# Copyright (c) 1993 - 2025 ARM Limited. All Rights Reserved.
# Use of this Software is subject to the terms and conditions of the
# applicable license agreement with ARM Limited.

# PhyVGen V 11.0.0-beta2
# ARM Version r6p0
# Creation Date: Fri Jan 31 07:39:13 2025


# Memory Configuration:
# ~~~~~~~~~~~~~~~~~~~~~
#  -EOL_guardband 0 -PG_PINS_domain VDDPE -activity_factor 50 -atf off
# -back_biasing off -bit_blast off -bits 64 -bmux off -check_instname on
# -compiler_type sp -diodes on -drive 6 -ema on -flexible_banking 4 -frequency
# 500 -instname sram1024x64 -left_bus_delim "[" -lren_bankmask off -mux 4 -mvt
# BASE -name_case upper -pipeline off -power_gating off -power_type otc -prefix
# "" -pwr_gnd_rename vddpe:VDDPE,vddce:VDDCE,vsse:VSSE -rcols 2 -redundancy off
# -retention on -right_bus_delim "]" -rows_p_bl 256 -rrows 0 -scan off -ser
# none -single_domain_only on -site_def off -vmin_assist on -words 1024
# -write_mask on -write_thru off -corners
# ffg_cbestt_0p88v_0p88v_0c,ffg_cbestt_0p88v_0p88v_125c,ffg_cbestt_0p88v_0p88v_m40c,ssg_cworstt_0p72v_0p72v_0c,ssg_cworstt_0p72v_0p72v_125c,ssg_cworstt_0p72v_0p72v_m40c,tt_typical_0p80v_0p80v_25c,tt_typical_0p80v_0p80v_85c
# 

VERSION 5.8 ;
BUSBITCHARS "[]" ;
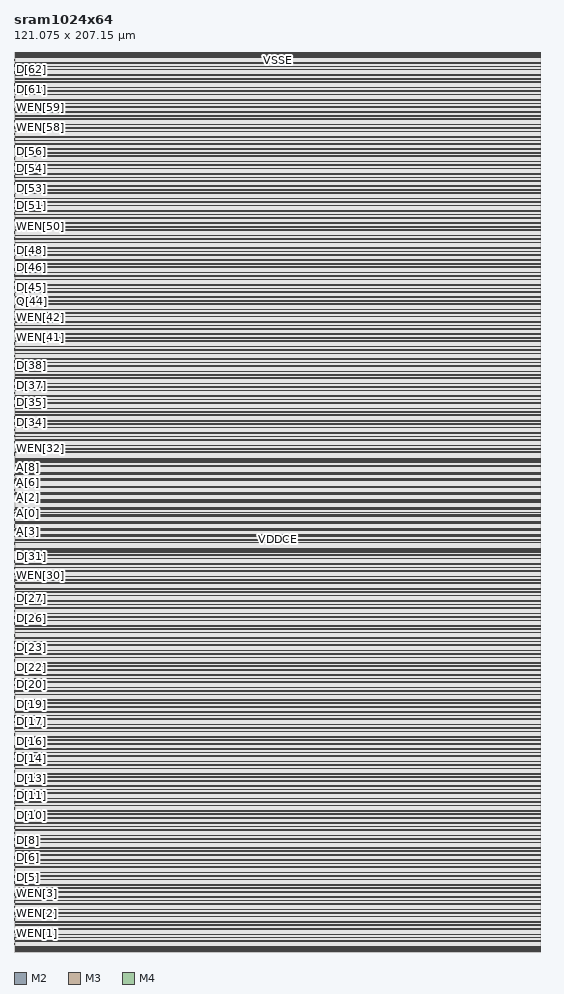
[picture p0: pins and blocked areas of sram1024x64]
MACRO sram1024x64
	FOREIGN sram1024x64 0 0 ;
	SYMMETRY X Y ;
	SIZE 121.075 BY 207.15 ;
	CLASS BLOCK ;
	PIN A[0]
		USE SIGNAL ;
		DIRECTION INPUT ;
		SHAPE ABUTMENT ;
		PORT
			LAYER	M2 ;
			RECT	0.03 100.915 0.15 101.065 ;
			LAYER	M3 ;
			RECT	0.03 100.915 0.15 101.065 ;
		END

		ANTENNAGATEAREA 0.014 ;
		ANTENNADIFFAREA 0.018 ;
		ANTENNAPARTIALMETALAREA 0.025 ;
	END A[0]

	PIN A[1]
		USE SIGNAL ;
		DIRECTION INPUT ;
		SHAPE ABUTMENT ;
		PORT
			LAYER	M2 ;
			RECT	0.03 101.715 0.15 101.865 ;
			LAYER	M3 ;
			RECT	0.03 101.715 0.15 101.865 ;
		END

		ANTENNAGATEAREA 0.014 ;
		ANTENNADIFFAREA 0.018 ;
		ANTENNAPARTIALMETALAREA 0.025 ;
	END A[1]

	PIN A[2]
		USE SIGNAL ;
		DIRECTION INPUT ;
		SHAPE ABUTMENT ;
		PORT
			LAYER	M2 ;
			RECT	0.03 106.315 0.15 106.465 ;
			LAYER	M3 ;
			RECT	0.03 106.315 0.15 106.465 ;
		END

		ANTENNAGATEAREA 0.014 ;
		ANTENNADIFFAREA 0.018 ;
		ANTENNAPARTIALMETALAREA 0.025 ;
	END A[2]

	PIN A[3]
		USE SIGNAL ;
		DIRECTION INPUT ;
		SHAPE ABUTMENT ;
		PORT
			LAYER	M2 ;
			RECT	0.03 96.715 0.15 96.865 ;
			LAYER	M3 ;
			RECT	0.03 96.715 0.15 96.865 ;
		END

		ANTENNAGATEAREA 0.014 ;
		ANTENNADIFFAREA 0.018 ;
		ANTENNAPARTIALMETALAREA 0.025 ;
	END A[3]

	PIN A[4]
		USE SIGNAL ;
		DIRECTION INPUT ;
		SHAPE ABUTMENT ;
		PORT
			LAYER	M2 ;
			RECT	0.03 103.115 0.15 103.265 ;
			LAYER	M3 ;
			RECT	0.03 103.115 0.15 103.265 ;
		END

		ANTENNAGATEAREA 0.014 ;
		ANTENNADIFFAREA 0.018 ;
		ANTENNAPARTIALMETALAREA 0.025 ;
	END A[4]

	PIN A[5]
		USE SIGNAL ;
		DIRECTION INPUT ;
		SHAPE ABUTMENT ;
		PORT
			LAYER	M2 ;
			RECT	0.03 107.115 0.15 107.265 ;
			LAYER	M3 ;
			RECT	0.03 107.115 0.15 107.265 ;
		END

		ANTENNAGATEAREA 0.014 ;
		ANTENNADIFFAREA 0.018 ;
		ANTENNAPARTIALMETALAREA 0.025 ;
	END A[5]

	PIN A[6]
		USE SIGNAL ;
		DIRECTION INPUT ;
		SHAPE ABUTMENT ;
		PORT
			LAYER	M2 ;
			RECT	0.03 107.915 0.15 108.065 ;
			LAYER	M3 ;
			RECT	0.03 107.915 0.15 108.065 ;
		END

		ANTENNAGATEAREA 0.014 ;
		ANTENNADIFFAREA 0.018 ;
		ANTENNAPARTIALMETALAREA 0.025 ;
	END A[6]

	PIN A[7]
		USE SIGNAL ;
		DIRECTION INPUT ;
		SHAPE ABUTMENT ;
		PORT
			LAYER	M2 ;
			RECT	0.03 108.315 0.14 108.665 ;
			LAYER	M3 ;
			RECT	0.03 108.315 0.14 108.665 ;
		END

		ANTENNAGATEAREA 0.014 ;
		ANTENNADIFFAREA 0.018 ;
		ANTENNAPARTIALMETALAREA 0.025 ;
	END A[7]

	PIN A[8]
		USE SIGNAL ;
		DIRECTION INPUT ;
		SHAPE ABUTMENT ;
		PORT
			LAYER	M2 ;
			RECT	0.03 109.715 0.15 109.865 ;
			LAYER	M3 ;
			RECT	0.03 109.715 0.15 109.865 ;
		END

		ANTENNAGATEAREA 0.014 ;
		ANTENNADIFFAREA 0.018 ;
		ANTENNAPARTIALMETALAREA 0.025 ;
	END A[8]

	PIN A[9]
		USE SIGNAL ;
		DIRECTION INPUT ;
		SHAPE ABUTMENT ;
		PORT
			LAYER	M2 ;
			RECT	0.03 110.315 0.15 110.465 ;
			LAYER	M3 ;
			RECT	0.03 110.315 0.15 110.465 ;
		END

		ANTENNAGATEAREA 0.014 ;
		ANTENNADIFFAREA 0.018 ;
		ANTENNAPARTIALMETALAREA 0.025 ;
	END A[9]

	PIN CEN
		USE SIGNAL ;
		DIRECTION INPUT ;
		SHAPE ABUTMENT ;
		PORT
			LAYER	M2 ;
			RECT	0.03 101.315 0.15 101.465 ;
			LAYER	M3 ;
			RECT	0.03 101.315 0.15 101.465 ;
		END

		ANTENNAGATEAREA 0.014 ;
		ANTENNADIFFAREA 0.018 ;
		ANTENNAPARTIALMETALAREA 0.025 ;
	END CEN

	PIN CLK
		USE SIGNAL ;
		DIRECTION INPUT ;
		SHAPE ABUTMENT ;
		PORT
			LAYER	M2 ;
			RECT	0.03 100.315 0.15 100.465 ;
			LAYER	M3 ;
			RECT	0.03 100.315 0.15 100.465 ;
		END

		ANTENNAGATEAREA 0.014 ;
		ANTENNADIFFAREA 0.018 ;
		ANTENNAPARTIALMETALAREA 0.025 ;
	END CLK

	PIN D[0]
		USE SIGNAL ;
		DIRECTION INPUT ;
		SHAPE ABUTMENT ;
		PORT
			LAYER	M2 ;
			RECT	0.03 2.955 0.15 3.105 ;
			LAYER	M3 ;
			RECT	0.03 2.955 0.15 3.105 ;
		END

		ANTENNAGATEAREA 0.014 ;
		ANTENNADIFFAREA 0.018 ;
		ANTENNAPARTIALMETALAREA 0.025 ;
	END D[0]

	PIN D[10]
		USE SIGNAL ;
		DIRECTION INPUT ;
		SHAPE ABUTMENT ;
		PORT
			LAYER	M2 ;
			RECT	0.03 31.355 0.15 31.505 ;
			LAYER	M3 ;
			RECT	0.03 31.355 0.15 31.505 ;
		END

		ANTENNAGATEAREA 0.014 ;
		ANTENNADIFFAREA 0.018 ;
		ANTENNAPARTIALMETALAREA 0.025 ;
	END D[10]

	PIN D[11]
		USE SIGNAL ;
		DIRECTION INPUT ;
		SHAPE ABUTMENT ;
		PORT
			LAYER	M2 ;
			RECT	0.03 34.195 0.15 34.345 ;
			LAYER	M3 ;
			RECT	0.03 34.195 0.15 34.345 ;
		END

		ANTENNAGATEAREA 0.014 ;
		ANTENNADIFFAREA 0.018 ;
		ANTENNAPARTIALMETALAREA 0.025 ;
	END D[11]

	PIN D[12]
		USE SIGNAL ;
		DIRECTION INPUT ;
		SHAPE ABUTMENT ;
		PORT
			LAYER	M2 ;
			RECT	0.03 37.035 0.15 37.185 ;
			LAYER	M3 ;
			RECT	0.03 37.035 0.15 37.185 ;
		END

		ANTENNAGATEAREA 0.014 ;
		ANTENNADIFFAREA 0.018 ;
		ANTENNAPARTIALMETALAREA 0.025 ;
	END D[12]

	PIN D[13]
		USE SIGNAL ;
		DIRECTION INPUT ;
		SHAPE ABUTMENT ;
		PORT
			LAYER	M2 ;
			RECT	0.03 39.875 0.15 40.025 ;
			LAYER	M3 ;
			RECT	0.03 39.875 0.15 40.025 ;
		END

		ANTENNAGATEAREA 0.014 ;
		ANTENNADIFFAREA 0.018 ;
		ANTENNAPARTIALMETALAREA 0.025 ;
	END D[13]

	PIN D[14]
		USE SIGNAL ;
		DIRECTION INPUT ;
		SHAPE ABUTMENT ;
		PORT
			LAYER	M2 ;
			RECT	0.03 42.715 0.15 42.865 ;
			LAYER	M3 ;
			RECT	0.03 42.715 0.15 42.865 ;
		END

		ANTENNAGATEAREA 0.014 ;
		ANTENNADIFFAREA 0.018 ;
		ANTENNAPARTIALMETALAREA 0.025 ;
	END D[14]

	PIN D[15]
		USE SIGNAL ;
		DIRECTION INPUT ;
		SHAPE ABUTMENT ;
		PORT
			LAYER	M2 ;
			RECT	0.03 45.555 0.15 45.705 ;
			LAYER	M3 ;
			RECT	0.03 45.555 0.15 45.705 ;
		END

		ANTENNAGATEAREA 0.014 ;
		ANTENNADIFFAREA 0.018 ;
		ANTENNAPARTIALMETALAREA 0.025 ;
	END D[15]

	PIN D[16]
		USE SIGNAL ;
		DIRECTION INPUT ;
		SHAPE ABUTMENT ;
		PORT
			LAYER	M2 ;
			RECT	0.03 48.395 0.15 48.545 ;
			LAYER	M3 ;
			RECT	0.03 48.395 0.15 48.545 ;
		END

		ANTENNAGATEAREA 0.014 ;
		ANTENNADIFFAREA 0.018 ;
		ANTENNAPARTIALMETALAREA 0.025 ;
	END D[16]

	PIN D[17]
		USE SIGNAL ;
		DIRECTION INPUT ;
		SHAPE ABUTMENT ;
		PORT
			LAYER	M2 ;
			RECT	0.03 51.235 0.15 51.385 ;
			LAYER	M3 ;
			RECT	0.03 51.235 0.15 51.385 ;
		END

		ANTENNAGATEAREA 0.014 ;
		ANTENNADIFFAREA 0.018 ;
		ANTENNAPARTIALMETALAREA 0.025 ;
	END D[17]

	PIN D[18]
		USE SIGNAL ;
		DIRECTION INPUT ;
		SHAPE ABUTMENT ;
		PORT
			LAYER	M2 ;
			RECT	0.03 54.075 0.15 54.225 ;
			LAYER	M3 ;
			RECT	0.03 54.075 0.15 54.225 ;
		END

		ANTENNAGATEAREA 0.014 ;
		ANTENNADIFFAREA 0.018 ;
		ANTENNAPARTIALMETALAREA 0.025 ;
	END D[18]

	PIN D[19]
		USE SIGNAL ;
		DIRECTION INPUT ;
		SHAPE ABUTMENT ;
		PORT
			LAYER	M2 ;
			RECT	0.03 56.915 0.15 57.065 ;
			LAYER	M3 ;
			RECT	0.03 56.915 0.15 57.065 ;
		END

		ANTENNAGATEAREA 0.014 ;
		ANTENNADIFFAREA 0.018 ;
		ANTENNAPARTIALMETALAREA 0.025 ;
	END D[19]

	PIN D[1]
		USE SIGNAL ;
		DIRECTION INPUT ;
		SHAPE ABUTMENT ;
		PORT
			LAYER	M2 ;
			RECT	0.03 5.795 0.15 5.945 ;
			LAYER	M3 ;
			RECT	0.03 5.795 0.15 5.945 ;
		END

		ANTENNAGATEAREA 0.014 ;
		ANTENNADIFFAREA 0.018 ;
		ANTENNAPARTIALMETALAREA 0.025 ;
	END D[1]

	PIN D[20]
		USE SIGNAL ;
		DIRECTION INPUT ;
		SHAPE ABUTMENT ;
		PORT
			LAYER	M2 ;
			RECT	0.03 59.755 0.15 59.905 ;
			LAYER	M3 ;
			RECT	0.03 59.755 0.15 59.905 ;
		END

		ANTENNAGATEAREA 0.014 ;
		ANTENNADIFFAREA 0.018 ;
		ANTENNAPARTIALMETALAREA 0.025 ;
	END D[20]

	PIN D[21]
		USE SIGNAL ;
		DIRECTION INPUT ;
		SHAPE ABUTMENT ;
		PORT
			LAYER	M2 ;
			RECT	0.03 62.595 0.15 62.745 ;
			LAYER	M3 ;
			RECT	0.03 62.595 0.15 62.745 ;
		END

		ANTENNAGATEAREA 0.014 ;
		ANTENNADIFFAREA 0.018 ;
		ANTENNAPARTIALMETALAREA 0.025 ;
	END D[21]

	PIN D[22]
		USE SIGNAL ;
		DIRECTION INPUT ;
		SHAPE ABUTMENT ;
		PORT
			LAYER	M2 ;
			RECT	0.03 65.435 0.15 65.585 ;
			LAYER	M3 ;
			RECT	0.03 65.435 0.15 65.585 ;
		END

		ANTENNAGATEAREA 0.014 ;
		ANTENNADIFFAREA 0.018 ;
		ANTENNAPARTIALMETALAREA 0.025 ;
	END D[22]

	PIN D[23]
		USE SIGNAL ;
		DIRECTION INPUT ;
		SHAPE ABUTMENT ;
		PORT
			LAYER	M2 ;
			RECT	0.03 68.275 0.15 68.425 ;
			LAYER	M3 ;
			RECT	0.03 68.275 0.15 68.425 ;
		END

		ANTENNAGATEAREA 0.014 ;
		ANTENNADIFFAREA 0.018 ;
		ANTENNAPARTIALMETALAREA 0.025 ;
	END D[23]

	PIN D[24]
		USE SIGNAL ;
		DIRECTION INPUT ;
		SHAPE ABUTMENT ;
		PORT
			LAYER	M2 ;
			RECT	0.03 71.115 0.15 71.265 ;
			LAYER	M3 ;
			RECT	0.03 71.115 0.15 71.265 ;
		END

		ANTENNAGATEAREA 0.014 ;
		ANTENNADIFFAREA 0.018 ;
		ANTENNAPARTIALMETALAREA 0.025 ;
	END D[24]

	PIN D[25]
		USE SIGNAL ;
		DIRECTION INPUT ;
		SHAPE ABUTMENT ;
		PORT
			LAYER	M2 ;
			RECT	0.03 73.955 0.15 74.105 ;
			LAYER	M3 ;
			RECT	0.03 73.955 0.15 74.105 ;
		END

		ANTENNAGATEAREA 0.014 ;
		ANTENNADIFFAREA 0.018 ;
		ANTENNAPARTIALMETALAREA 0.025 ;
	END D[25]

	PIN D[26]
		USE SIGNAL ;
		DIRECTION INPUT ;
		SHAPE ABUTMENT ;
		PORT
			LAYER	M2 ;
			RECT	0.03 76.795 0.15 76.945 ;
			LAYER	M3 ;
			RECT	0.03 76.795 0.15 76.945 ;
		END

		ANTENNAGATEAREA 0.014 ;
		ANTENNADIFFAREA 0.018 ;
		ANTENNAPARTIALMETALAREA 0.025 ;
	END D[26]

	PIN D[27]
		USE SIGNAL ;
		DIRECTION INPUT ;
		SHAPE ABUTMENT ;
		PORT
			LAYER	M2 ;
			RECT	0.03 79.635 0.15 79.785 ;
			LAYER	M3 ;
			RECT	0.03 79.635 0.15 79.785 ;
		END

		ANTENNAGATEAREA 0.014 ;
		ANTENNADIFFAREA 0.018 ;
		ANTENNAPARTIALMETALAREA 0.025 ;
	END D[27]

	PIN D[28]
		USE SIGNAL ;
		DIRECTION INPUT ;
		SHAPE ABUTMENT ;
		PORT
			LAYER	M2 ;
			RECT	0.03 82.475 0.15 82.625 ;
			LAYER	M3 ;
			RECT	0.03 82.475 0.15 82.625 ;
		END

		ANTENNAGATEAREA 0.014 ;
		ANTENNADIFFAREA 0.018 ;
		ANTENNAPARTIALMETALAREA 0.025 ;
	END D[28]

	PIN D[29]
		USE SIGNAL ;
		DIRECTION INPUT ;
		SHAPE ABUTMENT ;
		PORT
			LAYER	M2 ;
			RECT	0.03 85.315 0.15 85.465 ;
			LAYER	M3 ;
			RECT	0.03 85.315 0.15 85.465 ;
		END

		ANTENNAGATEAREA 0.014 ;
		ANTENNADIFFAREA 0.018 ;
		ANTENNAPARTIALMETALAREA 0.025 ;
	END D[29]

	PIN D[2]
		USE SIGNAL ;
		DIRECTION INPUT ;
		SHAPE ABUTMENT ;
		PORT
			LAYER	M2 ;
			RECT	0.03 8.635 0.15 8.785 ;
			LAYER	M3 ;
			RECT	0.03 8.635 0.15 8.785 ;
		END

		ANTENNAGATEAREA 0.014 ;
		ANTENNADIFFAREA 0.018 ;
		ANTENNAPARTIALMETALAREA 0.025 ;
	END D[2]

	PIN D[30]
		USE SIGNAL ;
		DIRECTION INPUT ;
		SHAPE ABUTMENT ;
		PORT
			LAYER	M2 ;
			RECT	0.03 88.155 0.15 88.305 ;
			LAYER	M3 ;
			RECT	0.03 88.155 0.15 88.305 ;
		END

		ANTENNAGATEAREA 0.014 ;
		ANTENNADIFFAREA 0.018 ;
		ANTENNAPARTIALMETALAREA 0.025 ;
	END D[30]

	PIN D[31]
		USE SIGNAL ;
		DIRECTION INPUT ;
		SHAPE ABUTMENT ;
		PORT
			LAYER	M2 ;
			RECT	0.03 90.995 0.15 91.145 ;
			LAYER	M3 ;
			RECT	0.03 90.995 0.15 91.145 ;
		END

		ANTENNAGATEAREA 0.014 ;
		ANTENNADIFFAREA 0.018 ;
		ANTENNAPARTIALMETALAREA 0.025 ;
	END D[31]

	PIN D[32]
		USE SIGNAL ;
		DIRECTION INPUT ;
		SHAPE ABUTMENT ;
		PORT
			LAYER	M2 ;
			RECT	0.03 116.005 0.15 116.155 ;
			LAYER	M3 ;
			RECT	0.03 116.005 0.15 116.155 ;
		END

		ANTENNAGATEAREA 0.014 ;
		ANTENNADIFFAREA 0.018 ;
		ANTENNAPARTIALMETALAREA 0.025 ;
	END D[32]

	PIN D[33]
		USE SIGNAL ;
		DIRECTION INPUT ;
		SHAPE ABUTMENT ;
		PORT
			LAYER	M2 ;
			RECT	0.03 118.845 0.15 118.995 ;
			LAYER	M3 ;
			RECT	0.03 118.845 0.15 118.995 ;
		END

		ANTENNAGATEAREA 0.014 ;
		ANTENNADIFFAREA 0.018 ;
		ANTENNAPARTIALMETALAREA 0.025 ;
	END D[33]

	PIN D[34]
		USE SIGNAL ;
		DIRECTION INPUT ;
		SHAPE ABUTMENT ;
		PORT
			LAYER	M2 ;
			RECT	0.03 121.685 0.15 121.835 ;
			LAYER	M3 ;
			RECT	0.03 121.685 0.15 121.835 ;
		END

		ANTENNAGATEAREA 0.014 ;
		ANTENNADIFFAREA 0.018 ;
		ANTENNAPARTIALMETALAREA 0.025 ;
	END D[34]

	PIN D[35]
		USE SIGNAL ;
		DIRECTION INPUT ;
		SHAPE ABUTMENT ;
		PORT
			LAYER	M2 ;
			RECT	0.03 124.525 0.15 124.675 ;
			LAYER	M3 ;
			RECT	0.03 124.525 0.15 124.675 ;
		END

		ANTENNAGATEAREA 0.014 ;
		ANTENNADIFFAREA 0.018 ;
		ANTENNAPARTIALMETALAREA 0.025 ;
	END D[35]

	PIN D[36]
		USE SIGNAL ;
		DIRECTION INPUT ;
		SHAPE ABUTMENT ;
		PORT
			LAYER	M2 ;
			RECT	0.03 127.365 0.15 127.515 ;
			LAYER	M3 ;
			RECT	0.03 127.365 0.15 127.515 ;
		END

		ANTENNAGATEAREA 0.014 ;
		ANTENNADIFFAREA 0.018 ;
		ANTENNAPARTIALMETALAREA 0.025 ;
	END D[36]

	PIN D[37]
		USE SIGNAL ;
		DIRECTION INPUT ;
		SHAPE ABUTMENT ;
		PORT
			LAYER	M2 ;
			RECT	0.03 130.205 0.15 130.355 ;
			LAYER	M3 ;
			RECT	0.03 130.205 0.15 130.355 ;
		END

		ANTENNAGATEAREA 0.014 ;
		ANTENNADIFFAREA 0.018 ;
		ANTENNAPARTIALMETALAREA 0.025 ;
	END D[37]

	PIN D[38]
		USE SIGNAL ;
		DIRECTION INPUT ;
		SHAPE ABUTMENT ;
		PORT
			LAYER	M2 ;
			RECT	0.03 133.045 0.15 133.195 ;
			LAYER	M3 ;
			RECT	0.03 133.045 0.15 133.195 ;
		END

		ANTENNAGATEAREA 0.014 ;
		ANTENNADIFFAREA 0.018 ;
		ANTENNAPARTIALMETALAREA 0.025 ;
	END D[38]

	PIN D[39]
		USE SIGNAL ;
		DIRECTION INPUT ;
		SHAPE ABUTMENT ;
		PORT
			LAYER	M2 ;
			RECT	0.03 135.885 0.15 136.035 ;
			LAYER	M3 ;
			RECT	0.03 135.885 0.15 136.035 ;
		END

		ANTENNAGATEAREA 0.014 ;
		ANTENNADIFFAREA 0.018 ;
		ANTENNAPARTIALMETALAREA 0.025 ;
	END D[39]

	PIN D[3]
		USE SIGNAL ;
		DIRECTION INPUT ;
		SHAPE ABUTMENT ;
		PORT
			LAYER	M2 ;
			RECT	0.03 11.475 0.15 11.625 ;
			LAYER	M3 ;
			RECT	0.03 11.475 0.15 11.625 ;
		END

		ANTENNAGATEAREA 0.014 ;
		ANTENNADIFFAREA 0.018 ;
		ANTENNAPARTIALMETALAREA 0.025 ;
	END D[3]

	PIN D[40]
		USE SIGNAL ;
		DIRECTION INPUT ;
		SHAPE ABUTMENT ;
		PORT
			LAYER	M2 ;
			RECT	0.03 138.725 0.15 138.875 ;
			LAYER	M3 ;
			RECT	0.03 138.725 0.15 138.875 ;
		END

		ANTENNAGATEAREA 0.014 ;
		ANTENNADIFFAREA 0.018 ;
		ANTENNAPARTIALMETALAREA 0.025 ;
	END D[40]

	PIN D[41]
		USE SIGNAL ;
		DIRECTION INPUT ;
		SHAPE ABUTMENT ;
		PORT
			LAYER	M2 ;
			RECT	0.03 141.565 0.15 141.715 ;
			LAYER	M3 ;
			RECT	0.03 141.565 0.15 141.715 ;
		END

		ANTENNAGATEAREA 0.014 ;
		ANTENNADIFFAREA 0.018 ;
		ANTENNAPARTIALMETALAREA 0.025 ;
	END D[41]

	PIN D[42]
		USE SIGNAL ;
		DIRECTION INPUT ;
		SHAPE ABUTMENT ;
		PORT
			LAYER	M2 ;
			RECT	0.03 144.405 0.15 144.555 ;
			LAYER	M3 ;
			RECT	0.03 144.405 0.15 144.555 ;
		END

		ANTENNAGATEAREA 0.014 ;
		ANTENNADIFFAREA 0.018 ;
		ANTENNAPARTIALMETALAREA 0.025 ;
	END D[42]

	PIN D[43]
		USE SIGNAL ;
		DIRECTION INPUT ;
		SHAPE ABUTMENT ;
		PORT
			LAYER	M2 ;
			RECT	0.03 147.245 0.15 147.395 ;
			LAYER	M3 ;
			RECT	0.03 147.245 0.15 147.395 ;
		END

		ANTENNAGATEAREA 0.014 ;
		ANTENNADIFFAREA 0.018 ;
		ANTENNAPARTIALMETALAREA 0.025 ;
	END D[43]

	PIN D[44]
		USE SIGNAL ;
		DIRECTION INPUT ;
		SHAPE ABUTMENT ;
		PORT
			LAYER	M2 ;
			RECT	0.03 150.085 0.15 150.235 ;
			LAYER	M3 ;
			RECT	0.03 150.085 0.15 150.235 ;
		END

		ANTENNAGATEAREA 0.014 ;
		ANTENNADIFFAREA 0.018 ;
		ANTENNAPARTIALMETALAREA 0.025 ;
	END D[44]

	PIN D[45]
		USE SIGNAL ;
		DIRECTION INPUT ;
		SHAPE ABUTMENT ;
		PORT
			LAYER	M2 ;
			RECT	0.03 152.925 0.15 153.075 ;
			LAYER	M3 ;
			RECT	0.03 152.925 0.15 153.075 ;
		END

		ANTENNAGATEAREA 0.014 ;
		ANTENNADIFFAREA 0.018 ;
		ANTENNAPARTIALMETALAREA 0.025 ;
	END D[45]

	PIN D[46]
		USE SIGNAL ;
		DIRECTION INPUT ;
		SHAPE ABUTMENT ;
		PORT
			LAYER	M2 ;
			RECT	0.03 155.765 0.15 155.915 ;
			LAYER	M3 ;
			RECT	0.03 155.765 0.15 155.915 ;
		END

		ANTENNAGATEAREA 0.014 ;
		ANTENNADIFFAREA 0.018 ;
		ANTENNAPARTIALMETALAREA 0.025 ;
	END D[46]

	PIN D[47]
		USE SIGNAL ;
		DIRECTION INPUT ;
		SHAPE ABUTMENT ;
		PORT
			LAYER	M2 ;
			RECT	0.03 158.605 0.15 158.755 ;
			LAYER	M3 ;
			RECT	0.03 158.605 0.15 158.755 ;
		END

		ANTENNAGATEAREA 0.014 ;
		ANTENNADIFFAREA 0.018 ;
		ANTENNAPARTIALMETALAREA 0.025 ;
	END D[47]

	PIN D[48]
		USE SIGNAL ;
		DIRECTION INPUT ;
		SHAPE ABUTMENT ;
		PORT
			LAYER	M2 ;
			RECT	0.03 161.445 0.15 161.595 ;
			LAYER	M3 ;
			RECT	0.03 161.445 0.15 161.595 ;
		END

		ANTENNAGATEAREA 0.014 ;
		ANTENNADIFFAREA 0.018 ;
		ANTENNAPARTIALMETALAREA 0.025 ;
	END D[48]

	PIN D[49]
		USE SIGNAL ;
		DIRECTION INPUT ;
		SHAPE ABUTMENT ;
		PORT
			LAYER	M2 ;
			RECT	0.03 164.285 0.15 164.435 ;
			LAYER	M3 ;
			RECT	0.03 164.285 0.15 164.435 ;
		END

		ANTENNAGATEAREA 0.014 ;
		ANTENNADIFFAREA 0.018 ;
		ANTENNAPARTIALMETALAREA 0.025 ;
	END D[49]

	PIN D[4]
		USE SIGNAL ;
		DIRECTION INPUT ;
		SHAPE ABUTMENT ;
		PORT
			LAYER	M2 ;
			RECT	0.03 14.315 0.15 14.465 ;
			LAYER	M3 ;
			RECT	0.03 14.315 0.15 14.465 ;
		END

		ANTENNAGATEAREA 0.014 ;
		ANTENNADIFFAREA 0.018 ;
		ANTENNAPARTIALMETALAREA 0.025 ;
	END D[4]

	PIN D[50]
		USE SIGNAL ;
		DIRECTION INPUT ;
		SHAPE ABUTMENT ;
		PORT
			LAYER	M2 ;
			RECT	0.03 167.125 0.15 167.275 ;
			LAYER	M3 ;
			RECT	0.03 167.125 0.15 167.275 ;
		END

		ANTENNAGATEAREA 0.014 ;
		ANTENNADIFFAREA 0.018 ;
		ANTENNAPARTIALMETALAREA 0.025 ;
	END D[50]

	PIN D[51]
		USE SIGNAL ;
		DIRECTION INPUT ;
		SHAPE ABUTMENT ;
		PORT
			LAYER	M2 ;
			RECT	0.03 169.965 0.15 170.115 ;
			LAYER	M3 ;
			RECT	0.03 169.965 0.15 170.115 ;
		END

		ANTENNAGATEAREA 0.014 ;
		ANTENNADIFFAREA 0.018 ;
		ANTENNAPARTIALMETALAREA 0.025 ;
	END D[51]

	PIN D[52]
		USE SIGNAL ;
		DIRECTION INPUT ;
		SHAPE ABUTMENT ;
		PORT
			LAYER	M2 ;
			RECT	0.03 172.805 0.15 172.955 ;
			LAYER	M3 ;
			RECT	0.03 172.805 0.15 172.955 ;
		END

		ANTENNAGATEAREA 0.014 ;
		ANTENNADIFFAREA 0.018 ;
		ANTENNAPARTIALMETALAREA 0.025 ;
	END D[52]

	PIN D[53]
		USE SIGNAL ;
		DIRECTION INPUT ;
		SHAPE ABUTMENT ;
		PORT
			LAYER	M2 ;
			RECT	0.03 175.645 0.15 175.795 ;
			LAYER	M3 ;
			RECT	0.03 175.645 0.15 175.795 ;
		END

		ANTENNAGATEAREA 0.014 ;
		ANTENNADIFFAREA 0.018 ;
		ANTENNAPARTIALMETALAREA 0.025 ;
	END D[53]

	PIN D[54]
		USE SIGNAL ;
		DIRECTION INPUT ;
		SHAPE ABUTMENT ;
		PORT
			LAYER	M2 ;
			RECT	0.03 178.485 0.15 178.635 ;
			LAYER	M3 ;
			RECT	0.03 178.485 0.15 178.635 ;
		END

		ANTENNAGATEAREA 0.014 ;
		ANTENNADIFFAREA 0.018 ;
		ANTENNAPARTIALMETALAREA 0.025 ;
	END D[54]

	PIN D[55]
		USE SIGNAL ;
		DIRECTION INPUT ;
		SHAPE ABUTMENT ;
		PORT
			LAYER	M2 ;
			RECT	0.03 181.325 0.15 181.475 ;
			LAYER	M3 ;
			RECT	0.03 181.325 0.15 181.475 ;
		END

		ANTENNAGATEAREA 0.014 ;
		ANTENNADIFFAREA 0.018 ;
		ANTENNAPARTIALMETALAREA 0.025 ;
	END D[55]

	PIN D[56]
		USE SIGNAL ;
		DIRECTION INPUT ;
		SHAPE ABUTMENT ;
		PORT
			LAYER	M2 ;
			RECT	0.03 184.165 0.15 184.315 ;
			LAYER	M3 ;
			RECT	0.03 184.165 0.15 184.315 ;
		END

		ANTENNAGATEAREA 0.014 ;
		ANTENNADIFFAREA 0.018 ;
		ANTENNAPARTIALMETALAREA 0.025 ;
	END D[56]

	PIN D[57]
		USE SIGNAL ;
		DIRECTION INPUT ;
		SHAPE ABUTMENT ;
		PORT
			LAYER	M2 ;
			RECT	0.03 187.005 0.15 187.155 ;
			LAYER	M3 ;
			RECT	0.03 187.005 0.15 187.155 ;
		END

		ANTENNAGATEAREA 0.014 ;
		ANTENNADIFFAREA 0.018 ;
		ANTENNAPARTIALMETALAREA 0.025 ;
	END D[57]

	PIN D[58]
		USE SIGNAL ;
		DIRECTION INPUT ;
		SHAPE ABUTMENT ;
		PORT
			LAYER	M2 ;
			RECT	0.03 189.845 0.15 189.995 ;
			LAYER	M3 ;
			RECT	0.03 189.845 0.15 189.995 ;
		END

		ANTENNAGATEAREA 0.014 ;
		ANTENNADIFFAREA 0.018 ;
		ANTENNAPARTIALMETALAREA 0.025 ;
	END D[58]

	PIN D[59]
		USE SIGNAL ;
		DIRECTION INPUT ;
		SHAPE ABUTMENT ;
		PORT
			LAYER	M2 ;
			RECT	0.03 192.685 0.15 192.835 ;
			LAYER	M3 ;
			RECT	0.03 192.685 0.15 192.835 ;
		END

		ANTENNAGATEAREA 0.014 ;
		ANTENNADIFFAREA 0.018 ;
		ANTENNAPARTIALMETALAREA 0.025 ;
	END D[59]

	PIN D[5]
		USE SIGNAL ;
		DIRECTION INPUT ;
		SHAPE ABUTMENT ;
		PORT
			LAYER	M2 ;
			RECT	0.03 17.155 0.15 17.305 ;
			LAYER	M3 ;
			RECT	0.03 17.155 0.15 17.305 ;
		END

		ANTENNAGATEAREA 0.014 ;
		ANTENNADIFFAREA 0.018 ;
		ANTENNAPARTIALMETALAREA 0.025 ;
	END D[5]

	PIN D[60]
		USE SIGNAL ;
		DIRECTION INPUT ;
		SHAPE ABUTMENT ;
		PORT
			LAYER	M2 ;
			RECT	0.03 195.525 0.15 195.675 ;
			LAYER	M3 ;
			RECT	0.03 195.525 0.15 195.675 ;
		END

		ANTENNAGATEAREA 0.014 ;
		ANTENNADIFFAREA 0.018 ;
		ANTENNAPARTIALMETALAREA 0.025 ;
	END D[60]

	PIN D[61]
		USE SIGNAL ;
		DIRECTION INPUT ;
		SHAPE ABUTMENT ;
		PORT
			LAYER	M2 ;
			RECT	0.03 198.365 0.15 198.515 ;
			LAYER	M3 ;
			RECT	0.03 198.365 0.15 198.515 ;
		END

		ANTENNAGATEAREA 0.014 ;
		ANTENNADIFFAREA 0.018 ;
		ANTENNAPARTIALMETALAREA 0.025 ;
	END D[61]

	PIN D[62]
		USE SIGNAL ;
		DIRECTION INPUT ;
		SHAPE ABUTMENT ;
		PORT
			LAYER	M2 ;
			RECT	0.03 201.205 0.15 201.355 ;
			LAYER	M3 ;
			RECT	0.03 201.205 0.15 201.355 ;
		END

		ANTENNAGATEAREA 0.014 ;
		ANTENNADIFFAREA 0.018 ;
		ANTENNAPARTIALMETALAREA 0.025 ;
	END D[62]

	PIN D[63]
		USE SIGNAL ;
		DIRECTION INPUT ;
		SHAPE ABUTMENT ;
		PORT
			LAYER	M2 ;
			RECT	0.03 204.045 0.15 204.195 ;
			LAYER	M3 ;
			RECT	0.03 204.045 0.15 204.195 ;
		END

		ANTENNAGATEAREA 0.014 ;
		ANTENNADIFFAREA 0.018 ;
		ANTENNAPARTIALMETALAREA 0.025 ;
	END D[63]

	PIN D[6]
		USE SIGNAL ;
		DIRECTION INPUT ;
		SHAPE ABUTMENT ;
		PORT
			LAYER	M2 ;
			RECT	0.03 19.995 0.15 20.145 ;
			LAYER	M3 ;
			RECT	0.03 19.995 0.15 20.145 ;
		END

		ANTENNAGATEAREA 0.014 ;
		ANTENNADIFFAREA 0.018 ;
		ANTENNAPARTIALMETALAREA 0.025 ;
	END D[6]

	PIN D[7]
		USE SIGNAL ;
		DIRECTION INPUT ;
		SHAPE ABUTMENT ;
		PORT
			LAYER	M2 ;
			RECT	0.03 22.835 0.15 22.985 ;
			LAYER	M3 ;
			RECT	0.03 22.835 0.15 22.985 ;
		END

		ANTENNAGATEAREA 0.014 ;
		ANTENNADIFFAREA 0.018 ;
		ANTENNAPARTIALMETALAREA 0.025 ;
	END D[7]

	PIN D[8]
		USE SIGNAL ;
		DIRECTION INPUT ;
		SHAPE ABUTMENT ;
		PORT
			LAYER	M2 ;
			RECT	0.03 25.675 0.15 25.825 ;
			LAYER	M3 ;
			RECT	0.03 25.675 0.15 25.825 ;
		END

		ANTENNAGATEAREA 0.014 ;
		ANTENNADIFFAREA 0.018 ;
		ANTENNAPARTIALMETALAREA 0.025 ;
	END D[8]

	PIN D[9]
		USE SIGNAL ;
		DIRECTION INPUT ;
		SHAPE ABUTMENT ;
		PORT
			LAYER	M2 ;
			RECT	0.03 28.515 0.15 28.665 ;
			LAYER	M3 ;
			RECT	0.03 28.515 0.15 28.665 ;
		END

		ANTENNAGATEAREA 0.014 ;
		ANTENNADIFFAREA 0.018 ;
		ANTENNAPARTIALMETALAREA 0.025 ;
	END D[9]

	PIN EMAS
		USE SIGNAL ;
		DIRECTION INPUT ;
		SHAPE ABUTMENT ;
		PORT
			LAYER	M2 ;
			RECT	0.03 99.515 0.15 99.665 ;
			LAYER	M3 ;
			RECT	0.03 99.515 0.15 99.665 ;
		END

		ANTENNAGATEAREA 0.014 ;
		ANTENNADIFFAREA 0.018 ;
		ANTENNAPARTIALMETALAREA 0.025 ;
	END EMAS

	PIN EMAW[0]
		USE SIGNAL ;
		DIRECTION INPUT ;
		SHAPE ABUTMENT ;
		PORT
			LAYER	M2 ;
			RECT	0.03 99.915 0.15 100.065 ;
			LAYER	M3 ;
			RECT	0.03 99.915 0.15 100.065 ;
		END

		ANTENNAGATEAREA 0.014 ;
		ANTENNADIFFAREA 0.018 ;
		ANTENNAPARTIALMETALAREA 0.025 ;
	END EMAW[0]

	PIN EMAW[1]
		USE SIGNAL ;
		DIRECTION INPUT ;
		SHAPE ABUTMENT ;
		PORT
			LAYER	M2 ;
			RECT	0.03 99.315 0.15 99.465 ;
			LAYER	M3 ;
			RECT	0.03 99.315 0.15 99.465 ;
		END

		ANTENNAGATEAREA 0.014 ;
		ANTENNADIFFAREA 0.018 ;
		ANTENNAPARTIALMETALAREA 0.025 ;
	END EMAW[1]

	PIN EMA[0]
		USE SIGNAL ;
		DIRECTION INPUT ;
		SHAPE ABUTMENT ;
		PORT
			LAYER	M2 ;
			RECT	0.03 97.815 0.14 98.165 ;
			LAYER	M3 ;
			RECT	0.03 97.815 0.14 98.165 ;
		END

		ANTENNAGATEAREA 0.014 ;
		ANTENNADIFFAREA 0.018 ;
		ANTENNAPARTIALMETALAREA 0.025 ;
	END EMA[0]

	PIN EMA[1]
		USE SIGNAL ;
		DIRECTION INPUT ;
		SHAPE ABUTMENT ;
		PORT
			LAYER	M2 ;
			RECT	0.03 97.615 0.15 97.765 ;
			LAYER	M3 ;
			RECT	0.03 97.615 0.15 97.765 ;
		END

		ANTENNAGATEAREA 0.014 ;
		ANTENNADIFFAREA 0.018 ;
		ANTENNAPARTIALMETALAREA 0.025 ;
	END EMA[1]

	PIN EMA[2]
		USE SIGNAL ;
		DIRECTION INPUT ;
		SHAPE ABUTMENT ;
		PORT
			LAYER	M2 ;
			RECT	0.03 97.115 0.15 97.265 ;
			LAYER	M3 ;
			RECT	0.03 97.115 0.15 97.265 ;
		END

		ANTENNAGATEAREA 0.014 ;
		ANTENNADIFFAREA 0.018 ;
		ANTENNAPARTIALMETALAREA 0.025 ;
	END EMA[2]

	PIN GWEN
		USE SIGNAL ;
		DIRECTION INPUT ;
		SHAPE ABUTMENT ;
		PORT
			LAYER	M2 ;
			RECT	0.03 95.815 0.15 95.965 ;
			LAYER	M3 ;
			RECT	0.03 95.815 0.15 95.965 ;
		END

		ANTENNAGATEAREA 0.014 ;
		ANTENNADIFFAREA 0.018 ;
		ANTENNAPARTIALMETALAREA 0.025 ;
	END GWEN

	PIN Q[0]
		USE SIGNAL ;
		DIRECTION OUTPUT ;
		SHAPE ABUTMENT ;
		PORT
			LAYER	M2 ;
			RECT	0.03 1.645 0.14 1.995 ;
			LAYER	M3 ;
			RECT	0.03 1.645 0.14 1.995 ;
		END

		ANTENNADIFFAREA 0.018 ;
		ANTENNAPARTIALMETALAREA 0.025 ;
	END Q[0]

	PIN Q[10]
		USE SIGNAL ;
		DIRECTION OUTPUT ;
		SHAPE ABUTMENT ;
		PORT
			LAYER	M2 ;
			RECT	0.03 30.045 0.14 30.395 ;
			LAYER	M3 ;
			RECT	0.03 30.045 0.14 30.395 ;
		END

		ANTENNADIFFAREA 0.018 ;
		ANTENNAPARTIALMETALAREA 0.025 ;
	END Q[10]

	PIN Q[11]
		USE SIGNAL ;
		DIRECTION OUTPUT ;
		SHAPE ABUTMENT ;
		PORT
			LAYER	M2 ;
			RECT	0.03 32.885 0.14 33.235 ;
			LAYER	M3 ;
			RECT	0.03 32.885 0.14 33.235 ;
		END

		ANTENNADIFFAREA 0.018 ;
		ANTENNAPARTIALMETALAREA 0.025 ;
	END Q[11]

	PIN Q[12]
		USE SIGNAL ;
		DIRECTION OUTPUT ;
		SHAPE ABUTMENT ;
		PORT
			LAYER	M2 ;
			RECT	0.03 35.725 0.14 36.075 ;
			LAYER	M3 ;
			RECT	0.03 35.725 0.14 36.075 ;
		END

		ANTENNADIFFAREA 0.018 ;
		ANTENNAPARTIALMETALAREA 0.025 ;
	END Q[12]

	PIN Q[13]
		USE SIGNAL ;
		DIRECTION OUTPUT ;
		SHAPE ABUTMENT ;
		PORT
			LAYER	M2 ;
			RECT	0.03 38.565 0.14 38.915 ;
			LAYER	M3 ;
			RECT	0.03 38.565 0.14 38.915 ;
		END

		ANTENNADIFFAREA 0.018 ;
		ANTENNAPARTIALMETALAREA 0.025 ;
	END Q[13]

	PIN Q[14]
		USE SIGNAL ;
		DIRECTION OUTPUT ;
		SHAPE ABUTMENT ;
		PORT
			LAYER	M2 ;
			RECT	0.03 41.405 0.14 41.755 ;
			LAYER	M3 ;
			RECT	0.03 41.405 0.14 41.755 ;
		END

		ANTENNADIFFAREA 0.018 ;
		ANTENNAPARTIALMETALAREA 0.025 ;
	END Q[14]

	PIN Q[15]
		USE SIGNAL ;
		DIRECTION OUTPUT ;
		SHAPE ABUTMENT ;
		PORT
			LAYER	M2 ;
			RECT	0.03 44.245 0.14 44.595 ;
			LAYER	M3 ;
			RECT	0.03 44.245 0.14 44.595 ;
		END

		ANTENNADIFFAREA 0.018 ;
		ANTENNAPARTIALMETALAREA 0.025 ;
	END Q[15]

	PIN Q[16]
		USE SIGNAL ;
		DIRECTION OUTPUT ;
		SHAPE ABUTMENT ;
		PORT
			LAYER	M2 ;
			RECT	0.03 47.085 0.14 47.435 ;
			LAYER	M3 ;
			RECT	0.03 47.085 0.14 47.435 ;
		END

		ANTENNADIFFAREA 0.018 ;
		ANTENNAPARTIALMETALAREA 0.025 ;
	END Q[16]

	PIN Q[17]
		USE SIGNAL ;
		DIRECTION OUTPUT ;
		SHAPE ABUTMENT ;
		PORT
			LAYER	M2 ;
			RECT	0.03 49.925 0.14 50.275 ;
			LAYER	M3 ;
			RECT	0.03 49.925 0.14 50.275 ;
		END

		ANTENNADIFFAREA 0.018 ;
		ANTENNAPARTIALMETALAREA 0.025 ;
	END Q[17]

	PIN Q[18]
		USE SIGNAL ;
		DIRECTION OUTPUT ;
		SHAPE ABUTMENT ;
		PORT
			LAYER	M2 ;
			RECT	0.03 52.765 0.14 53.115 ;
			LAYER	M3 ;
			RECT	0.03 52.765 0.14 53.115 ;
		END

		ANTENNADIFFAREA 0.018 ;
		ANTENNAPARTIALMETALAREA 0.025 ;
	END Q[18]

	PIN Q[19]
		USE SIGNAL ;
		DIRECTION OUTPUT ;
		SHAPE ABUTMENT ;
		PORT
			LAYER	M2 ;
			RECT	0.03 55.605 0.14 55.955 ;
			LAYER	M3 ;
			RECT	0.03 55.605 0.14 55.955 ;
		END

		ANTENNADIFFAREA 0.018 ;
		ANTENNAPARTIALMETALAREA 0.025 ;
	END Q[19]

	PIN Q[1]
		USE SIGNAL ;
		DIRECTION OUTPUT ;
		SHAPE ABUTMENT ;
		PORT
			LAYER	M2 ;
			RECT	0.03 4.485 0.14 4.835 ;
			LAYER	M3 ;
			RECT	0.03 4.485 0.14 4.835 ;
		END

		ANTENNADIFFAREA 0.018 ;
		ANTENNAPARTIALMETALAREA 0.025 ;
	END Q[1]

	PIN Q[20]
		USE SIGNAL ;
		DIRECTION OUTPUT ;
		SHAPE ABUTMENT ;
		PORT
			LAYER	M2 ;
			RECT	0.03 58.445 0.14 58.795 ;
			LAYER	M3 ;
			RECT	0.03 58.445 0.14 58.795 ;
		END

		ANTENNADIFFAREA 0.018 ;
		ANTENNAPARTIALMETALAREA 0.025 ;
	END Q[20]

	PIN Q[21]
		USE SIGNAL ;
		DIRECTION OUTPUT ;
		SHAPE ABUTMENT ;
		PORT
			LAYER	M2 ;
			RECT	0.03 61.285 0.14 61.635 ;
			LAYER	M3 ;
			RECT	0.03 61.285 0.14 61.635 ;
		END

		ANTENNADIFFAREA 0.018 ;
		ANTENNAPARTIALMETALAREA 0.025 ;
	END Q[21]

	PIN Q[22]
		USE SIGNAL ;
		DIRECTION OUTPUT ;
		SHAPE ABUTMENT ;
		PORT
			LAYER	M2 ;
			RECT	0.03 64.125 0.14 64.475 ;
			LAYER	M3 ;
			RECT	0.03 64.125 0.14 64.475 ;
		END

		ANTENNADIFFAREA 0.018 ;
		ANTENNAPARTIALMETALAREA 0.025 ;
	END Q[22]

	PIN Q[23]
		USE SIGNAL ;
		DIRECTION OUTPUT ;
		SHAPE ABUTMENT ;
		PORT
			LAYER	M2 ;
			RECT	0.03 66.965 0.14 67.315 ;
			LAYER	M3 ;
			RECT	0.03 66.965 0.14 67.315 ;
		END

		ANTENNADIFFAREA 0.018 ;
		ANTENNAPARTIALMETALAREA 0.025 ;
	END Q[23]

	PIN Q[24]
		USE SIGNAL ;
		DIRECTION OUTPUT ;
		SHAPE ABUTMENT ;
		PORT
			LAYER	M2 ;
			RECT	0.03 69.805 0.14 70.155 ;
			LAYER	M3 ;
			RECT	0.03 69.805 0.14 70.155 ;
		END

		ANTENNADIFFAREA 0.018 ;
		ANTENNAPARTIALMETALAREA 0.025 ;
	END Q[24]

	PIN Q[25]
		USE SIGNAL ;
		DIRECTION OUTPUT ;
		SHAPE ABUTMENT ;
		PORT
			LAYER	M2 ;
			RECT	0.03 72.645 0.14 72.995 ;
			LAYER	M3 ;
			RECT	0.03 72.645 0.14 72.995 ;
		END

		ANTENNADIFFAREA 0.018 ;
		ANTENNAPARTIALMETALAREA 0.025 ;
	END Q[25]

	PIN Q[26]
		USE SIGNAL ;
		DIRECTION OUTPUT ;
		SHAPE ABUTMENT ;
		PORT
			LAYER	M2 ;
			RECT	0.03 75.485 0.14 75.835 ;
			LAYER	M3 ;
			RECT	0.03 75.485 0.14 75.835 ;
		END

		ANTENNADIFFAREA 0.018 ;
		ANTENNAPARTIALMETALAREA 0.025 ;
	END Q[26]

	PIN Q[27]
		USE SIGNAL ;
		DIRECTION OUTPUT ;
		SHAPE ABUTMENT ;
		PORT
			LAYER	M2 ;
			RECT	0.03 78.325 0.14 78.675 ;
			LAYER	M3 ;
			RECT	0.03 78.325 0.14 78.675 ;
		END

		ANTENNADIFFAREA 0.018 ;
		ANTENNAPARTIALMETALAREA 0.025 ;
	END Q[27]

	PIN Q[28]
		USE SIGNAL ;
		DIRECTION OUTPUT ;
		SHAPE ABUTMENT ;
		PORT
			LAYER	M2 ;
			RECT	0.03 81.165 0.14 81.515 ;
			LAYER	M3 ;
			RECT	0.03 81.165 0.14 81.515 ;
		END

		ANTENNADIFFAREA 0.018 ;
		ANTENNAPARTIALMETALAREA 0.025 ;
	END Q[28]

	PIN Q[29]
		USE SIGNAL ;
		DIRECTION OUTPUT ;
		SHAPE ABUTMENT ;
		PORT
			LAYER	M2 ;
			RECT	0.03 84.005 0.14 84.355 ;
			LAYER	M3 ;
			RECT	0.03 84.005 0.14 84.355 ;
		END

		ANTENNADIFFAREA 0.018 ;
		ANTENNAPARTIALMETALAREA 0.025 ;
	END Q[29]

	PIN Q[2]
		USE SIGNAL ;
		DIRECTION OUTPUT ;
		SHAPE ABUTMENT ;
		PORT
			LAYER	M2 ;
			RECT	0.03 7.325 0.14 7.675 ;
			LAYER	M3 ;
			RECT	0.03 7.325 0.14 7.675 ;
		END

		ANTENNADIFFAREA 0.018 ;
		ANTENNAPARTIALMETALAREA 0.025 ;
	END Q[2]

	PIN Q[30]
		USE SIGNAL ;
		DIRECTION OUTPUT ;
		SHAPE ABUTMENT ;
		PORT
			LAYER	M2 ;
			RECT	0.03 86.845 0.14 87.195 ;
			LAYER	M3 ;
			RECT	0.03 86.845 0.14 87.195 ;
		END

		ANTENNADIFFAREA 0.018 ;
		ANTENNAPARTIALMETALAREA 0.025 ;
	END Q[30]

	PIN Q[31]
		USE SIGNAL ;
		DIRECTION OUTPUT ;
		SHAPE ABUTMENT ;
		PORT
			LAYER	M2 ;
			RECT	0.03 89.685 0.14 90.035 ;
			LAYER	M3 ;
			RECT	0.03 89.685 0.14 90.035 ;
		END

		ANTENNADIFFAREA 0.018 ;
		ANTENNAPARTIALMETALAREA 0.025 ;
	END Q[31]

	PIN Q[32]
		USE SIGNAL ;
		DIRECTION OUTPUT ;
		SHAPE ABUTMENT ;
		PORT
			LAYER	M2 ;
			RECT	0.03 117.115 0.14 117.465 ;
			LAYER	M3 ;
			RECT	0.03 117.115 0.14 117.465 ;
		END

		ANTENNADIFFAREA 0.018 ;
		ANTENNAPARTIALMETALAREA 0.025 ;
	END Q[32]

	PIN Q[33]
		USE SIGNAL ;
		DIRECTION OUTPUT ;
		SHAPE ABUTMENT ;
		PORT
			LAYER	M2 ;
			RECT	0.03 119.955 0.14 120.305 ;
			LAYER	M3 ;
			RECT	0.03 119.955 0.14 120.305 ;
		END

		ANTENNADIFFAREA 0.018 ;
		ANTENNAPARTIALMETALAREA 0.025 ;
	END Q[33]

	PIN Q[34]
		USE SIGNAL ;
		DIRECTION OUTPUT ;
		SHAPE ABUTMENT ;
		PORT
			LAYER	M2 ;
			RECT	0.03 122.795 0.14 123.145 ;
			LAYER	M3 ;
			RECT	0.03 122.795 0.14 123.145 ;
		END

		ANTENNADIFFAREA 0.018 ;
		ANTENNAPARTIALMETALAREA 0.025 ;
	END Q[34]

	PIN Q[35]
		USE SIGNAL ;
		DIRECTION OUTPUT ;
		SHAPE ABUTMENT ;
		PORT
			LAYER	M2 ;
			RECT	0.03 125.635 0.14 125.985 ;
			LAYER	M3 ;
			RECT	0.03 125.635 0.14 125.985 ;
		END

		ANTENNADIFFAREA 0.018 ;
		ANTENNAPARTIALMETALAREA 0.025 ;
	END Q[35]

	PIN Q[36]
		USE SIGNAL ;
		DIRECTION OUTPUT ;
		SHAPE ABUTMENT ;
		PORT
			LAYER	M2 ;
			RECT	0.03 128.475 0.14 128.825 ;
			LAYER	M3 ;
			RECT	0.03 128.475 0.14 128.825 ;
		END

		ANTENNADIFFAREA 0.018 ;
		ANTENNAPARTIALMETALAREA 0.025 ;
	END Q[36]

	PIN Q[37]
		USE SIGNAL ;
		DIRECTION OUTPUT ;
		SHAPE ABUTMENT ;
		PORT
			LAYER	M2 ;
			RECT	0.03 131.315 0.14 131.665 ;
			LAYER	M3 ;
			RECT	0.03 131.315 0.14 131.665 ;
		END

		ANTENNADIFFAREA 0.018 ;
		ANTENNAPARTIALMETALAREA 0.025 ;
	END Q[37]

	PIN Q[38]
		USE SIGNAL ;
		DIRECTION OUTPUT ;
		SHAPE ABUTMENT ;
		PORT
			LAYER	M2 ;
			RECT	0.03 134.155 0.14 134.505 ;
			LAYER	M3 ;
			RECT	0.03 134.155 0.14 134.505 ;
		END

		ANTENNADIFFAREA 0.018 ;
		ANTENNAPARTIALMETALAREA 0.025 ;
	END Q[38]

	PIN Q[39]
		USE SIGNAL ;
		DIRECTION OUTPUT ;
		SHAPE ABUTMENT ;
		PORT
			LAYER	M2 ;
			RECT	0.03 136.995 0.14 137.345 ;
			LAYER	M3 ;
			RECT	0.03 136.995 0.14 137.345 ;
		END

		ANTENNADIFFAREA 0.018 ;
		ANTENNAPARTIALMETALAREA 0.025 ;
	END Q[39]

	PIN Q[3]
		USE SIGNAL ;
		DIRECTION OUTPUT ;
		SHAPE ABUTMENT ;
		PORT
			LAYER	M2 ;
			RECT	0.03 10.165 0.14 10.515 ;
			LAYER	M3 ;
			RECT	0.03 10.165 0.14 10.515 ;
		END

		ANTENNADIFFAREA 0.018 ;
		ANTENNAPARTIALMETALAREA 0.025 ;
	END Q[3]

	PIN Q[40]
		USE SIGNAL ;
		DIRECTION OUTPUT ;
		SHAPE ABUTMENT ;
		PORT
			LAYER	M2 ;
			RECT	0.03 139.835 0.14 140.185 ;
			LAYER	M3 ;
			RECT	0.03 139.835 0.14 140.185 ;
		END

		ANTENNADIFFAREA 0.018 ;
		ANTENNAPARTIALMETALAREA 0.025 ;
	END Q[40]

	PIN Q[41]
		USE SIGNAL ;
		DIRECTION OUTPUT ;
		SHAPE ABUTMENT ;
		PORT
			LAYER	M2 ;
			RECT	0.03 142.675 0.14 143.025 ;
			LAYER	M3 ;
			RECT	0.03 142.675 0.14 143.025 ;
		END

		ANTENNADIFFAREA 0.018 ;
		ANTENNAPARTIALMETALAREA 0.025 ;
	END Q[41]

	PIN Q[42]
		USE SIGNAL ;
		DIRECTION OUTPUT ;
		SHAPE ABUTMENT ;
		PORT
			LAYER	M2 ;
			RECT	0.03 145.515 0.14 145.865 ;
			LAYER	M3 ;
			RECT	0.03 145.515 0.14 145.865 ;
		END

		ANTENNADIFFAREA 0.018 ;
		ANTENNAPARTIALMETALAREA 0.025 ;
	END Q[42]

	PIN Q[43]
		USE SIGNAL ;
		DIRECTION OUTPUT ;
		SHAPE ABUTMENT ;
		PORT
			LAYER	M2 ;
			RECT	0.03 148.355 0.14 148.705 ;
			LAYER	M3 ;
			RECT	0.03 148.355 0.14 148.705 ;
		END

		ANTENNADIFFAREA 0.018 ;
		ANTENNAPARTIALMETALAREA 0.025 ;
	END Q[43]

	PIN Q[44]
		USE SIGNAL ;
		DIRECTION OUTPUT ;
		SHAPE ABUTMENT ;
		PORT
			LAYER	M2 ;
			RECT	0.03 151.195 0.14 151.545 ;
			LAYER	M3 ;
			RECT	0.03 151.195 0.14 151.545 ;
		END

		ANTENNADIFFAREA 0.018 ;
		ANTENNAPARTIALMETALAREA 0.025 ;
	END Q[44]

	PIN Q[45]
		USE SIGNAL ;
		DIRECTION OUTPUT ;
		SHAPE ABUTMENT ;
		PORT
			LAYER	M2 ;
			RECT	0.03 154.035 0.14 154.385 ;
			LAYER	M3 ;
			RECT	0.03 154.035 0.14 154.385 ;
		END

		ANTENNADIFFAREA 0.018 ;
		ANTENNAPARTIALMETALAREA 0.025 ;
	END Q[45]

	PIN Q[46]
		USE SIGNAL ;
		DIRECTION OUTPUT ;
		SHAPE ABUTMENT ;
		PORT
			LAYER	M2 ;
			RECT	0.03 156.875 0.14 157.225 ;
			LAYER	M3 ;
			RECT	0.03 156.875 0.14 157.225 ;
		END

		ANTENNADIFFAREA 0.018 ;
		ANTENNAPARTIALMETALAREA 0.025 ;
	END Q[46]

	PIN Q[47]
		USE SIGNAL ;
		DIRECTION OUTPUT ;
		SHAPE ABUTMENT ;
		PORT
			LAYER	M2 ;
			RECT	0.03 159.715 0.14 160.065 ;
			LAYER	M3 ;
			RECT	0.03 159.715 0.14 160.065 ;
		END

		ANTENNADIFFAREA 0.018 ;
		ANTENNAPARTIALMETALAREA 0.025 ;
	END Q[47]

	PIN Q[48]
		USE SIGNAL ;
		DIRECTION OUTPUT ;
		SHAPE ABUTMENT ;
		PORT
			LAYER	M2 ;
			RECT	0.03 162.555 0.14 162.905 ;
			LAYER	M3 ;
			RECT	0.03 162.555 0.14 162.905 ;
		END

		ANTENNADIFFAREA 0.018 ;
		ANTENNAPARTIALMETALAREA 0.025 ;
	END Q[48]

	PIN Q[49]
		USE SIGNAL ;
		DIRECTION OUTPUT ;
		SHAPE ABUTMENT ;
		PORT
			LAYER	M2 ;
			RECT	0.03 165.395 0.14 165.745 ;
			LAYER	M3 ;
			RECT	0.03 165.395 0.14 165.745 ;
		END

		ANTENNADIFFAREA 0.018 ;
		ANTENNAPARTIALMETALAREA 0.025 ;
	END Q[49]

	PIN Q[4]
		USE SIGNAL ;
		DIRECTION OUTPUT ;
		SHAPE ABUTMENT ;
		PORT
			LAYER	M2 ;
			RECT	0.03 13.005 0.14 13.355 ;
			LAYER	M3 ;
			RECT	0.03 13.005 0.14 13.355 ;
		END

		ANTENNADIFFAREA 0.018 ;
		ANTENNAPARTIALMETALAREA 0.025 ;
	END Q[4]

	PIN Q[50]
		USE SIGNAL ;
		DIRECTION OUTPUT ;
		SHAPE ABUTMENT ;
		PORT
			LAYER	M2 ;
			RECT	0.03 168.235 0.14 168.585 ;
			LAYER	M3 ;
			RECT	0.03 168.235 0.14 168.585 ;
		END

		ANTENNADIFFAREA 0.018 ;
		ANTENNAPARTIALMETALAREA 0.025 ;
	END Q[50]

	PIN Q[51]
		USE SIGNAL ;
		DIRECTION OUTPUT ;
		SHAPE ABUTMENT ;
		PORT
			LAYER	M2 ;
			RECT	0.03 171.075 0.14 171.425 ;
			LAYER	M3 ;
			RECT	0.03 171.075 0.14 171.425 ;
		END

		ANTENNADIFFAREA 0.018 ;
		ANTENNAPARTIALMETALAREA 0.025 ;
	END Q[51]

	PIN Q[52]
		USE SIGNAL ;
		DIRECTION OUTPUT ;
		SHAPE ABUTMENT ;
		PORT
			LAYER	M2 ;
			RECT	0.03 173.915 0.14 174.265 ;
			LAYER	M3 ;
			RECT	0.03 173.915 0.14 174.265 ;
		END

		ANTENNADIFFAREA 0.018 ;
		ANTENNAPARTIALMETALAREA 0.025 ;
	END Q[52]

	PIN Q[53]
		USE SIGNAL ;
		DIRECTION OUTPUT ;
		SHAPE ABUTMENT ;
		PORT
			LAYER	M2 ;
			RECT	0.03 176.755 0.14 177.105 ;
			LAYER	M3 ;
			RECT	0.03 176.755 0.14 177.105 ;
		END

		ANTENNADIFFAREA 0.018 ;
		ANTENNAPARTIALMETALAREA 0.025 ;
	END Q[53]

	PIN Q[54]
		USE SIGNAL ;
		DIRECTION OUTPUT ;
		SHAPE ABUTMENT ;
		PORT
			LAYER	M2 ;
			RECT	0.03 179.595 0.14 179.945 ;
			LAYER	M3 ;
			RECT	0.03 179.595 0.14 179.945 ;
		END

		ANTENNADIFFAREA 0.018 ;
		ANTENNAPARTIALMETALAREA 0.025 ;
	END Q[54]

	PIN Q[55]
		USE SIGNAL ;
		DIRECTION OUTPUT ;
		SHAPE ABUTMENT ;
		PORT
			LAYER	M2 ;
			RECT	0.03 182.435 0.14 182.785 ;
			LAYER	M3 ;
			RECT	0.03 182.435 0.14 182.785 ;
		END

		ANTENNADIFFAREA 0.018 ;
		ANTENNAPARTIALMETALAREA 0.025 ;
	END Q[55]

	PIN Q[56]
		USE SIGNAL ;
		DIRECTION OUTPUT ;
		SHAPE ABUTMENT ;
		PORT
			LAYER	M2 ;
			RECT	0.03 185.275 0.14 185.625 ;
			LAYER	M3 ;
			RECT	0.03 185.275 0.14 185.625 ;
		END

		ANTENNADIFFAREA 0.018 ;
		ANTENNAPARTIALMETALAREA 0.025 ;
	END Q[56]

	PIN Q[57]
		USE SIGNAL ;
		DIRECTION OUTPUT ;
		SHAPE ABUTMENT ;
		PORT
			LAYER	M2 ;
			RECT	0.03 188.115 0.14 188.465 ;
			LAYER	M3 ;
			RECT	0.03 188.115 0.14 188.465 ;
		END

		ANTENNADIFFAREA 0.018 ;
		ANTENNAPARTIALMETALAREA 0.025 ;
	END Q[57]

	PIN Q[58]
		USE SIGNAL ;
		DIRECTION OUTPUT ;
		SHAPE ABUTMENT ;
		PORT
			LAYER	M2 ;
			RECT	0.03 190.955 0.14 191.305 ;
			LAYER	M3 ;
			RECT	0.03 190.955 0.14 191.305 ;
		END

		ANTENNADIFFAREA 0.018 ;
		ANTENNAPARTIALMETALAREA 0.025 ;
	END Q[58]

	PIN Q[59]
		USE SIGNAL ;
		DIRECTION OUTPUT ;
		SHAPE ABUTMENT ;
		PORT
			LAYER	M2 ;
			RECT	0.03 193.795 0.14 194.145 ;
			LAYER	M3 ;
			RECT	0.03 193.795 0.14 194.145 ;
		END

		ANTENNADIFFAREA 0.018 ;
		ANTENNAPARTIALMETALAREA 0.025 ;
	END Q[59]

	PIN Q[5]
		USE SIGNAL ;
		DIRECTION OUTPUT ;
		SHAPE ABUTMENT ;
		PORT
			LAYER	M2 ;
			RECT	0.03 15.845 0.14 16.195 ;
			LAYER	M3 ;
			RECT	0.03 15.845 0.14 16.195 ;
		END

		ANTENNADIFFAREA 0.018 ;
		ANTENNAPARTIALMETALAREA 0.025 ;
	END Q[5]

	PIN Q[60]
		USE SIGNAL ;
		DIRECTION OUTPUT ;
		SHAPE ABUTMENT ;
		PORT
			LAYER	M2 ;
			RECT	0.03 196.635 0.14 196.985 ;
			LAYER	M3 ;
			RECT	0.03 196.635 0.14 196.985 ;
		END

		ANTENNADIFFAREA 0.018 ;
		ANTENNAPARTIALMETALAREA 0.025 ;
	END Q[60]

	PIN Q[61]
		USE SIGNAL ;
		DIRECTION OUTPUT ;
		SHAPE ABUTMENT ;
		PORT
			LAYER	M2 ;
			RECT	0.03 199.475 0.14 199.825 ;
			LAYER	M3 ;
			RECT	0.03 199.475 0.14 199.825 ;
		END

		ANTENNADIFFAREA 0.018 ;
		ANTENNAPARTIALMETALAREA 0.025 ;
	END Q[61]

	PIN Q[62]
		USE SIGNAL ;
		DIRECTION OUTPUT ;
		SHAPE ABUTMENT ;
		PORT
			LAYER	M2 ;
			RECT	0.03 202.315 0.14 202.665 ;
			LAYER	M3 ;
			RECT	0.03 202.315 0.14 202.665 ;
		END

		ANTENNADIFFAREA 0.018 ;
		ANTENNAPARTIALMETALAREA 0.025 ;
	END Q[62]

	PIN Q[63]
		USE SIGNAL ;
		DIRECTION OUTPUT ;
		SHAPE ABUTMENT ;
		PORT
			LAYER	M2 ;
			RECT	0.03 205.155 0.14 205.505 ;
			LAYER	M3 ;
			RECT	0.03 205.155 0.14 205.505 ;
		END

		ANTENNADIFFAREA 0.018 ;
		ANTENNAPARTIALMETALAREA 0.025 ;
	END Q[63]

	PIN Q[6]
		USE SIGNAL ;
		DIRECTION OUTPUT ;
		SHAPE ABUTMENT ;
		PORT
			LAYER	M2 ;
			RECT	0.03 18.685 0.14 19.035 ;
			LAYER	M3 ;
			RECT	0.03 18.685 0.14 19.035 ;
		END

		ANTENNADIFFAREA 0.018 ;
		ANTENNAPARTIALMETALAREA 0.025 ;
	END Q[6]

	PIN Q[7]
		USE SIGNAL ;
		DIRECTION OUTPUT ;
		SHAPE ABUTMENT ;
		PORT
			LAYER	M2 ;
			RECT	0.03 21.525 0.14 21.875 ;
			LAYER	M3 ;
			RECT	0.03 21.525 0.14 21.875 ;
		END

		ANTENNADIFFAREA 0.018 ;
		ANTENNAPARTIALMETALAREA 0.025 ;
	END Q[7]

	PIN Q[8]
		USE SIGNAL ;
		DIRECTION OUTPUT ;
		SHAPE ABUTMENT ;
		PORT
			LAYER	M2 ;
			RECT	0.03 24.365 0.14 24.715 ;
			LAYER	M3 ;
			RECT	0.03 24.365 0.14 24.715 ;
		END

		ANTENNADIFFAREA 0.018 ;
		ANTENNAPARTIALMETALAREA 0.025 ;
	END Q[8]

	PIN Q[9]
		USE SIGNAL ;
		DIRECTION OUTPUT ;
		SHAPE ABUTMENT ;
		PORT
			LAYER	M2 ;
			RECT	0.03 27.205 0.14 27.555 ;
			LAYER	M3 ;
			RECT	0.03 27.205 0.14 27.555 ;
		END

		ANTENNADIFFAREA 0.018 ;
		ANTENNAPARTIALMETALAREA 0.025 ;
	END Q[9]

	PIN RAWL
		USE SIGNAL ;
		DIRECTION INPUT ;
		SHAPE ABUTMENT ;
		PORT
			LAYER	M2 ;
			RECT	0.03 114.315 0.14 114.665 ;
			LAYER	M3 ;
			RECT	0.03 114.315 0.14 114.665 ;
		END

		ANTENNAGATEAREA 0.014 ;
		ANTENNADIFFAREA 0.018 ;
		ANTENNAPARTIALMETALAREA 0.025 ;
	END RAWL

	PIN RAWLM[0]
		USE SIGNAL ;
		DIRECTION INPUT ;
		SHAPE ABUTMENT ;
		PORT
			LAYER	M2 ;
			RECT	0.03 92.41 0.14 92.76 ;
			LAYER	M3 ;
			RECT	0.03 92.41 0.14 92.76 ;
		END

		ANTENNAGATEAREA 0.014 ;
		ANTENNADIFFAREA 0.018 ;
		ANTENNAPARTIALMETALAREA 0.025 ;
	END RAWLM[0]

	PIN RAWLM[1]
		USE SIGNAL ;
		DIRECTION INPUT ;
		SHAPE ABUTMENT ;
		PORT
			LAYER	M2 ;
			RECT	0.03 114.715 0.14 115.065 ;
			LAYER	M3 ;
			RECT	0.03 114.715 0.14 115.065 ;
		END

		ANTENNAGATEAREA 0.014 ;
		ANTENNADIFFAREA 0.018 ;
		ANTENNAPARTIALMETALAREA 0.025 ;
	END RAWLM[1]

	PIN RET1N
		USE SIGNAL ;
		DIRECTION INPUT ;
		SHAPE ABUTMENT ;
		PORT
			LAYER	M2 ;
			RECT	0.03 94.215 0.15 94.365 ;
			LAYER	M3 ;
			RECT	0.03 94.215 0.15 94.365 ;
		END

		ANTENNAGATEAREA 0.014 ;
		ANTENNADIFFAREA 0.018 ;
		ANTENNAPARTIALMETALAREA 0.025 ;
	END RET1N

	PIN STOV
		USE SIGNAL ;
		DIRECTION INPUT ;
		SHAPE ABUTMENT ;
		PORT
			LAYER	M2 ;
			RECT	0.03 105.315 0.15 105.465 ;
			LAYER	M3 ;
			RECT	0.03 105.315 0.15 105.465 ;
		END

		ANTENNAGATEAREA 0.014 ;
		ANTENNADIFFAREA 0.018 ;
		ANTENNAPARTIALMETALAREA 0.025 ;
	END STOV

	PIN VDDCE
		USE POWER ;
		DIRECTION INOUT ;
		PORT
			LAYER	M4 ;
			RECT	0.39 94.83 121.075 94.98 ;
		END

		PORT
			LAYER	M4 ;
			RECT	0.39 95.66 121.075 95.81 ;
		END

		PORT
			LAYER	M4 ;
			RECT	0.39 103.46 121.075 103.61 ;
		END

		PORT
			LAYER	M4 ;
			RECT	0.39 111.92 121.075 112.07 ;
		END

		PORT
			LAYER	M4 ;
			RECT	0.39 112.75 121.075 112.9 ;
		END

		PORT
			LAYER	M4 ;
			RECT	0.39 203.76 121.075 203.91 ;
		END

		PORT
			LAYER	M4 ;
			RECT	0.39 198.08 121.075 198.23 ;
		END

		PORT
			LAYER	M4 ;
			RECT	0.39 91.28 121.075 91.43 ;
		END

		PORT
			LAYER	M4 ;
			RECT	0.39 88.44 121.075 88.59 ;
		END

		PORT
			LAYER	M4 ;
			RECT	0.39 195.24 121.075 195.39 ;
		END

		PORT
			LAYER	M4 ;
			RECT	0.39 85.6 121.075 85.75 ;
		END

		PORT
			LAYER	M4 ;
			RECT	0.39 82.76 121.075 82.91 ;
		END

		PORT
			LAYER	M4 ;
			RECT	0.39 79.92 121.075 80.07 ;
		END

		PORT
			LAYER	M4 ;
			RECT	0.39 77.08 121.075 77.23 ;
		END

		PORT
			LAYER	M4 ;
			RECT	0.39 74.24 121.075 74.39 ;
		END

		PORT
			LAYER	M4 ;
			RECT	0.39 71.4 121.075 71.55 ;
		END

		PORT
			LAYER	M4 ;
			RECT	0.39 68.56 121.075 68.71 ;
		END

		PORT
			LAYER	M4 ;
			RECT	0.39 65.72 121.075 65.87 ;
		END

		PORT
			LAYER	M4 ;
			RECT	0.39 62.88 121.075 63.03 ;
		END

		PORT
			LAYER	M4 ;
			RECT	0.39 60.04 121.075 60.19 ;
		END

		PORT
			LAYER	M4 ;
			RECT	0.39 192.4 121.075 192.55 ;
		END

		PORT
			LAYER	M4 ;
			RECT	0.39 57.2 121.075 57.35 ;
		END

		PORT
			LAYER	M4 ;
			RECT	0.39 54.36 121.075 54.51 ;
		END

		PORT
			LAYER	M4 ;
			RECT	0.39 51.52 121.075 51.67 ;
		END

		PORT
			LAYER	M4 ;
			RECT	0.39 48.68 121.075 48.83 ;
		END

		PORT
			LAYER	M4 ;
			RECT	0.39 45.84 121.075 45.99 ;
		END

		PORT
			LAYER	M4 ;
			RECT	0.39 43 121.075 43.15 ;
		END

		PORT
			LAYER	M4 ;
			RECT	0.39 40.16 121.075 40.31 ;
		END

		PORT
			LAYER	M4 ;
			RECT	0.39 37.32 121.075 37.47 ;
		END

		PORT
			LAYER	M4 ;
			RECT	0.39 34.48 121.075 34.63 ;
		END

		PORT
			LAYER	M4 ;
			RECT	0.39 31.64 121.075 31.79 ;
		END

		PORT
			LAYER	M4 ;
			RECT	0.39 189.56 121.075 189.71 ;
		END

		PORT
			LAYER	M4 ;
			RECT	0.39 28.8 121.075 28.95 ;
		END

		PORT
			LAYER	M4 ;
			RECT	0.39 25.96 121.075 26.11 ;
		END

		PORT
			LAYER	M4 ;
			RECT	0.39 23.12 121.075 23.27 ;
		END

		PORT
			LAYER	M4 ;
			RECT	0.39 20.28 121.075 20.43 ;
		END

		PORT
			LAYER	M4 ;
			RECT	0.39 17.44 121.075 17.59 ;
		END

		PORT
			LAYER	M4 ;
			RECT	0.39 14.6 121.075 14.75 ;
		END

		PORT
			LAYER	M4 ;
			RECT	0.39 11.76 121.075 11.91 ;
		END

		PORT
			LAYER	M4 ;
			RECT	0.39 8.92 121.075 9.07 ;
		END

		PORT
			LAYER	M4 ;
			RECT	0.39 6.08 121.075 6.23 ;
		END

		PORT
			LAYER	M4 ;
			RECT	0.39 3.24 121.075 3.39 ;
		END

		PORT
			LAYER	M4 ;
			RECT	0.39 186.72 121.075 186.87 ;
		END

		PORT
			LAYER	M4 ;
			RECT	0.39 183.88 121.075 184.03 ;
		END

		PORT
			LAYER	M4 ;
			RECT	0.39 181.04 121.075 181.19 ;
		END

		PORT
			LAYER	M4 ;
			RECT	0.39 178.2 121.075 178.35 ;
		END

		PORT
			LAYER	M4 ;
			RECT	0.39 175.36 121.075 175.51 ;
		END

		PORT
			LAYER	M4 ;
			RECT	0.39 172.52 121.075 172.67 ;
		END

		PORT
			LAYER	M4 ;
			RECT	0.39 169.68 121.075 169.83 ;
		END

		PORT
			LAYER	M4 ;
			RECT	0.39 166.84 121.075 166.99 ;
		END

		PORT
			LAYER	M4 ;
			RECT	0.39 164 121.075 164.15 ;
		END

		PORT
			LAYER	M4 ;
			RECT	0.39 161.16 121.075 161.31 ;
		END

		PORT
			LAYER	M4 ;
			RECT	0.39 158.32 121.075 158.47 ;
		END

		PORT
			LAYER	M4 ;
			RECT	0.39 155.48 121.075 155.63 ;
		END

		PORT
			LAYER	M4 ;
			RECT	0.39 152.64 121.075 152.79 ;
		END

		PORT
			LAYER	M4 ;
			RECT	0.39 149.8 121.075 149.95 ;
		END

		PORT
			LAYER	M4 ;
			RECT	0.39 146.96 121.075 147.11 ;
		END

		PORT
			LAYER	M4 ;
			RECT	0.39 144.12 121.075 144.27 ;
		END

		PORT
			LAYER	M4 ;
			RECT	0.39 141.28 121.075 141.43 ;
		END

		PORT
			LAYER	M4 ;
			RECT	0.39 138.44 121.075 138.59 ;
		END

		PORT
			LAYER	M4 ;
			RECT	0.39 135.6 121.075 135.75 ;
		END

		PORT
			LAYER	M4 ;
			RECT	0.39 200.92 121.075 201.07 ;
		END

		PORT
			LAYER	M4 ;
			RECT	0.39 132.76 121.075 132.91 ;
		END

		PORT
			LAYER	M4 ;
			RECT	0.39 129.92 121.075 130.07 ;
		END

		PORT
			LAYER	M4 ;
			RECT	0.39 127.08 121.075 127.23 ;
		END

		PORT
			LAYER	M4 ;
			RECT	0.39 124.24 121.075 124.39 ;
		END

		PORT
			LAYER	M4 ;
			RECT	0.39 121.4 121.075 121.55 ;
		END

		PORT
			LAYER	M4 ;
			RECT	0.39 118.56 121.075 118.71 ;
		END

		PORT
			LAYER	M4 ;
			RECT	0.39 115.72 121.075 115.87 ;
		END

		PORT
			LAYER	M4 ;
			RECT	0.39 206.91 121.075 207.06 ;
		END

		PORT
			LAYER	M4 ;
			RECT	0.39 0.09 121.075 0.24 ;
		END

		PORT
			LAYER	M4 ;
			RECT	0.39 92.37 121.075 92.52 ;
		END

		PORT
			LAYER	M4 ;
			RECT	0.39 114.9 121.075 115.05 ;
		END

	END VDDCE

	PIN VDDPE
		USE POWER ;
		DIRECTION INOUT ;
		PORT
			LAYER	M4 ;
			RECT	0.39 94.6 121.075 94.75 ;
		END

		PORT
			LAYER	M4 ;
			RECT	0.39 95.89 121.075 96.04 ;
		END

		PORT
			LAYER	M4 ;
			RECT	0.39 97.25 121.075 97.4 ;
		END

		PORT
			LAYER	M4 ;
			RECT	0.39 98.84 121.075 98.99 ;
		END

		PORT
			LAYER	M4 ;
			RECT	0.39 100.51 121.075 100.66 ;
		END

		PORT
			LAYER	M4 ;
			RECT	0.39 102.1 121.075 102.25 ;
		END

		PORT
			LAYER	M4 ;
			RECT	0.39 103.92 121.075 104.07 ;
		END

		PORT
			LAYER	M4 ;
			RECT	0.39 105.51 121.075 105.66 ;
		END

		PORT
			LAYER	M4 ;
			RECT	0.39 107.1 121.075 107.25 ;
		END

		PORT
			LAYER	M4 ;
			RECT	0.39 108.74 121.075 108.89 ;
		END

		PORT
			LAYER	M4 ;
			RECT	0.39 110.33 121.075 110.48 ;
		END

		PORT
			LAYER	M4 ;
			RECT	0.39 111.69 121.075 111.84 ;
		END

		PORT
			LAYER	M4 ;
			RECT	0.39 112.98 121.075 113.13 ;
		END

		PORT
			LAYER	M4 ;
			RECT	0.39 204.575 121.075 204.725 ;
		END

		PORT
			LAYER	M4 ;
			RECT	0.39 198.895 121.075 199.045 ;
		END

		PORT
			LAYER	M4 ;
			RECT	0.39 196.055 121.075 196.205 ;
		END

		PORT
			LAYER	M4 ;
			RECT	0.39 90.465 121.075 90.615 ;
		END

		PORT
			LAYER	M4 ;
			RECT	0.39 87.625 121.075 87.775 ;
		END

		PORT
			LAYER	M4 ;
			RECT	0.39 84.785 121.075 84.935 ;
		END

		PORT
			LAYER	M4 ;
			RECT	0.39 81.945 121.075 82.095 ;
		END

		PORT
			LAYER	M4 ;
			RECT	0.39 79.105 121.075 79.255 ;
		END

		PORT
			LAYER	M4 ;
			RECT	0.39 76.265 121.075 76.415 ;
		END

		PORT
			LAYER	M4 ;
			RECT	0.39 73.425 121.075 73.575 ;
		END

		PORT
			LAYER	M4 ;
			RECT	0.39 70.585 121.075 70.735 ;
		END

		PORT
			LAYER	M4 ;
			RECT	0.39 193.215 121.075 193.365 ;
		END

		PORT
			LAYER	M4 ;
			RECT	0.39 67.745 121.075 67.895 ;
		END

		PORT
			LAYER	M4 ;
			RECT	0.39 64.905 121.075 65.055 ;
		END

		PORT
			LAYER	M4 ;
			RECT	0.39 62.065 121.075 62.215 ;
		END

		PORT
			LAYER	M4 ;
			RECT	0.39 59.225 121.075 59.375 ;
		END

		PORT
			LAYER	M4 ;
			RECT	0.39 56.385 121.075 56.535 ;
		END

		PORT
			LAYER	M4 ;
			RECT	0.39 53.545 121.075 53.695 ;
		END

		PORT
			LAYER	M4 ;
			RECT	0.39 50.705 121.075 50.855 ;
		END

		PORT
			LAYER	M4 ;
			RECT	0.39 47.865 121.075 48.015 ;
		END

		PORT
			LAYER	M4 ;
			RECT	0.39 45.025 121.075 45.175 ;
		END

		PORT
			LAYER	M4 ;
			RECT	0.39 42.185 121.075 42.335 ;
		END

		PORT
			LAYER	M4 ;
			RECT	0.39 190.375 121.075 190.525 ;
		END

		PORT
			LAYER	M4 ;
			RECT	0.39 39.345 121.075 39.495 ;
		END

		PORT
			LAYER	M4 ;
			RECT	0.39 36.505 121.075 36.655 ;
		END

		PORT
			LAYER	M4 ;
			RECT	0.39 33.665 121.075 33.815 ;
		END

		PORT
			LAYER	M4 ;
			RECT	0.39 30.825 121.075 30.975 ;
		END

		PORT
			LAYER	M4 ;
			RECT	0.39 27.985 121.075 28.135 ;
		END

		PORT
			LAYER	M4 ;
			RECT	0.39 25.145 121.075 25.295 ;
		END

		PORT
			LAYER	M4 ;
			RECT	0.39 22.305 121.075 22.455 ;
		END

		PORT
			LAYER	M4 ;
			RECT	0.39 19.465 121.075 19.615 ;
		END

		PORT
			LAYER	M4 ;
			RECT	0.39 16.625 121.075 16.775 ;
		END

		PORT
			LAYER	M4 ;
			RECT	0.39 13.785 121.075 13.935 ;
		END

		PORT
			LAYER	M4 ;
			RECT	0.39 187.535 121.075 187.685 ;
		END

		PORT
			LAYER	M4 ;
			RECT	0.39 10.945 121.075 11.095 ;
		END

		PORT
			LAYER	M4 ;
			RECT	0.39 8.105 121.075 8.255 ;
		END

		PORT
			LAYER	M4 ;
			RECT	0.39 5.265 121.075 5.415 ;
		END

		PORT
			LAYER	M4 ;
			RECT	0.39 2.425 121.075 2.575 ;
		END

		PORT
			LAYER	M4 ;
			RECT	0.39 184.695 121.075 184.845 ;
		END

		PORT
			LAYER	M4 ;
			RECT	0.39 181.855 121.075 182.005 ;
		END

		PORT
			LAYER	M4 ;
			RECT	0.39 179.015 121.075 179.165 ;
		END

		PORT
			LAYER	M4 ;
			RECT	0.39 176.175 121.075 176.325 ;
		END

		PORT
			LAYER	M4 ;
			RECT	0.39 173.335 121.075 173.485 ;
		END

		PORT
			LAYER	M4 ;
			RECT	0.39 170.495 121.075 170.645 ;
		END

		PORT
			LAYER	M4 ;
			RECT	0.39 167.655 121.075 167.805 ;
		END

		PORT
			LAYER	M4 ;
			RECT	0.39 164.815 121.075 164.965 ;
		END

		PORT
			LAYER	M4 ;
			RECT	0.39 161.975 121.075 162.125 ;
		END

		PORT
			LAYER	M4 ;
			RECT	0.39 159.135 121.075 159.285 ;
		END

		PORT
			LAYER	M4 ;
			RECT	0.39 156.295 121.075 156.445 ;
		END

		PORT
			LAYER	M4 ;
			RECT	0.39 153.455 121.075 153.605 ;
		END

		PORT
			LAYER	M4 ;
			RECT	0.39 150.615 121.075 150.765 ;
		END

		PORT
			LAYER	M4 ;
			RECT	0.39 147.775 121.075 147.925 ;
		END

		PORT
			LAYER	M4 ;
			RECT	0.39 144.935 121.075 145.085 ;
		END

		PORT
			LAYER	M4 ;
			RECT	0.39 201.735 121.075 201.885 ;
		END

		PORT
			LAYER	M4 ;
			RECT	0.39 142.095 121.075 142.245 ;
		END

		PORT
			LAYER	M4 ;
			RECT	0.39 139.255 121.075 139.405 ;
		END

		PORT
			LAYER	M4 ;
			RECT	0.39 136.415 121.075 136.565 ;
		END

		PORT
			LAYER	M4 ;
			RECT	0.39 133.575 121.075 133.725 ;
		END

		PORT
			LAYER	M4 ;
			RECT	0.39 130.735 121.075 130.885 ;
		END

		PORT
			LAYER	M4 ;
			RECT	0.39 127.895 121.075 128.045 ;
		END

		PORT
			LAYER	M4 ;
			RECT	0.39 125.055 121.075 125.205 ;
		END

		PORT
			LAYER	M4 ;
			RECT	0.39 122.215 121.075 122.365 ;
		END

		PORT
			LAYER	M4 ;
			RECT	0.39 119.375 121.075 119.525 ;
		END

		PORT
			LAYER	M4 ;
			RECT	0.39 116.535 121.075 116.685 ;
		END

		PORT
			LAYER	M4 ;
			RECT	0.39 91.91 121.075 92.06 ;
		END

		PORT
			LAYER	M4 ;
			RECT	0.39 206.35 121.075 206.5 ;
		END

		PORT
			LAYER	M4 ;
			RECT	0.39 0.65 121.075 0.8 ;
		END

		PORT
			LAYER	M4 ;
			RECT	0.39 101.12 121.075 101.19 ;
		END

		PORT
			LAYER	M4 ;
			RECT	0.39 109.95 121.075 110.02 ;
		END

	END VDDPE

	PIN VSSE
		USE GROUND ;
		DIRECTION INOUT ;
		PORT
			LAYER	M4 ;
			RECT	0.39 206.6 121.075 206.81 ;
		END

		PORT
			LAYER	M4 ;
			RECT	0.39 0.34 121.075 0.55 ;
		END

		PORT
			LAYER	M4 ;
			RECT	0.39 92.14 121.075 92.29 ;
		END

		PORT
			LAYER	M4 ;
			RECT	0.39 115.15 121.075 115.3 ;
		END

		PORT
			LAYER	M4 ;
			RECT	0.39 92.645 121.075 92.805 ;
		END

		PORT
			LAYER	M4 ;
			RECT	0.39 94.14 121.075 94.29 ;
		END

		PORT
			LAYER	M4 ;
			RECT	0.39 97.02 121.075 97.17 ;
		END

		PORT
			LAYER	M4 ;
			RECT	0.39 98.61 121.075 98.76 ;
		END

		PORT
			LAYER	M4 ;
			RECT	0.39 100.28 121.075 100.43 ;
		END

		PORT
			LAYER	M4 ;
			RECT	0.39 101.87 121.075 102.02 ;
		END

		PORT
			LAYER	M4 ;
			RECT	0.39 103.69 121.075 103.84 ;
		END

		PORT
			LAYER	M4 ;
			RECT	0.39 105.28 121.075 105.43 ;
		END

		PORT
			LAYER	M4 ;
			RECT	0.39 106.87 121.075 107.02 ;
		END

		PORT
			LAYER	M4 ;
			RECT	0.39 108.51 121.075 108.66 ;
		END

		PORT
			LAYER	M4 ;
			RECT	0.39 110.1 121.075 110.25 ;
		END

		PORT
			LAYER	M4 ;
			RECT	0.39 205.85 121.075 206 ;
		END

		PORT
			LAYER	M4 ;
			RECT	0.39 113.44 121.075 113.59 ;
		END

		PORT
			LAYER	M4 ;
			RECT	0.39 197.33 121.075 197.48 ;
		END

		PORT
			LAYER	M4 ;
			RECT	0.39 89.19 121.075 89.34 ;
		END

		PORT
			LAYER	M4 ;
			RECT	0.39 86.35 121.075 86.5 ;
		END

		PORT
			LAYER	M4 ;
			RECT	0.39 83.51 121.075 83.66 ;
		END

		PORT
			LAYER	M4 ;
			RECT	0.39 80.67 121.075 80.82 ;
		END

		PORT
			LAYER	M4 ;
			RECT	0.39 194.49 121.075 194.64 ;
		END

		PORT
			LAYER	M4 ;
			RECT	0.39 77.83 121.075 77.98 ;
		END

		PORT
			LAYER	M4 ;
			RECT	0.39 74.99 121.075 75.14 ;
		END

		PORT
			LAYER	M4 ;
			RECT	0.39 72.15 121.075 72.3 ;
		END

		PORT
			LAYER	M4 ;
			RECT	0.39 69.31 121.075 69.46 ;
		END

		PORT
			LAYER	M4 ;
			RECT	0.39 66.47 121.075 66.62 ;
		END

		PORT
			LAYER	M4 ;
			RECT	0.39 63.63 121.075 63.78 ;
		END

		PORT
			LAYER	M4 ;
			RECT	0.39 60.79 121.075 60.94 ;
		END

		PORT
			LAYER	M4 ;
			RECT	0.39 57.95 121.075 58.1 ;
		END

		PORT
			LAYER	M4 ;
			RECT	0.39 55.11 121.075 55.26 ;
		END

		PORT
			LAYER	M4 ;
			RECT	0.39 52.27 121.075 52.42 ;
		END

		PORT
			LAYER	M4 ;
			RECT	0.39 191.65 121.075 191.8 ;
		END

		PORT
			LAYER	M4 ;
			RECT	0.39 49.43 121.075 49.58 ;
		END

		PORT
			LAYER	M4 ;
			RECT	0.39 46.59 121.075 46.74 ;
		END

		PORT
			LAYER	M4 ;
			RECT	0.39 43.75 121.075 43.9 ;
		END

		PORT
			LAYER	M4 ;
			RECT	0.39 40.91 121.075 41.06 ;
		END

		PORT
			LAYER	M4 ;
			RECT	0.39 38.07 121.075 38.22 ;
		END

		PORT
			LAYER	M4 ;
			RECT	0.39 35.23 121.075 35.38 ;
		END

		PORT
			LAYER	M4 ;
			RECT	0.39 32.39 121.075 32.54 ;
		END

		PORT
			LAYER	M4 ;
			RECT	0.39 29.55 121.075 29.7 ;
		END

		PORT
			LAYER	M4 ;
			RECT	0.39 26.71 121.075 26.86 ;
		END

		PORT
			LAYER	M4 ;
			RECT	0.39 23.87 121.075 24.02 ;
		END

		PORT
			LAYER	M4 ;
			RECT	0.39 188.81 121.075 188.96 ;
		END

		PORT
			LAYER	M4 ;
			RECT	0.39 21.03 121.075 21.18 ;
		END

		PORT
			LAYER	M4 ;
			RECT	0.39 18.19 121.075 18.34 ;
		END

		PORT
			LAYER	M4 ;
			RECT	0.39 15.35 121.075 15.5 ;
		END

		PORT
			LAYER	M4 ;
			RECT	0.39 12.51 121.075 12.66 ;
		END

		PORT
			LAYER	M4 ;
			RECT	0.39 9.67 121.075 9.82 ;
		END

		PORT
			LAYER	M4 ;
			RECT	0.39 6.83 121.075 6.98 ;
		END

		PORT
			LAYER	M4 ;
			RECT	0.39 3.99 121.075 4.14 ;
		END

		PORT
			LAYER	M4 ;
			RECT	0.39 1.15 121.075 1.3 ;
		END

		PORT
			LAYER	M4 ;
			RECT	0.39 185.97 121.075 186.12 ;
		END

		PORT
			LAYER	M4 ;
			RECT	0.39 183.13 121.075 183.28 ;
		END

		PORT
			LAYER	M4 ;
			RECT	0.39 180.29 121.075 180.44 ;
		END

		PORT
			LAYER	M4 ;
			RECT	0.39 177.45 121.075 177.6 ;
		END

		PORT
			LAYER	M4 ;
			RECT	0.39 174.61 121.075 174.76 ;
		END

		PORT
			LAYER	M4 ;
			RECT	0.39 171.77 121.075 171.92 ;
		END

		PORT
			LAYER	M4 ;
			RECT	0.39 168.93 121.075 169.08 ;
		END

		PORT
			LAYER	M4 ;
			RECT	0.39 166.09 121.075 166.24 ;
		END

		PORT
			LAYER	M4 ;
			RECT	0.39 163.25 121.075 163.4 ;
		END

		PORT
			LAYER	M4 ;
			RECT	0.39 160.41 121.075 160.56 ;
		END

		PORT
			LAYER	M4 ;
			RECT	0.39 157.57 121.075 157.72 ;
		END

		PORT
			LAYER	M4 ;
			RECT	0.39 154.73 121.075 154.88 ;
		END

		PORT
			LAYER	M4 ;
			RECT	0.39 203.01 121.075 203.16 ;
		END

		PORT
			LAYER	M4 ;
			RECT	0.39 151.89 121.075 152.04 ;
		END

		PORT
			LAYER	M4 ;
			RECT	0.39 149.05 121.075 149.2 ;
		END

		PORT
			LAYER	M4 ;
			RECT	0.39 146.21 121.075 146.36 ;
		END

		PORT
			LAYER	M4 ;
			RECT	0.39 143.37 121.075 143.52 ;
		END

		PORT
			LAYER	M4 ;
			RECT	0.39 140.53 121.075 140.68 ;
		END

		PORT
			LAYER	M4 ;
			RECT	0.39 137.69 121.075 137.84 ;
		END

		PORT
			LAYER	M4 ;
			RECT	0.39 134.85 121.075 135 ;
		END

		PORT
			LAYER	M4 ;
			RECT	0.39 132.01 121.075 132.16 ;
		END

		PORT
			LAYER	M4 ;
			RECT	0.39 129.17 121.075 129.32 ;
		END

		PORT
			LAYER	M4 ;
			RECT	0.39 126.33 121.075 126.48 ;
		END

		PORT
			LAYER	M4 ;
			RECT	0.39 200.17 121.075 200.32 ;
		END

		PORT
			LAYER	M4 ;
			RECT	0.39 123.49 121.075 123.64 ;
		END

		PORT
			LAYER	M4 ;
			RECT	0.39 120.65 121.075 120.8 ;
		END

		PORT
			LAYER	M4 ;
			RECT	0.39 117.81 121.075 117.96 ;
		END

	END VSSE

	PIN WABL
		USE SIGNAL ;
		DIRECTION INPUT ;
		SHAPE ABUTMENT ;
		PORT
			LAYER	M2 ;
			RECT	0.03 94.015 0.15 94.165 ;
			LAYER	M3 ;
			RECT	0.03 94.015 0.15 94.165 ;
		END

		ANTENNAGATEAREA 0.014 ;
		ANTENNADIFFAREA 0.018 ;
		ANTENNAPARTIALMETALAREA 0.025 ;
	END WABL

	PIN WABLM[0]
		USE SIGNAL ;
		DIRECTION INPUT ;
		SHAPE ABUTMENT ;
		PORT
			LAYER	M2 ;
			RECT	0.03 95.615 0.15 95.765 ;
			LAYER	M3 ;
			RECT	0.03 95.615 0.15 95.765 ;
		END

		ANTENNAGATEAREA 0.014 ;
		ANTENNADIFFAREA 0.018 ;
		ANTENNAPARTIALMETALAREA 0.025 ;
	END WABLM[0]

	PIN WABLM[1]
		USE SIGNAL ;
		DIRECTION INPUT ;
		SHAPE ABUTMENT ;
		PORT
			LAYER	M2 ;
			RECT	0.03 93.815 0.15 93.965 ;
			LAYER	M3 ;
			RECT	0.03 93.815 0.15 93.965 ;
		END

		ANTENNAGATEAREA 0.014 ;
		ANTENNADIFFAREA 0.018 ;
		ANTENNAPARTIALMETALAREA 0.025 ;
	END WABLM[1]

	PIN WABLM[2]
		USE SIGNAL ;
		DIRECTION INPUT ;
		SHAPE ABUTMENT ;
		PORT
			LAYER	M2 ;
			RECT	0.03 98.265 0.15 98.415 ;
			LAYER	M3 ;
			RECT	0.03 98.265 0.15 98.415 ;
		END

		ANTENNAGATEAREA 0.014 ;
		ANTENNADIFFAREA 0.018 ;
		ANTENNAPARTIALMETALAREA 0.025 ;
	END WABLM[2]

	PIN WEN[0]
		USE SIGNAL ;
		DIRECTION INPUT ;
		SHAPE ABUTMENT ;
		PORT
			LAYER	M2 ;
			RECT	0.03 3.155 0.15 3.305 ;
			LAYER	M3 ;
			RECT	0.03 3.155 0.15 3.305 ;
		END

		ANTENNAGATEAREA 0.014 ;
		ANTENNADIFFAREA 0.018 ;
		ANTENNAPARTIALMETALAREA 0.025 ;
	END WEN[0]

	PIN WEN[10]
		USE SIGNAL ;
		DIRECTION INPUT ;
		SHAPE ABUTMENT ;
		PORT
			LAYER	M2 ;
			RECT	0.03 31.555 0.15 31.705 ;
			LAYER	M3 ;
			RECT	0.03 31.555 0.15 31.705 ;
		END

		ANTENNAGATEAREA 0.014 ;
		ANTENNADIFFAREA 0.018 ;
		ANTENNAPARTIALMETALAREA 0.025 ;
	END WEN[10]

	PIN WEN[11]
		USE SIGNAL ;
		DIRECTION INPUT ;
		SHAPE ABUTMENT ;
		PORT
			LAYER	M2 ;
			RECT	0.03 34.395 0.15 34.545 ;
			LAYER	M3 ;
			RECT	0.03 34.395 0.15 34.545 ;
		END

		ANTENNAGATEAREA 0.014 ;
		ANTENNADIFFAREA 0.018 ;
		ANTENNAPARTIALMETALAREA 0.025 ;
	END WEN[11]

	PIN WEN[12]
		USE SIGNAL ;
		DIRECTION INPUT ;
		SHAPE ABUTMENT ;
		PORT
			LAYER	M2 ;
			RECT	0.03 37.235 0.15 37.385 ;
			LAYER	M3 ;
			RECT	0.03 37.235 0.15 37.385 ;
		END

		ANTENNAGATEAREA 0.014 ;
		ANTENNADIFFAREA 0.018 ;
		ANTENNAPARTIALMETALAREA 0.025 ;
	END WEN[12]

	PIN WEN[13]
		USE SIGNAL ;
		DIRECTION INPUT ;
		SHAPE ABUTMENT ;
		PORT
			LAYER	M2 ;
			RECT	0.03 40.075 0.15 40.225 ;
			LAYER	M3 ;
			RECT	0.03 40.075 0.15 40.225 ;
		END

		ANTENNAGATEAREA 0.014 ;
		ANTENNADIFFAREA 0.018 ;
		ANTENNAPARTIALMETALAREA 0.025 ;
	END WEN[13]

	PIN WEN[14]
		USE SIGNAL ;
		DIRECTION INPUT ;
		SHAPE ABUTMENT ;
		PORT
			LAYER	M2 ;
			RECT	0.03 42.915 0.15 43.065 ;
			LAYER	M3 ;
			RECT	0.03 42.915 0.15 43.065 ;
		END

		ANTENNAGATEAREA 0.014 ;
		ANTENNADIFFAREA 0.018 ;
		ANTENNAPARTIALMETALAREA 0.025 ;
	END WEN[14]

	PIN WEN[15]
		USE SIGNAL ;
		DIRECTION INPUT ;
		SHAPE ABUTMENT ;
		PORT
			LAYER	M2 ;
			RECT	0.03 45.755 0.15 45.905 ;
			LAYER	M3 ;
			RECT	0.03 45.755 0.15 45.905 ;
		END

		ANTENNAGATEAREA 0.014 ;
		ANTENNADIFFAREA 0.018 ;
		ANTENNAPARTIALMETALAREA 0.025 ;
	END WEN[15]

	PIN WEN[16]
		USE SIGNAL ;
		DIRECTION INPUT ;
		SHAPE ABUTMENT ;
		PORT
			LAYER	M2 ;
			RECT	0.03 48.595 0.15 48.745 ;
			LAYER	M3 ;
			RECT	0.03 48.595 0.15 48.745 ;
		END

		ANTENNAGATEAREA 0.014 ;
		ANTENNADIFFAREA 0.018 ;
		ANTENNAPARTIALMETALAREA 0.025 ;
	END WEN[16]

	PIN WEN[17]
		USE SIGNAL ;
		DIRECTION INPUT ;
		SHAPE ABUTMENT ;
		PORT
			LAYER	M2 ;
			RECT	0.03 51.435 0.15 51.585 ;
			LAYER	M3 ;
			RECT	0.03 51.435 0.15 51.585 ;
		END

		ANTENNAGATEAREA 0.014 ;
		ANTENNADIFFAREA 0.018 ;
		ANTENNAPARTIALMETALAREA 0.025 ;
	END WEN[17]

	PIN WEN[18]
		USE SIGNAL ;
		DIRECTION INPUT ;
		SHAPE ABUTMENT ;
		PORT
			LAYER	M2 ;
			RECT	0.03 54.275 0.15 54.425 ;
			LAYER	M3 ;
			RECT	0.03 54.275 0.15 54.425 ;
		END

		ANTENNAGATEAREA 0.014 ;
		ANTENNADIFFAREA 0.018 ;
		ANTENNAPARTIALMETALAREA 0.025 ;
	END WEN[18]

	PIN WEN[19]
		USE SIGNAL ;
		DIRECTION INPUT ;
		SHAPE ABUTMENT ;
		PORT
			LAYER	M2 ;
			RECT	0.03 57.115 0.15 57.265 ;
			LAYER	M3 ;
			RECT	0.03 57.115 0.15 57.265 ;
		END

		ANTENNAGATEAREA 0.014 ;
		ANTENNADIFFAREA 0.018 ;
		ANTENNAPARTIALMETALAREA 0.025 ;
	END WEN[19]

	PIN WEN[1]
		USE SIGNAL ;
		DIRECTION INPUT ;
		SHAPE ABUTMENT ;
		PORT
			LAYER	M2 ;
			RECT	0.03 5.995 0.15 6.145 ;
			LAYER	M3 ;
			RECT	0.03 5.995 0.15 6.145 ;
		END

		ANTENNAGATEAREA 0.014 ;
		ANTENNADIFFAREA 0.018 ;
		ANTENNAPARTIALMETALAREA 0.025 ;
	END WEN[1]

	PIN WEN[20]
		USE SIGNAL ;
		DIRECTION INPUT ;
		SHAPE ABUTMENT ;
		PORT
			LAYER	M2 ;
			RECT	0.03 59.955 0.15 60.105 ;
			LAYER	M3 ;
			RECT	0.03 59.955 0.15 60.105 ;
		END

		ANTENNAGATEAREA 0.014 ;
		ANTENNADIFFAREA 0.018 ;
		ANTENNAPARTIALMETALAREA 0.025 ;
	END WEN[20]

	PIN WEN[21]
		USE SIGNAL ;
		DIRECTION INPUT ;
		SHAPE ABUTMENT ;
		PORT
			LAYER	M2 ;
			RECT	0.03 62.795 0.15 62.945 ;
			LAYER	M3 ;
			RECT	0.03 62.795 0.15 62.945 ;
		END

		ANTENNAGATEAREA 0.014 ;
		ANTENNADIFFAREA 0.018 ;
		ANTENNAPARTIALMETALAREA 0.025 ;
	END WEN[21]

	PIN WEN[22]
		USE SIGNAL ;
		DIRECTION INPUT ;
		SHAPE ABUTMENT ;
		PORT
			LAYER	M2 ;
			RECT	0.03 65.635 0.15 65.785 ;
			LAYER	M3 ;
			RECT	0.03 65.635 0.15 65.785 ;
		END

		ANTENNAGATEAREA 0.014 ;
		ANTENNADIFFAREA 0.018 ;
		ANTENNAPARTIALMETALAREA 0.025 ;
	END WEN[22]

	PIN WEN[23]
		USE SIGNAL ;
		DIRECTION INPUT ;
		SHAPE ABUTMENT ;
		PORT
			LAYER	M2 ;
			RECT	0.03 68.475 0.15 68.625 ;
			LAYER	M3 ;
			RECT	0.03 68.475 0.15 68.625 ;
		END

		ANTENNAGATEAREA 0.014 ;
		ANTENNADIFFAREA 0.018 ;
		ANTENNAPARTIALMETALAREA 0.025 ;
	END WEN[23]

	PIN WEN[24]
		USE SIGNAL ;
		DIRECTION INPUT ;
		SHAPE ABUTMENT ;
		PORT
			LAYER	M2 ;
			RECT	0.03 71.315 0.15 71.465 ;
			LAYER	M3 ;
			RECT	0.03 71.315 0.15 71.465 ;
		END

		ANTENNAGATEAREA 0.014 ;
		ANTENNADIFFAREA 0.018 ;
		ANTENNAPARTIALMETALAREA 0.025 ;
	END WEN[24]

	PIN WEN[25]
		USE SIGNAL ;
		DIRECTION INPUT ;
		SHAPE ABUTMENT ;
		PORT
			LAYER	M2 ;
			RECT	0.03 74.155 0.15 74.305 ;
			LAYER	M3 ;
			RECT	0.03 74.155 0.15 74.305 ;
		END

		ANTENNAGATEAREA 0.014 ;
		ANTENNADIFFAREA 0.018 ;
		ANTENNAPARTIALMETALAREA 0.025 ;
	END WEN[25]

	PIN WEN[26]
		USE SIGNAL ;
		DIRECTION INPUT ;
		SHAPE ABUTMENT ;
		PORT
			LAYER	M2 ;
			RECT	0.03 76.995 0.15 77.145 ;
			LAYER	M3 ;
			RECT	0.03 76.995 0.15 77.145 ;
		END

		ANTENNAGATEAREA 0.014 ;
		ANTENNADIFFAREA 0.018 ;
		ANTENNAPARTIALMETALAREA 0.025 ;
	END WEN[26]

	PIN WEN[27]
		USE SIGNAL ;
		DIRECTION INPUT ;
		SHAPE ABUTMENT ;
		PORT
			LAYER	M2 ;
			RECT	0.03 79.835 0.15 79.985 ;
			LAYER	M3 ;
			RECT	0.03 79.835 0.15 79.985 ;
		END

		ANTENNAGATEAREA 0.014 ;
		ANTENNADIFFAREA 0.018 ;
		ANTENNAPARTIALMETALAREA 0.025 ;
	END WEN[27]

	PIN WEN[28]
		USE SIGNAL ;
		DIRECTION INPUT ;
		SHAPE ABUTMENT ;
		PORT
			LAYER	M2 ;
			RECT	0.03 82.675 0.15 82.825 ;
			LAYER	M3 ;
			RECT	0.03 82.675 0.15 82.825 ;
		END

		ANTENNAGATEAREA 0.014 ;
		ANTENNADIFFAREA 0.018 ;
		ANTENNAPARTIALMETALAREA 0.025 ;
	END WEN[28]

	PIN WEN[29]
		USE SIGNAL ;
		DIRECTION INPUT ;
		SHAPE ABUTMENT ;
		PORT
			LAYER	M2 ;
			RECT	0.03 85.515 0.15 85.665 ;
			LAYER	M3 ;
			RECT	0.03 85.515 0.15 85.665 ;
		END

		ANTENNAGATEAREA 0.014 ;
		ANTENNADIFFAREA 0.018 ;
		ANTENNAPARTIALMETALAREA 0.025 ;
	END WEN[29]

	PIN WEN[2]
		USE SIGNAL ;
		DIRECTION INPUT ;
		SHAPE ABUTMENT ;
		PORT
			LAYER	M2 ;
			RECT	0.03 8.835 0.15 8.985 ;
			LAYER	M3 ;
			RECT	0.03 8.835 0.15 8.985 ;
		END

		ANTENNAGATEAREA 0.014 ;
		ANTENNADIFFAREA 0.018 ;
		ANTENNAPARTIALMETALAREA 0.025 ;
	END WEN[2]

	PIN WEN[30]
		USE SIGNAL ;
		DIRECTION INPUT ;
		SHAPE ABUTMENT ;
		PORT
			LAYER	M2 ;
			RECT	0.03 88.355 0.15 88.505 ;
			LAYER	M3 ;
			RECT	0.03 88.355 0.15 88.505 ;
		END

		ANTENNAGATEAREA 0.014 ;
		ANTENNADIFFAREA 0.018 ;
		ANTENNAPARTIALMETALAREA 0.025 ;
	END WEN[30]

	PIN WEN[31]
		USE SIGNAL ;
		DIRECTION INPUT ;
		SHAPE ABUTMENT ;
		PORT
			LAYER	M2 ;
			RECT	0.03 91.195 0.15 91.345 ;
			LAYER	M3 ;
			RECT	0.03 91.195 0.15 91.345 ;
		END

		ANTENNAGATEAREA 0.014 ;
		ANTENNADIFFAREA 0.018 ;
		ANTENNAPARTIALMETALAREA 0.025 ;
	END WEN[31]

	PIN WEN[32]
		USE SIGNAL ;
		DIRECTION INPUT ;
		SHAPE ABUTMENT ;
		PORT
			LAYER	M2 ;
			RECT	0.03 115.805 0.15 115.955 ;
			LAYER	M3 ;
			RECT	0.03 115.805 0.15 115.955 ;
		END

		ANTENNAGATEAREA 0.014 ;
		ANTENNADIFFAREA 0.018 ;
		ANTENNAPARTIALMETALAREA 0.025 ;
	END WEN[32]

	PIN WEN[33]
		USE SIGNAL ;
		DIRECTION INPUT ;
		SHAPE ABUTMENT ;
		PORT
			LAYER	M2 ;
			RECT	0.03 118.645 0.15 118.795 ;
			LAYER	M3 ;
			RECT	0.03 118.645 0.15 118.795 ;
		END

		ANTENNAGATEAREA 0.014 ;
		ANTENNADIFFAREA 0.018 ;
		ANTENNAPARTIALMETALAREA 0.025 ;
	END WEN[33]

	PIN WEN[34]
		USE SIGNAL ;
		DIRECTION INPUT ;
		SHAPE ABUTMENT ;
		PORT
			LAYER	M2 ;
			RECT	0.03 121.485 0.15 121.635 ;
			LAYER	M3 ;
			RECT	0.03 121.485 0.15 121.635 ;
		END

		ANTENNAGATEAREA 0.014 ;
		ANTENNADIFFAREA 0.018 ;
		ANTENNAPARTIALMETALAREA 0.025 ;
	END WEN[34]

	PIN WEN[35]
		USE SIGNAL ;
		DIRECTION INPUT ;
		SHAPE ABUTMENT ;
		PORT
			LAYER	M2 ;
			RECT	0.03 124.325 0.15 124.475 ;
			LAYER	M3 ;
			RECT	0.03 124.325 0.15 124.475 ;
		END

		ANTENNAGATEAREA 0.014 ;
		ANTENNADIFFAREA 0.018 ;
		ANTENNAPARTIALMETALAREA 0.025 ;
	END WEN[35]

	PIN WEN[36]
		USE SIGNAL ;
		DIRECTION INPUT ;
		SHAPE ABUTMENT ;
		PORT
			LAYER	M2 ;
			RECT	0.03 127.165 0.15 127.315 ;
			LAYER	M3 ;
			RECT	0.03 127.165 0.15 127.315 ;
		END

		ANTENNAGATEAREA 0.014 ;
		ANTENNADIFFAREA 0.018 ;
		ANTENNAPARTIALMETALAREA 0.025 ;
	END WEN[36]

	PIN WEN[37]
		USE SIGNAL ;
		DIRECTION INPUT ;
		SHAPE ABUTMENT ;
		PORT
			LAYER	M2 ;
			RECT	0.03 130.005 0.15 130.155 ;
			LAYER	M3 ;
			RECT	0.03 130.005 0.15 130.155 ;
		END

		ANTENNAGATEAREA 0.014 ;
		ANTENNADIFFAREA 0.018 ;
		ANTENNAPARTIALMETALAREA 0.025 ;
	END WEN[37]

	PIN WEN[38]
		USE SIGNAL ;
		DIRECTION INPUT ;
		SHAPE ABUTMENT ;
		PORT
			LAYER	M2 ;
			RECT	0.03 132.845 0.15 132.995 ;
			LAYER	M3 ;
			RECT	0.03 132.845 0.15 132.995 ;
		END

		ANTENNAGATEAREA 0.014 ;
		ANTENNADIFFAREA 0.018 ;
		ANTENNAPARTIALMETALAREA 0.025 ;
	END WEN[38]

	PIN WEN[39]
		USE SIGNAL ;
		DIRECTION INPUT ;
		SHAPE ABUTMENT ;
		PORT
			LAYER	M2 ;
			RECT	0.03 135.685 0.15 135.835 ;
			LAYER	M3 ;
			RECT	0.03 135.685 0.15 135.835 ;
		END

		ANTENNAGATEAREA 0.014 ;
		ANTENNADIFFAREA 0.018 ;
		ANTENNAPARTIALMETALAREA 0.025 ;
	END WEN[39]

	PIN WEN[3]
		USE SIGNAL ;
		DIRECTION INPUT ;
		SHAPE ABUTMENT ;
		PORT
			LAYER	M2 ;
			RECT	0.03 11.675 0.15 11.825 ;
			LAYER	M3 ;
			RECT	0.03 11.675 0.15 11.825 ;
		END

		ANTENNAGATEAREA 0.014 ;
		ANTENNADIFFAREA 0.018 ;
		ANTENNAPARTIALMETALAREA 0.025 ;
	END WEN[3]

	PIN WEN[40]
		USE SIGNAL ;
		DIRECTION INPUT ;
		SHAPE ABUTMENT ;
		PORT
			LAYER	M2 ;
			RECT	0.03 138.525 0.15 138.675 ;
			LAYER	M3 ;
			RECT	0.03 138.525 0.15 138.675 ;
		END

		ANTENNAGATEAREA 0.014 ;
		ANTENNADIFFAREA 0.018 ;
		ANTENNAPARTIALMETALAREA 0.025 ;
	END WEN[40]

	PIN WEN[41]
		USE SIGNAL ;
		DIRECTION INPUT ;
		SHAPE ABUTMENT ;
		PORT
			LAYER	M2 ;
			RECT	0.03 141.365 0.15 141.515 ;
			LAYER	M3 ;
			RECT	0.03 141.365 0.15 141.515 ;
		END

		ANTENNAGATEAREA 0.014 ;
		ANTENNADIFFAREA 0.018 ;
		ANTENNAPARTIALMETALAREA 0.025 ;
	END WEN[41]

	PIN WEN[42]
		USE SIGNAL ;
		DIRECTION INPUT ;
		SHAPE ABUTMENT ;
		PORT
			LAYER	M2 ;
			RECT	0.03 144.205 0.15 144.355 ;
			LAYER	M3 ;
			RECT	0.03 144.205 0.15 144.355 ;
		END

		ANTENNAGATEAREA 0.014 ;
		ANTENNADIFFAREA 0.018 ;
		ANTENNAPARTIALMETALAREA 0.025 ;
	END WEN[42]

	PIN WEN[43]
		USE SIGNAL ;
		DIRECTION INPUT ;
		SHAPE ABUTMENT ;
		PORT
			LAYER	M2 ;
			RECT	0.03 147.045 0.15 147.195 ;
			LAYER	M3 ;
			RECT	0.03 147.045 0.15 147.195 ;
		END

		ANTENNAGATEAREA 0.014 ;
		ANTENNADIFFAREA 0.018 ;
		ANTENNAPARTIALMETALAREA 0.025 ;
	END WEN[43]

	PIN WEN[44]
		USE SIGNAL ;
		DIRECTION INPUT ;
		SHAPE ABUTMENT ;
		PORT
			LAYER	M2 ;
			RECT	0.03 149.885 0.15 150.035 ;
			LAYER	M3 ;
			RECT	0.03 149.885 0.15 150.035 ;
		END

		ANTENNAGATEAREA 0.014 ;
		ANTENNADIFFAREA 0.018 ;
		ANTENNAPARTIALMETALAREA 0.025 ;
	END WEN[44]

	PIN WEN[45]
		USE SIGNAL ;
		DIRECTION INPUT ;
		SHAPE ABUTMENT ;
		PORT
			LAYER	M2 ;
			RECT	0.03 152.725 0.15 152.875 ;
			LAYER	M3 ;
			RECT	0.03 152.725 0.15 152.875 ;
		END

		ANTENNAGATEAREA 0.014 ;
		ANTENNADIFFAREA 0.018 ;
		ANTENNAPARTIALMETALAREA 0.025 ;
	END WEN[45]

	PIN WEN[46]
		USE SIGNAL ;
		DIRECTION INPUT ;
		SHAPE ABUTMENT ;
		PORT
			LAYER	M2 ;
			RECT	0.03 155.565 0.15 155.715 ;
			LAYER	M3 ;
			RECT	0.03 155.565 0.15 155.715 ;
		END

		ANTENNAGATEAREA 0.014 ;
		ANTENNADIFFAREA 0.018 ;
		ANTENNAPARTIALMETALAREA 0.025 ;
	END WEN[46]

	PIN WEN[47]
		USE SIGNAL ;
		DIRECTION INPUT ;
		SHAPE ABUTMENT ;
		PORT
			LAYER	M2 ;
			RECT	0.03 158.405 0.15 158.555 ;
			LAYER	M3 ;
			RECT	0.03 158.405 0.15 158.555 ;
		END

		ANTENNAGATEAREA 0.014 ;
		ANTENNADIFFAREA 0.018 ;
		ANTENNAPARTIALMETALAREA 0.025 ;
	END WEN[47]

	PIN WEN[48]
		USE SIGNAL ;
		DIRECTION INPUT ;
		SHAPE ABUTMENT ;
		PORT
			LAYER	M2 ;
			RECT	0.03 161.245 0.15 161.395 ;
			LAYER	M3 ;
			RECT	0.03 161.245 0.15 161.395 ;
		END

		ANTENNAGATEAREA 0.014 ;
		ANTENNADIFFAREA 0.018 ;
		ANTENNAPARTIALMETALAREA 0.025 ;
	END WEN[48]

	PIN WEN[49]
		USE SIGNAL ;
		DIRECTION INPUT ;
		SHAPE ABUTMENT ;
		PORT
			LAYER	M2 ;
			RECT	0.03 164.085 0.15 164.235 ;
			LAYER	M3 ;
			RECT	0.03 164.085 0.15 164.235 ;
		END

		ANTENNAGATEAREA 0.014 ;
		ANTENNADIFFAREA 0.018 ;
		ANTENNAPARTIALMETALAREA 0.025 ;
	END WEN[49]

	PIN WEN[4]
		USE SIGNAL ;
		DIRECTION INPUT ;
		SHAPE ABUTMENT ;
		PORT
			LAYER	M2 ;
			RECT	0.03 14.515 0.15 14.665 ;
			LAYER	M3 ;
			RECT	0.03 14.515 0.15 14.665 ;
		END

		ANTENNAGATEAREA 0.014 ;
		ANTENNADIFFAREA 0.018 ;
		ANTENNAPARTIALMETALAREA 0.025 ;
	END WEN[4]

	PIN WEN[50]
		USE SIGNAL ;
		DIRECTION INPUT ;
		SHAPE ABUTMENT ;
		PORT
			LAYER	M2 ;
			RECT	0.03 166.925 0.15 167.075 ;
			LAYER	M3 ;
			RECT	0.03 166.925 0.15 167.075 ;
		END

		ANTENNAGATEAREA 0.014 ;
		ANTENNADIFFAREA 0.018 ;
		ANTENNAPARTIALMETALAREA 0.025 ;
	END WEN[50]

	PIN WEN[51]
		USE SIGNAL ;
		DIRECTION INPUT ;
		SHAPE ABUTMENT ;
		PORT
			LAYER	M2 ;
			RECT	0.03 169.765 0.15 169.915 ;
			LAYER	M3 ;
			RECT	0.03 169.765 0.15 169.915 ;
		END

		ANTENNAGATEAREA 0.014 ;
		ANTENNADIFFAREA 0.018 ;
		ANTENNAPARTIALMETALAREA 0.025 ;
	END WEN[51]

	PIN WEN[52]
		USE SIGNAL ;
		DIRECTION INPUT ;
		SHAPE ABUTMENT ;
		PORT
			LAYER	M2 ;
			RECT	0.03 172.605 0.15 172.755 ;
			LAYER	M3 ;
			RECT	0.03 172.605 0.15 172.755 ;
		END

		ANTENNAGATEAREA 0.014 ;
		ANTENNADIFFAREA 0.018 ;
		ANTENNAPARTIALMETALAREA 0.025 ;
	END WEN[52]

	PIN WEN[53]
		USE SIGNAL ;
		DIRECTION INPUT ;
		SHAPE ABUTMENT ;
		PORT
			LAYER	M2 ;
			RECT	0.03 175.445 0.15 175.595 ;
			LAYER	M3 ;
			RECT	0.03 175.445 0.15 175.595 ;
		END

		ANTENNAGATEAREA 0.014 ;
		ANTENNADIFFAREA 0.018 ;
		ANTENNAPARTIALMETALAREA 0.025 ;
	END WEN[53]

	PIN WEN[54]
		USE SIGNAL ;
		DIRECTION INPUT ;
		SHAPE ABUTMENT ;
		PORT
			LAYER	M2 ;
			RECT	0.03 178.285 0.15 178.435 ;
			LAYER	M3 ;
			RECT	0.03 178.285 0.15 178.435 ;
		END

		ANTENNAGATEAREA 0.014 ;
		ANTENNADIFFAREA 0.018 ;
		ANTENNAPARTIALMETALAREA 0.025 ;
	END WEN[54]

	PIN WEN[55]
		USE SIGNAL ;
		DIRECTION INPUT ;
		SHAPE ABUTMENT ;
		PORT
			LAYER	M2 ;
			RECT	0.03 181.125 0.15 181.275 ;
			LAYER	M3 ;
			RECT	0.03 181.125 0.15 181.275 ;
		END

		ANTENNAGATEAREA 0.014 ;
		ANTENNADIFFAREA 0.018 ;
		ANTENNAPARTIALMETALAREA 0.025 ;
	END WEN[55]

	PIN WEN[56]
		USE SIGNAL ;
		DIRECTION INPUT ;
		SHAPE ABUTMENT ;
		PORT
			LAYER	M2 ;
			RECT	0.03 183.965 0.15 184.115 ;
			LAYER	M3 ;
			RECT	0.03 183.965 0.15 184.115 ;
		END

		ANTENNAGATEAREA 0.014 ;
		ANTENNADIFFAREA 0.018 ;
		ANTENNAPARTIALMETALAREA 0.025 ;
	END WEN[56]

	PIN WEN[57]
		USE SIGNAL ;
		DIRECTION INPUT ;
		SHAPE ABUTMENT ;
		PORT
			LAYER	M2 ;
			RECT	0.03 186.805 0.15 186.955 ;
			LAYER	M3 ;
			RECT	0.03 186.805 0.15 186.955 ;
		END

		ANTENNAGATEAREA 0.014 ;
		ANTENNADIFFAREA 0.018 ;
		ANTENNAPARTIALMETALAREA 0.025 ;
	END WEN[57]

	PIN WEN[58]
		USE SIGNAL ;
		DIRECTION INPUT ;
		SHAPE ABUTMENT ;
		PORT
			LAYER	M2 ;
			RECT	0.03 189.645 0.15 189.795 ;
			LAYER	M3 ;
			RECT	0.03 189.645 0.15 189.795 ;
		END

		ANTENNAGATEAREA 0.014 ;
		ANTENNADIFFAREA 0.018 ;
		ANTENNAPARTIALMETALAREA 0.025 ;
	END WEN[58]

	PIN WEN[59]
		USE SIGNAL ;
		DIRECTION INPUT ;
		SHAPE ABUTMENT ;
		PORT
			LAYER	M2 ;
			RECT	0.03 192.485 0.15 192.635 ;
			LAYER	M3 ;
			RECT	0.03 192.485 0.15 192.635 ;
		END

		ANTENNAGATEAREA 0.014 ;
		ANTENNADIFFAREA 0.018 ;
		ANTENNAPARTIALMETALAREA 0.025 ;
	END WEN[59]

	PIN WEN[5]
		USE SIGNAL ;
		DIRECTION INPUT ;
		SHAPE ABUTMENT ;
		PORT
			LAYER	M2 ;
			RECT	0.03 17.355 0.15 17.505 ;
			LAYER	M3 ;
			RECT	0.03 17.355 0.15 17.505 ;
		END

		ANTENNAGATEAREA 0.014 ;
		ANTENNADIFFAREA 0.018 ;
		ANTENNAPARTIALMETALAREA 0.025 ;
	END WEN[5]

	PIN WEN[60]
		USE SIGNAL ;
		DIRECTION INPUT ;
		SHAPE ABUTMENT ;
		PORT
			LAYER	M2 ;
			RECT	0.03 195.325 0.15 195.475 ;
			LAYER	M3 ;
			RECT	0.03 195.325 0.15 195.475 ;
		END

		ANTENNAGATEAREA 0.014 ;
		ANTENNADIFFAREA 0.018 ;
		ANTENNAPARTIALMETALAREA 0.025 ;
	END WEN[60]

	PIN WEN[61]
		USE SIGNAL ;
		DIRECTION INPUT ;
		SHAPE ABUTMENT ;
		PORT
			LAYER	M2 ;
			RECT	0.03 198.165 0.15 198.315 ;
			LAYER	M3 ;
			RECT	0.03 198.165 0.15 198.315 ;
		END

		ANTENNAGATEAREA 0.014 ;
		ANTENNADIFFAREA 0.018 ;
		ANTENNAPARTIALMETALAREA 0.025 ;
	END WEN[61]

	PIN WEN[62]
		USE SIGNAL ;
		DIRECTION INPUT ;
		SHAPE ABUTMENT ;
		PORT
			LAYER	M2 ;
			RECT	0.03 201.005 0.15 201.155 ;
			LAYER	M3 ;
			RECT	0.03 201.005 0.15 201.155 ;
		END

		ANTENNAGATEAREA 0.014 ;
		ANTENNADIFFAREA 0.018 ;
		ANTENNAPARTIALMETALAREA 0.025 ;
	END WEN[62]

	PIN WEN[63]
		USE SIGNAL ;
		DIRECTION INPUT ;
		SHAPE ABUTMENT ;
		PORT
			LAYER	M2 ;
			RECT	0.03 203.845 0.15 203.995 ;
			LAYER	M3 ;
			RECT	0.03 203.845 0.15 203.995 ;
		END

		ANTENNAGATEAREA 0.014 ;
		ANTENNADIFFAREA 0.018 ;
		ANTENNAPARTIALMETALAREA 0.025 ;
	END WEN[63]

	PIN WEN[6]
		USE SIGNAL ;
		DIRECTION INPUT ;
		SHAPE ABUTMENT ;
		PORT
			LAYER	M2 ;
			RECT	0.03 20.195 0.15 20.345 ;
			LAYER	M3 ;
			RECT	0.03 20.195 0.15 20.345 ;
		END

		ANTENNAGATEAREA 0.014 ;
		ANTENNADIFFAREA 0.018 ;
		ANTENNAPARTIALMETALAREA 0.025 ;
	END WEN[6]

	PIN WEN[7]
		USE SIGNAL ;
		DIRECTION INPUT ;
		SHAPE ABUTMENT ;
		PORT
			LAYER	M2 ;
			RECT	0.03 23.035 0.15 23.185 ;
			LAYER	M3 ;
			RECT	0.03 23.035 0.15 23.185 ;
		END

		ANTENNAGATEAREA 0.014 ;
		ANTENNADIFFAREA 0.018 ;
		ANTENNAPARTIALMETALAREA 0.025 ;
	END WEN[7]

	PIN WEN[8]
		USE SIGNAL ;
		DIRECTION INPUT ;
		SHAPE ABUTMENT ;
		PORT
			LAYER	M2 ;
			RECT	0.03 25.875 0.15 26.025 ;
			LAYER	M3 ;
			RECT	0.03 25.875 0.15 26.025 ;
		END

		ANTENNAGATEAREA 0.014 ;
		ANTENNADIFFAREA 0.018 ;
		ANTENNAPARTIALMETALAREA 0.025 ;
	END WEN[8]

	PIN WEN[9]
		USE SIGNAL ;
		DIRECTION INPUT ;
		SHAPE ABUTMENT ;
		PORT
			LAYER	M2 ;
			RECT	0.03 28.715 0.15 28.865 ;
			LAYER	M3 ;
			RECT	0.03 28.715 0.15 28.865 ;
		END

		ANTENNAGATEAREA 0.014 ;
		ANTENNADIFFAREA 0.018 ;
		ANTENNAPARTIALMETALAREA 0.025 ;
	END WEN[9]

	OBS
		LAYER	M1 DESIGNRULEWIDTH 0.1 ;
		RECT	0 0 121.075 207.15 ;
		LAYER	M2 DESIGNRULEWIDTH 0.1 ;
		RECT	0.2 0 121.075 207.15 ;
		RECT	0 0 0.2 1.595 ;
		RECT	0 2.045 0.2 2.905 ;
		RECT	0 3.355 0.2 4.435 ;
		RECT	0 4.885 0.2 5.745 ;
		RECT	0 6.195 0.2 7.275 ;
		RECT	0 7.725 0.2 8.585 ;
		RECT	0 9.035 0.2 10.115 ;
		RECT	0 10.565 0.2 11.425 ;
		RECT	0 11.875 0.2 12.955 ;
		RECT	0 13.405 0.2 14.265 ;
		RECT	0 14.715 0.2 15.795 ;
		RECT	0 16.245 0.2 17.105 ;
		RECT	0 17.555 0.2 18.635 ;
		RECT	0 19.085 0.2 19.945 ;
		RECT	0 20.395 0.2 21.475 ;
		RECT	0 21.925 0.2 22.785 ;
		RECT	0 23.235 0.2 24.315 ;
		RECT	0 24.765 0.2 25.625 ;
		RECT	0 26.075 0.2 27.155 ;
		RECT	0 27.605 0.2 28.465 ;
		RECT	0 28.915 0.2 29.995 ;
		RECT	0 30.445 0.2 31.305 ;
		RECT	0 31.755 0.2 32.835 ;
		RECT	0 33.285 0.2 34.145 ;
		RECT	0 34.595 0.2 35.675 ;
		RECT	0 36.125 0.2 36.985 ;
		RECT	0 37.435 0.2 38.515 ;
		RECT	0 38.965 0.2 39.825 ;
		RECT	0 40.275 0.2 41.355 ;
		RECT	0 41.805 0.2 42.665 ;
		RECT	0 43.115 0.2 44.195 ;
		RECT	0 44.645 0.2 45.505 ;
		RECT	0 45.955 0.2 47.035 ;
		RECT	0 47.485 0.2 48.345 ;
		RECT	0 48.795 0.2 49.875 ;
		RECT	0 50.325 0.2 51.185 ;
		RECT	0 51.635 0.2 52.715 ;
		RECT	0 53.165 0.2 54.025 ;
		RECT	0 54.475 0.2 55.555 ;
		RECT	0 56.005 0.2 56.865 ;
		RECT	0 57.315 0.2 58.395 ;
		RECT	0 58.845 0.2 59.705 ;
		RECT	0 60.155 0.2 61.235 ;
		RECT	0 61.685 0.2 62.545 ;
		RECT	0 62.995 0.2 64.075 ;
		RECT	0 64.525 0.2 65.385 ;
		RECT	0 65.835 0.2 66.915 ;
		RECT	0 67.365 0.2 68.225 ;
		RECT	0 68.675 0.2 69.755 ;
		RECT	0 70.205 0.2 71.065 ;
		RECT	0 71.515 0.2 72.595 ;
		RECT	0 73.045 0.2 73.905 ;
		RECT	0 74.355 0.2 75.435 ;
		RECT	0 75.885 0.2 76.745 ;
		RECT	0 77.195 0.2 78.275 ;
		RECT	0 78.725 0.2 79.585 ;
		RECT	0 80.035 0.2 81.115 ;
		RECT	0 81.565 0.2 82.425 ;
		RECT	0 82.875 0.2 83.955 ;
		RECT	0 84.405 0.2 85.265 ;
		RECT	0 85.715 0.2 86.795 ;
		RECT	0 87.245 0.2 88.105 ;
		RECT	0 88.555 0.2 89.635 ;
		RECT	0 90.085 0.2 90.945 ;
		RECT	0 91.395 0.2 92.36 ;
		RECT	0 92.81 0.2 93.765 ;
		RECT	0 94.415 0.2 95.565 ;
		RECT	0 96.015 0.2 96.665 ;
		RECT	0 96.915 0.2 97.065 ;
		RECT	0 97.315 0.2 97.565 ;
		RECT	0 98.465 0.2 99.265 ;
		RECT	0 99.715 0.2 99.865 ;
		RECT	0 100.115 0.2 100.265 ;
		RECT	0 100.515 0.2 100.865 ;
		RECT	0 101.115 0.2 101.265 ;
		RECT	0 101.515 0.2 101.665 ;
		RECT	0 101.915 0.2 103.065 ;
		RECT	0 103.315 0.2 105.265 ;
		RECT	0 105.515 0.2 106.265 ;
		RECT	0 106.515 0.2 107.065 ;
		RECT	0 107.315 0.2 107.865 ;
		RECT	0 108.115 0.2 108.265 ;
		RECT	0 108.715 0.2 109.665 ;
		RECT	0 109.915 0.2 110.265 ;
		RECT	0 110.515 0.2 114.265 ;
		RECT	0 115.115 0.2 115.755 ;
		RECT	0 116.205 0.2 117.065 ;
		RECT	0 117.515 0.2 118.595 ;
		RECT	0 119.045 0.2 119.905 ;
		RECT	0 120.355 0.2 121.435 ;
		RECT	0 121.885 0.2 122.745 ;
		RECT	0 123.195 0.2 124.275 ;
		RECT	0 124.725 0.2 125.585 ;
		RECT	0 126.035 0.2 127.115 ;
		RECT	0 127.565 0.2 128.425 ;
		RECT	0 128.875 0.2 129.955 ;
		RECT	0 130.405 0.2 131.265 ;
		RECT	0 131.715 0.2 132.795 ;
		RECT	0 133.245 0.2 134.105 ;
		RECT	0 134.555 0.2 135.635 ;
		RECT	0 136.085 0.2 136.945 ;
		RECT	0 137.395 0.2 138.475 ;
		RECT	0 138.925 0.2 139.785 ;
		RECT	0 140.235 0.2 141.315 ;
		RECT	0 141.765 0.2 142.625 ;
		RECT	0 143.075 0.2 144.155 ;
		RECT	0 144.605 0.2 145.465 ;
		RECT	0 145.915 0.2 146.995 ;
		RECT	0 147.445 0.2 148.305 ;
		RECT	0 148.755 0.2 149.835 ;
		RECT	0 150.285 0.2 151.145 ;
		RECT	0 151.595 0.2 152.675 ;
		RECT	0 153.125 0.2 153.985 ;
		RECT	0 154.435 0.2 155.515 ;
		RECT	0 155.965 0.2 156.825 ;
		RECT	0 157.275 0.2 158.355 ;
		RECT	0 158.805 0.2 159.665 ;
		RECT	0 160.115 0.2 161.195 ;
		RECT	0 161.645 0.2 162.505 ;
		RECT	0 162.955 0.2 164.035 ;
		RECT	0 164.485 0.2 165.345 ;
		RECT	0 165.795 0.2 166.875 ;
		RECT	0 167.325 0.2 168.185 ;
		RECT	0 168.635 0.2 169.715 ;
		RECT	0 170.165 0.2 171.025 ;
		RECT	0 171.475 0.2 172.555 ;
		RECT	0 173.005 0.2 173.865 ;
		RECT	0 174.315 0.2 175.395 ;
		RECT	0 175.845 0.2 176.705 ;
		RECT	0 177.155 0.2 178.235 ;
		RECT	0 178.685 0.2 179.545 ;
		RECT	0 179.995 0.2 181.075 ;
		RECT	0 181.525 0.2 182.385 ;
		RECT	0 182.835 0.2 183.915 ;
		RECT	0 184.365 0.2 185.225 ;
		RECT	0 185.675 0.2 186.755 ;
		RECT	0 187.205 0.2 188.065 ;
		RECT	0 188.515 0.2 189.595 ;
		RECT	0 190.045 0.2 190.905 ;
		RECT	0 191.355 0.2 192.435 ;
		RECT	0 192.885 0.2 193.745 ;
		RECT	0 194.195 0.2 195.275 ;
		RECT	0 195.725 0.2 196.585 ;
		RECT	0 197.035 0.2 198.115 ;
		RECT	0 198.565 0.2 199.425 ;
		RECT	0 199.875 0.2 200.955 ;
		RECT	0 201.405 0.2 202.265 ;
		RECT	0 202.715 0.2 203.795 ;
		RECT	0 204.245 0.2 205.105 ;
		RECT	0 205.555 0.2 207.15 ;
		RECT	0.03 109.515 0.15 109.665 ;
		RECT	0.03 108.115 0.15 108.265 ;
		RECT	0.03 95.315 0.15 95.465 ;
		RECT	0.03 55.155 0.14 55.505 ;
		RECT	0.03 56.515 0.15 56.665 ;
		RECT	0.03 56.715 0.15 56.865 ;
		RECT	0.03 6.875 0.14 7.225 ;
		RECT	0.03 8.235 0.15 8.385 ;
		RECT	0.03 8.435 0.15 8.585 ;
		RECT	0.03 57.995 0.14 58.345 ;
		RECT	0.03 59.355 0.15 59.505 ;
		RECT	0.03 59.555 0.15 59.705 ;
		RECT	0.03 60.835 0.14 61.185 ;
		RECT	0.03 94.715 0.15 94.865 ;
		RECT	0.03 62.195 0.15 62.345 ;
		RECT	0.03 62.395 0.15 62.545 ;
		RECT	0.03 63.675 0.14 64.025 ;
		RECT	0.03 65.035 0.15 65.185 ;
		RECT	0.03 65.235 0.15 65.385 ;
		RECT	0.03 66.515 0.14 66.865 ;
		RECT	0.03 67.875 0.15 68.025 ;
		RECT	0.03 68.075 0.15 68.225 ;
		RECT	0.03 69.355 0.14 69.705 ;
		RECT	0.03 70.715 0.15 70.865 ;
		RECT	0.03 94.915 0.15 95.065 ;
		RECT	0.03 70.915 0.15 71.065 ;
		RECT	0.03 72.195 0.14 72.545 ;
		RECT	0.03 73.555 0.15 73.705 ;
		RECT	0.03 73.755 0.15 73.905 ;
		RECT	0.03 75.035 0.14 75.385 ;
		RECT	0.03 76.395 0.15 76.545 ;
		RECT	0.03 76.595 0.15 76.745 ;
		RECT	0.03 77.875 0.14 78.225 ;
		RECT	0.03 79.235 0.15 79.385 ;
		RECT	0.03 79.435 0.15 79.585 ;
		RECT	0.03 112.715 0.15 112.865 ;
		RECT	0.03 80.715 0.14 81.065 ;
		RECT	0.03 82.075 0.15 82.225 ;
		RECT	0.03 82.275 0.15 82.425 ;
		RECT	0.03 83.555 0.14 83.905 ;
		RECT	0.03 84.915 0.15 85.065 ;
		RECT	0.03 85.115 0.15 85.265 ;
		RECT	0.03 9.715 0.14 10.065 ;
		RECT	0.03 11.075 0.15 11.225 ;
		RECT	0.03 11.275 0.15 11.425 ;
		RECT	0.03 86.395 0.14 86.745 ;
		RECT	0.03 112.915 0.15 113.065 ;
		RECT	0.03 87.755 0.15 87.905 ;
		RECT	0.03 87.955 0.15 88.105 ;
		RECT	0.03 12.555 0.14 12.905 ;
		RECT	0.03 13.915 0.15 14.065 ;
		RECT	0.03 14.115 0.15 14.265 ;
		RECT	0.03 15.395 0.14 15.745 ;
		RECT	0.03 16.755 0.15 16.905 ;
		RECT	0.03 16.955 0.15 17.105 ;
		RECT	0.03 18.235 0.14 18.585 ;
		RECT	0.03 19.595 0.15 19.745 ;
		RECT	0.03 104.715 0.15 104.865 ;
		RECT	0.03 19.795 0.15 19.945 ;
		RECT	0.03 21.075 0.14 21.425 ;
		RECT	0.03 22.435 0.15 22.585 ;
		RECT	0.03 22.635 0.15 22.785 ;
		RECT	0.03 23.915 0.14 24.265 ;
		RECT	0.03 25.275 0.15 25.425 ;
		RECT	0.03 25.475 0.15 25.625 ;
		RECT	0.03 26.755 0.14 27.105 ;
		RECT	0.03 28.115 0.15 28.265 ;
		RECT	0.03 28.315 0.15 28.465 ;
		RECT	0.03 104.915 0.15 105.065 ;
		RECT	0.03 1.195 0.14 1.545 ;
		RECT	0.03 2.555 0.15 2.705 ;
		RECT	0.03 2.755 0.15 2.905 ;
		RECT	0.03 89.235 0.14 89.585 ;
		RECT	0.03 90.595 0.15 90.745 ;
		RECT	0.03 90.795 0.15 90.945 ;
		RECT	0.03 0.45 0.14 0.8 ;
		RECT	0.03 0.05 0.14 0.4 ;
		RECT	0.03 120.405 0.14 120.755 ;
		RECT	0.03 119.245 0.15 119.395 ;
		RECT	0.03 101.115 0.15 101.265 ;
		RECT	0.03 119.045 0.15 119.195 ;
		RECT	0.03 145.965 0.14 146.315 ;
		RECT	0.03 144.805 0.15 144.955 ;
		RECT	0.03 144.605 0.15 144.755 ;
		RECT	0.03 148.805 0.14 149.155 ;
		RECT	0.03 147.645 0.15 147.795 ;
		RECT	0.03 147.445 0.15 147.595 ;
		RECT	0.03 151.645 0.14 151.995 ;
		RECT	0.03 150.485 0.15 150.635 ;
		RECT	0.03 150.285 0.15 150.435 ;
		RECT	0.03 113.915 0.15 114.065 ;
		RECT	0.03 154.485 0.14 154.835 ;
		RECT	0.03 153.325 0.15 153.475 ;
		RECT	0.03 153.125 0.15 153.275 ;
		RECT	0.03 157.325 0.14 157.675 ;
		RECT	0.03 156.165 0.15 156.315 ;
		RECT	0.03 155.965 0.15 156.115 ;
		RECT	0.03 160.165 0.14 160.515 ;
		RECT	0.03 159.005 0.15 159.155 ;
		RECT	0.03 158.805 0.15 158.955 ;
		RECT	0.03 163.005 0.14 163.355 ;
		RECT	0.03 114.115 0.15 114.265 ;
		RECT	0.03 161.845 0.15 161.995 ;
		RECT	0.03 161.645 0.15 161.795 ;
		RECT	0.03 165.845 0.14 166.195 ;
		RECT	0.03 164.685 0.15 164.835 ;
		RECT	0.03 164.485 0.15 164.635 ;
		RECT	0.03 168.685 0.14 169.035 ;
		RECT	0.03 167.525 0.15 167.675 ;
		RECT	0.03 167.325 0.15 167.475 ;
		RECT	0.03 171.525 0.14 171.875 ;
		RECT	0.03 170.365 0.15 170.515 ;
		RECT	0.03 103.915 0.15 104.065 ;
		RECT	0.03 111.915 0.15 112.065 ;
		RECT	0.03 170.165 0.15 170.315 ;
		RECT	0.03 123.245 0.14 123.595 ;
		RECT	0.03 122.085 0.15 122.235 ;
		RECT	0.03 121.885 0.15 122.035 ;
		RECT	0.03 174.365 0.14 174.715 ;
		RECT	0.03 173.205 0.15 173.355 ;
		RECT	0.03 173.005 0.15 173.155 ;
		RECT	0.03 177.205 0.14 177.555 ;
		RECT	0.03 176.045 0.15 176.195 ;
		RECT	0.03 175.845 0.15 175.995 ;
		RECT	0.03 112.115 0.15 112.265 ;
		RECT	0.03 180.045 0.14 180.395 ;
		RECT	0.03 178.885 0.15 179.035 ;
		RECT	0.03 178.685 0.15 178.835 ;
		RECT	0.03 182.885 0.14 183.235 ;
		RECT	0.03 181.725 0.15 181.875 ;
		RECT	0.03 181.525 0.15 181.675 ;
		RECT	0.03 185.725 0.14 186.075 ;
		RECT	0.03 184.565 0.15 184.715 ;
		RECT	0.03 184.365 0.15 184.515 ;
		RECT	0.03 188.565 0.14 188.915 ;
		RECT	0.03 96.515 0.15 96.665 ;
		RECT	0.03 187.405 0.15 187.555 ;
		RECT	0.03 187.205 0.15 187.355 ;
		RECT	0.03 191.405 0.14 191.755 ;
		RECT	0.03 190.245 0.15 190.395 ;
		RECT	0.03 190.045 0.15 190.195 ;
		RECT	0.03 194.245 0.14 194.595 ;
		RECT	0.03 193.085 0.15 193.235 ;
		RECT	0.03 192.885 0.15 193.035 ;
		RECT	0.03 197.085 0.14 197.435 ;
		RECT	0.03 195.925 0.15 196.075 ;
		RECT	0.03 97.415 0.15 97.565 ;
		RECT	0.03 195.725 0.15 195.875 ;
		RECT	0.03 199.925 0.14 200.275 ;
		RECT	0.03 198.765 0.15 198.915 ;
		RECT	0.03 198.565 0.15 198.715 ;
		RECT	0.03 126.085 0.14 126.435 ;
		RECT	0.03 124.925 0.15 125.075 ;
		RECT	0.03 124.725 0.15 124.875 ;
		RECT	0.03 202.765 0.14 203.115 ;
		RECT	0.03 201.605 0.15 201.755 ;
		RECT	0.03 201.405 0.15 201.555 ;
		RECT	0.03 100.715 0.15 100.865 ;
		RECT	0.03 128.925 0.14 129.275 ;
		RECT	0.03 127.765 0.15 127.915 ;
		RECT	0.03 127.565 0.15 127.715 ;
		RECT	0.03 131.765 0.14 132.115 ;
		RECT	0.03 130.605 0.15 130.755 ;
		RECT	0.03 130.405 0.15 130.555 ;
		RECT	0.03 134.605 0.14 134.955 ;
		RECT	0.03 133.445 0.15 133.595 ;
		RECT	0.03 133.245 0.15 133.395 ;
		RECT	0.03 137.445 0.14 137.795 ;
		RECT	0.03 94.415 0.15 94.565 ;
		RECT	0.03 136.285 0.15 136.435 ;
		RECT	0.03 136.085 0.15 136.235 ;
		RECT	0.03 140.285 0.14 140.635 ;
		RECT	0.03 139.125 0.15 139.275 ;
		RECT	0.03 138.925 0.15 139.075 ;
		RECT	0.03 143.125 0.14 143.475 ;
		RECT	0.03 141.965 0.15 142.115 ;
		RECT	0.03 141.765 0.15 141.915 ;
		RECT	0.03 117.565 0.14 117.915 ;
		RECT	0.03 116.405 0.15 116.555 ;
		RECT	0.03 108.715 0.15 108.865 ;
		RECT	0.03 116.205 0.15 116.355 ;
		RECT	0.03 205.605 0.14 205.955 ;
		RECT	0.03 204.445 0.15 204.595 ;
		RECT	0.03 204.245 0.15 204.395 ;
		RECT	0.03 206.35 0.14 206.7 ;
		RECT	0.03 206.75 0.14 207.1 ;
		RECT	0.03 108.915 0.15 109.065 ;
		RECT	0.03 106.515 0.15 106.665 ;
		RECT	0.03 110.715 0.15 110.865 ;
		RECT	0.03 104.115 0.15 104.265 ;
		RECT	0.03 110.915 0.15 111.065 ;
		RECT	0.03 102.315 0.15 102.465 ;
		RECT	0.03 102.515 0.15 102.665 ;
		RECT	0.03 100.115 0.15 100.265 ;
		RECT	0.03 106.715 0.15 106.865 ;
		RECT	0.03 106.915 0.15 107.065 ;
		RECT	0.03 109.915 0.15 110.065 ;
		RECT	0.03 110.115 0.15 110.265 ;
		RECT	0.03 112.315 0.15 112.465 ;
		RECT	0.03 112.515 0.15 112.665 ;
		RECT	0.03 103.315 0.15 103.465 ;
		RECT	0.03 110.515 0.15 110.665 ;
		RECT	0.03 111.115 0.15 111.265 ;
		RECT	0.03 111.315 0.15 111.465 ;
		RECT	0.03 105.115 0.15 105.265 ;
		RECT	0.03 104.315 0.15 104.465 ;
		RECT	0.03 104.515 0.15 104.665 ;
		RECT	0.03 103.515 0.15 103.665 ;
		RECT	0.03 103.715 0.15 103.865 ;
		RECT	0.03 113.515 0.15 113.665 ;
		RECT	0.03 113.715 0.15 113.865 ;
		RECT	0.03 102.715 0.15 102.865 ;
		RECT	0.03 96.915 0.15 97.065 ;
		RECT	0.03 101.515 0.15 101.665 ;
		RECT	0.03 101.915 0.15 102.065 ;
		RECT	0.03 102.115 0.15 102.265 ;
		RECT	0.03 100.515 0.15 100.665 ;
		RECT	0.03 98.515 0.15 98.665 ;
		RECT	0.03 98.715 0.15 98.865 ;
		RECT	0.03 111.515 0.15 111.665 ;
		RECT	0.03 111.715 0.15 111.865 ;
		RECT	0.03 113.115 0.15 113.265 ;
		RECT	0.03 102.915 0.15 103.065 ;
		RECT	0.03 113.315 0.15 113.465 ;
		RECT	0.03 105.915 0.15 106.065 ;
		RECT	0.03 106.115 0.15 106.265 ;
		RECT	0.03 105.515 0.15 105.665 ;
		RECT	0.03 105.715 0.15 105.865 ;
		RECT	0.03 107.315 0.15 107.465 ;
		RECT	0.03 93.415 0.14 93.765 ;
		RECT	0.03 98.915 0.14 99.265 ;
		RECT	0.03 109.115 0.14 109.465 ;
		RECT	0.03 92.915 0.14 93.265 ;
		RECT	0.03 96.065 0.15 96.215 ;
		RECT	0.03 4.035 0.14 4.385 ;
		RECT	0.03 5.395 0.15 5.545 ;
		RECT	0.03 5.595 0.15 5.745 ;
		RECT	0.03 29.595 0.14 29.945 ;
		RECT	0.03 30.955 0.15 31.105 ;
		RECT	0.03 31.155 0.15 31.305 ;
		RECT	0.03 32.435 0.14 32.785 ;
		RECT	0.03 33.795 0.15 33.945 ;
		RECT	0.03 33.995 0.15 34.145 ;
		RECT	0.03 35.275 0.14 35.625 ;
		RECT	0.03 96.265 0.15 96.415 ;
		RECT	0.03 36.635 0.15 36.785 ;
		RECT	0.03 36.835 0.15 36.985 ;
		RECT	0.03 38.115 0.14 38.465 ;
		RECT	0.03 39.475 0.15 39.625 ;
		RECT	0.03 39.675 0.15 39.825 ;
		RECT	0.03 40.955 0.14 41.305 ;
		RECT	0.03 42.315 0.15 42.465 ;
		RECT	0.03 42.515 0.15 42.665 ;
		RECT	0.03 43.795 0.14 44.145 ;
		RECT	0.03 45.155 0.15 45.305 ;
		RECT	0.03 95.115 0.15 95.265 ;
		RECT	0.03 45.355 0.15 45.505 ;
		RECT	0.03 46.635 0.14 46.985 ;
		RECT	0.03 47.995 0.15 48.145 ;
		RECT	0.03 48.195 0.15 48.345 ;
		RECT	0.03 49.475 0.14 49.825 ;
		RECT	0.03 50.835 0.15 50.985 ;
		RECT	0.03 51.035 0.15 51.185 ;
		RECT	0.03 52.315 0.14 52.665 ;
		RECT	0.03 53.675 0.15 53.825 ;
		RECT	0.03 53.875 0.15 54.025 ;
		LAYER	M3 DESIGNRULEWIDTH 0.1 ;
		RECT	0.2 0 121.075 207.15 ;
		RECT	0 0 0.2 1.595 ;
		RECT	0 2.045 0.2 2.905 ;
		RECT	0 3.355 0.2 4.435 ;
		RECT	0 4.885 0.2 5.745 ;
		RECT	0 6.195 0.2 7.275 ;
		RECT	0 7.725 0.2 8.585 ;
		RECT	0 9.035 0.2 10.115 ;
		RECT	0 10.565 0.2 11.425 ;
		RECT	0 11.875 0.2 12.955 ;
		RECT	0 13.405 0.2 14.265 ;
		RECT	0 14.715 0.2 15.795 ;
		RECT	0 16.245 0.2 17.105 ;
		RECT	0 17.555 0.2 18.635 ;
		RECT	0 19.085 0.2 19.945 ;
		RECT	0 20.395 0.2 21.475 ;
		RECT	0 21.925 0.2 22.785 ;
		RECT	0 23.235 0.2 24.315 ;
		RECT	0 24.765 0.2 25.625 ;
		RECT	0 26.075 0.2 27.155 ;
		RECT	0 27.605 0.2 28.465 ;
		RECT	0 28.915 0.2 29.995 ;
		RECT	0 30.445 0.2 31.305 ;
		RECT	0 31.755 0.2 32.835 ;
		RECT	0 33.285 0.2 34.145 ;
		RECT	0 34.595 0.2 35.675 ;
		RECT	0 36.125 0.2 36.985 ;
		RECT	0 37.435 0.2 38.515 ;
		RECT	0 38.965 0.2 39.825 ;
		RECT	0 40.275 0.2 41.355 ;
		RECT	0 41.805 0.2 42.665 ;
		RECT	0 43.115 0.2 44.195 ;
		RECT	0 44.645 0.2 45.505 ;
		RECT	0 45.955 0.2 47.035 ;
		RECT	0 47.485 0.2 48.345 ;
		RECT	0 48.795 0.2 49.875 ;
		RECT	0 50.325 0.2 51.185 ;
		RECT	0 51.635 0.2 52.715 ;
		RECT	0 53.165 0.2 54.025 ;
		RECT	0 54.475 0.2 55.555 ;
		RECT	0 56.005 0.2 56.865 ;
		RECT	0 57.315 0.2 58.395 ;
		RECT	0 58.845 0.2 59.705 ;
		RECT	0 60.155 0.2 61.235 ;
		RECT	0 61.685 0.2 62.545 ;
		RECT	0 62.995 0.2 64.075 ;
		RECT	0 64.525 0.2 65.385 ;
		RECT	0 65.835 0.2 66.915 ;
		RECT	0 67.365 0.2 68.225 ;
		RECT	0 68.675 0.2 69.755 ;
		RECT	0 70.205 0.2 71.065 ;
		RECT	0 71.515 0.2 72.595 ;
		RECT	0 73.045 0.2 73.905 ;
		RECT	0 74.355 0.2 75.435 ;
		RECT	0 75.885 0.2 76.745 ;
		RECT	0 77.195 0.2 78.275 ;
		RECT	0 78.725 0.2 79.585 ;
		RECT	0 80.035 0.2 81.115 ;
		RECT	0 81.565 0.2 82.425 ;
		RECT	0 82.875 0.2 83.955 ;
		RECT	0 84.405 0.2 85.265 ;
		RECT	0 85.715 0.2 86.795 ;
		RECT	0 87.245 0.2 88.105 ;
		RECT	0 88.555 0.2 89.635 ;
		RECT	0 90.085 0.2 90.945 ;
		RECT	0 91.395 0.2 92.36 ;
		RECT	0 92.81 0.2 93.765 ;
		RECT	0 94.415 0.2 95.565 ;
		RECT	0 96.015 0.2 96.665 ;
		RECT	0 96.915 0.2 97.065 ;
		RECT	0 97.315 0.2 97.565 ;
		RECT	0 98.465 0.2 99.265 ;
		RECT	0 99.715 0.2 99.865 ;
		RECT	0 100.115 0.2 100.265 ;
		RECT	0 100.515 0.2 100.865 ;
		RECT	0 101.115 0.2 101.265 ;
		RECT	0 101.515 0.2 101.665 ;
		RECT	0 101.915 0.2 103.065 ;
		RECT	0 103.315 0.2 105.265 ;
		RECT	0 105.515 0.2 106.265 ;
		RECT	0 106.515 0.2 107.065 ;
		RECT	0 107.315 0.2 107.865 ;
		RECT	0 108.115 0.2 108.265 ;
		RECT	0 108.715 0.2 109.665 ;
		RECT	0 109.915 0.2 110.265 ;
		RECT	0 110.515 0.2 114.265 ;
		RECT	0 115.115 0.2 115.755 ;
		RECT	0 116.205 0.2 117.065 ;
		RECT	0 117.515 0.2 118.595 ;
		RECT	0 119.045 0.2 119.905 ;
		RECT	0 120.355 0.2 121.435 ;
		RECT	0 121.885 0.2 122.745 ;
		RECT	0 123.195 0.2 124.275 ;
		RECT	0 124.725 0.2 125.585 ;
		RECT	0 126.035 0.2 127.115 ;
		RECT	0 127.565 0.2 128.425 ;
		RECT	0 128.875 0.2 129.955 ;
		RECT	0 130.405 0.2 131.265 ;
		RECT	0 131.715 0.2 132.795 ;
		RECT	0 133.245 0.2 134.105 ;
		RECT	0 134.555 0.2 135.635 ;
		RECT	0 136.085 0.2 136.945 ;
		RECT	0 137.395 0.2 138.475 ;
		RECT	0 138.925 0.2 139.785 ;
		RECT	0 140.235 0.2 141.315 ;
		RECT	0 141.765 0.2 142.625 ;
		RECT	0 143.075 0.2 144.155 ;
		RECT	0 144.605 0.2 145.465 ;
		RECT	0 145.915 0.2 146.995 ;
		RECT	0 147.445 0.2 148.305 ;
		RECT	0 148.755 0.2 149.835 ;
		RECT	0 150.285 0.2 151.145 ;
		RECT	0 151.595 0.2 152.675 ;
		RECT	0 153.125 0.2 153.985 ;
		RECT	0 154.435 0.2 155.515 ;
		RECT	0 155.965 0.2 156.825 ;
		RECT	0 157.275 0.2 158.355 ;
		RECT	0 158.805 0.2 159.665 ;
		RECT	0 160.115 0.2 161.195 ;
		RECT	0 161.645 0.2 162.505 ;
		RECT	0 162.955 0.2 164.035 ;
		RECT	0 164.485 0.2 165.345 ;
		RECT	0 165.795 0.2 166.875 ;
		RECT	0 167.325 0.2 168.185 ;
		RECT	0 168.635 0.2 169.715 ;
		RECT	0 170.165 0.2 171.025 ;
		RECT	0 171.475 0.2 172.555 ;
		RECT	0 173.005 0.2 173.865 ;
		RECT	0 174.315 0.2 175.395 ;
		RECT	0 175.845 0.2 176.705 ;
		RECT	0 177.155 0.2 178.235 ;
		RECT	0 178.685 0.2 179.545 ;
		RECT	0 179.995 0.2 181.075 ;
		RECT	0 181.525 0.2 182.385 ;
		RECT	0 182.835 0.2 183.915 ;
		RECT	0 184.365 0.2 185.225 ;
		RECT	0 185.675 0.2 186.755 ;
		RECT	0 187.205 0.2 188.065 ;
		RECT	0 188.515 0.2 189.595 ;
		RECT	0 190.045 0.2 190.905 ;
		RECT	0 191.355 0.2 192.435 ;
		RECT	0 192.885 0.2 193.745 ;
		RECT	0 194.195 0.2 195.275 ;
		RECT	0 195.725 0.2 196.585 ;
		RECT	0 197.035 0.2 198.115 ;
		RECT	0 198.565 0.2 199.425 ;
		RECT	0 199.875 0.2 200.955 ;
		RECT	0 201.405 0.2 202.265 ;
		RECT	0 202.715 0.2 203.795 ;
		RECT	0 204.245 0.2 205.105 ;
		RECT	0 205.555 0.2 207.15 ;
		RECT	0.03 109.515 0.15 109.665 ;
		RECT	0.03 108.115 0.15 108.265 ;
		RECT	0.03 103.915 0.15 104.065 ;
		RECT	0.03 104.115 0.15 104.265 ;
		RECT	0.03 103.315 0.15 103.465 ;
		RECT	0.03 102.715 0.15 102.865 ;
		RECT	0.03 102.915 0.15 103.065 ;
		RECT	0.03 96.065 0.15 96.215 ;
		RECT	0.03 96.265 0.15 96.415 ;
		RECT	0.03 95.115 0.15 95.265 ;
		RECT	0.03 95.315 0.15 95.465 ;
		RECT	0.03 94.715 0.15 94.865 ;
		RECT	0.03 94.915 0.15 95.065 ;
		RECT	0.03 112.715 0.15 112.865 ;
		RECT	0.03 112.915 0.15 113.065 ;
		RECT	0.03 104.715 0.15 104.865 ;
		RECT	0.03 104.915 0.15 105.065 ;
		RECT	0.03 101.115 0.15 101.265 ;
		RECT	0.03 113.915 0.15 114.065 ;
		RECT	0.03 114.115 0.15 114.265 ;
		RECT	0.03 111.915 0.15 112.065 ;
		RECT	0.03 112.115 0.15 112.265 ;
		RECT	0.03 96.515 0.15 96.665 ;
		RECT	0.03 97.415 0.15 97.565 ;
		RECT	0.03 100.715 0.15 100.865 ;
		RECT	0.03 94.415 0.15 94.565 ;
		RECT	0.03 108.715 0.15 108.865 ;
		RECT	0.03 108.915 0.15 109.065 ;
		RECT	0.03 106.515 0.15 106.665 ;
		RECT	0.03 110.715 0.15 110.865 ;
		RECT	0.03 110.915 0.15 111.065 ;
		RECT	0.03 102.315 0.15 102.465 ;
		RECT	0.03 102.515 0.15 102.665 ;
		RECT	0.03 100.115 0.15 100.265 ;
		RECT	0.03 106.715 0.15 106.865 ;
		RECT	0.03 106.915 0.15 107.065 ;
		RECT	0.03 109.915 0.15 110.065 ;
		RECT	0.03 110.115 0.15 110.265 ;
		RECT	0.03 112.315 0.15 112.465 ;
		RECT	0.03 112.515 0.15 112.665 ;
		RECT	0.03 110.515 0.15 110.665 ;
		RECT	0.03 111.115 0.15 111.265 ;
		RECT	0.03 111.315 0.15 111.465 ;
		RECT	0.03 105.115 0.15 105.265 ;
		RECT	0.03 104.315 0.15 104.465 ;
		RECT	0.03 104.515 0.15 104.665 ;
		RECT	0.03 103.515 0.15 103.665 ;
		RECT	0.03 103.715 0.15 103.865 ;
		RECT	0.03 113.515 0.15 113.665 ;
		RECT	0.03 113.715 0.15 113.865 ;
		RECT	0.03 96.915 0.15 97.065 ;
		RECT	0.03 101.515 0.15 101.665 ;
		RECT	0.03 101.915 0.15 102.065 ;
		RECT	0.03 102.115 0.15 102.265 ;
		RECT	0.03 100.515 0.15 100.665 ;
		RECT	0.03 98.515 0.15 98.665 ;
		RECT	0.03 98.715 0.15 98.865 ;
		RECT	0.03 111.515 0.15 111.665 ;
		RECT	0.03 111.715 0.15 111.865 ;
		RECT	0.03 113.115 0.15 113.265 ;
		RECT	0.03 113.315 0.15 113.465 ;
		RECT	0.03 105.915 0.15 106.065 ;
		RECT	0.03 106.115 0.15 106.265 ;
		RECT	0.03 105.515 0.15 105.665 ;
		RECT	0.03 105.715 0.15 105.865 ;
		RECT	0.03 107.315 0.15 107.465 ;
		RECT	0.03 93.415 0.14 93.765 ;
		RECT	0.03 98.915 0.14 99.265 ;
		RECT	0.03 109.115 0.14 109.465 ;
		RECT	0.03 92.915 0.14 93.265 ;
		RECT	0.03 4.035 0.14 4.385 ;
		RECT	0.03 5.395 0.15 5.545 ;
		RECT	0.03 5.595 0.15 5.745 ;
		RECT	0.03 29.595 0.14 29.945 ;
		RECT	0.03 30.955 0.15 31.105 ;
		RECT	0.03 31.155 0.15 31.305 ;
		RECT	0.03 32.435 0.14 32.785 ;
		RECT	0.03 33.795 0.15 33.945 ;
		RECT	0.03 33.995 0.15 34.145 ;
		RECT	0.03 35.275 0.14 35.625 ;
		RECT	0.03 36.635 0.15 36.785 ;
		RECT	0.03 36.835 0.15 36.985 ;
		RECT	0.03 38.115 0.14 38.465 ;
		RECT	0.03 39.475 0.15 39.625 ;
		RECT	0.03 39.675 0.15 39.825 ;
		RECT	0.03 40.955 0.14 41.305 ;
		RECT	0.03 42.315 0.15 42.465 ;
		RECT	0.03 42.515 0.15 42.665 ;
		RECT	0.03 43.795 0.14 44.145 ;
		RECT	0.03 45.155 0.15 45.305 ;
		RECT	0.03 45.355 0.15 45.505 ;
		RECT	0.03 46.635 0.14 46.985 ;
		RECT	0.03 47.995 0.15 48.145 ;
		RECT	0.03 48.195 0.15 48.345 ;
		RECT	0.03 49.475 0.14 49.825 ;
		RECT	0.03 50.835 0.15 50.985 ;
		RECT	0.03 51.035 0.15 51.185 ;
		RECT	0.03 52.315 0.14 52.665 ;
		RECT	0.03 53.675 0.15 53.825 ;
		RECT	0.03 53.875 0.15 54.025 ;
		RECT	0.03 55.155 0.14 55.505 ;
		RECT	0.03 56.515 0.15 56.665 ;
		RECT	0.03 56.715 0.15 56.865 ;
		RECT	0.03 6.875 0.14 7.225 ;
		RECT	0.03 8.235 0.15 8.385 ;
		RECT	0.03 8.435 0.15 8.585 ;
		RECT	0.03 57.995 0.14 58.345 ;
		RECT	0.03 59.355 0.15 59.505 ;
		RECT	0.03 59.555 0.15 59.705 ;
		RECT	0.03 60.835 0.14 61.185 ;
		RECT	0.03 62.195 0.15 62.345 ;
		RECT	0.03 62.395 0.15 62.545 ;
		RECT	0.03 63.675 0.14 64.025 ;
		RECT	0.03 65.035 0.15 65.185 ;
		RECT	0.03 65.235 0.15 65.385 ;
		RECT	0.03 66.515 0.14 66.865 ;
		RECT	0.03 67.875 0.15 68.025 ;
		RECT	0.03 68.075 0.15 68.225 ;
		RECT	0.03 69.355 0.14 69.705 ;
		RECT	0.03 70.715 0.15 70.865 ;
		RECT	0.03 70.915 0.15 71.065 ;
		RECT	0.03 72.195 0.14 72.545 ;
		RECT	0.03 73.555 0.15 73.705 ;
		RECT	0.03 73.755 0.15 73.905 ;
		RECT	0.03 75.035 0.14 75.385 ;
		RECT	0.03 76.395 0.15 76.545 ;
		RECT	0.03 76.595 0.15 76.745 ;
		RECT	0.03 77.875 0.14 78.225 ;
		RECT	0.03 79.235 0.15 79.385 ;
		RECT	0.03 79.435 0.15 79.585 ;
		RECT	0.03 80.715 0.14 81.065 ;
		RECT	0.03 82.075 0.15 82.225 ;
		RECT	0.03 82.275 0.15 82.425 ;
		RECT	0.03 83.555 0.14 83.905 ;
		RECT	0.03 84.915 0.15 85.065 ;
		RECT	0.03 85.115 0.15 85.265 ;
		RECT	0.03 9.715 0.14 10.065 ;
		RECT	0.03 11.075 0.15 11.225 ;
		RECT	0.03 11.275 0.15 11.425 ;
		RECT	0.03 86.395 0.14 86.745 ;
		RECT	0.03 87.755 0.15 87.905 ;
		RECT	0.03 87.955 0.15 88.105 ;
		RECT	0.03 12.555 0.14 12.905 ;
		RECT	0.03 13.915 0.15 14.065 ;
		RECT	0.03 14.115 0.15 14.265 ;
		RECT	0.03 15.395 0.14 15.745 ;
		RECT	0.03 16.755 0.15 16.905 ;
		RECT	0.03 16.955 0.15 17.105 ;
		RECT	0.03 18.235 0.14 18.585 ;
		RECT	0.03 19.595 0.15 19.745 ;
		RECT	0.03 19.795 0.15 19.945 ;
		RECT	0.03 21.075 0.14 21.425 ;
		RECT	0.03 22.435 0.15 22.585 ;
		RECT	0.03 22.635 0.15 22.785 ;
		RECT	0.03 23.915 0.14 24.265 ;
		RECT	0.03 25.275 0.15 25.425 ;
		RECT	0.03 25.475 0.15 25.625 ;
		RECT	0.03 26.755 0.14 27.105 ;
		RECT	0.03 28.115 0.15 28.265 ;
		RECT	0.03 28.315 0.15 28.465 ;
		RECT	0.03 1.195 0.14 1.545 ;
		RECT	0.03 2.555 0.15 2.705 ;
		RECT	0.03 2.755 0.15 2.905 ;
		RECT	0.03 89.235 0.14 89.585 ;
		RECT	0.03 90.595 0.15 90.745 ;
		RECT	0.03 90.795 0.15 90.945 ;
		RECT	0.03 0.45 0.14 0.8 ;
		RECT	0.03 0.05 0.14 0.4 ;
		RECT	0.03 120.405 0.14 120.755 ;
		RECT	0.03 119.245 0.15 119.395 ;
		RECT	0.03 119.045 0.15 119.195 ;
		RECT	0.03 145.965 0.14 146.315 ;
		RECT	0.03 144.805 0.15 144.955 ;
		RECT	0.03 144.605 0.15 144.755 ;
		RECT	0.03 148.805 0.14 149.155 ;
		RECT	0.03 147.645 0.15 147.795 ;
		RECT	0.03 147.445 0.15 147.595 ;
		RECT	0.03 151.645 0.14 151.995 ;
		RECT	0.03 150.485 0.15 150.635 ;
		RECT	0.03 150.285 0.15 150.435 ;
		RECT	0.03 154.485 0.14 154.835 ;
		RECT	0.03 153.325 0.15 153.475 ;
		RECT	0.03 153.125 0.15 153.275 ;
		RECT	0.03 157.325 0.14 157.675 ;
		RECT	0.03 156.165 0.15 156.315 ;
		RECT	0.03 155.965 0.15 156.115 ;
		RECT	0.03 160.165 0.14 160.515 ;
		RECT	0.03 159.005 0.15 159.155 ;
		RECT	0.03 158.805 0.15 158.955 ;
		RECT	0.03 163.005 0.14 163.355 ;
		RECT	0.03 161.845 0.15 161.995 ;
		RECT	0.03 161.645 0.15 161.795 ;
		RECT	0.03 165.845 0.14 166.195 ;
		RECT	0.03 164.685 0.15 164.835 ;
		RECT	0.03 164.485 0.15 164.635 ;
		RECT	0.03 168.685 0.14 169.035 ;
		RECT	0.03 167.525 0.15 167.675 ;
		RECT	0.03 167.325 0.15 167.475 ;
		RECT	0.03 171.525 0.14 171.875 ;
		RECT	0.03 170.365 0.15 170.515 ;
		RECT	0.03 170.165 0.15 170.315 ;
		RECT	0.03 123.245 0.14 123.595 ;
		RECT	0.03 122.085 0.15 122.235 ;
		RECT	0.03 121.885 0.15 122.035 ;
		RECT	0.03 174.365 0.14 174.715 ;
		RECT	0.03 173.205 0.15 173.355 ;
		RECT	0.03 173.005 0.15 173.155 ;
		RECT	0.03 177.205 0.14 177.555 ;
		RECT	0.03 176.045 0.15 176.195 ;
		RECT	0.03 175.845 0.15 175.995 ;
		RECT	0.03 180.045 0.14 180.395 ;
		RECT	0.03 178.885 0.15 179.035 ;
		RECT	0.03 178.685 0.15 178.835 ;
		RECT	0.03 182.885 0.14 183.235 ;
		RECT	0.03 181.725 0.15 181.875 ;
		RECT	0.03 181.525 0.15 181.675 ;
		RECT	0.03 185.725 0.14 186.075 ;
		RECT	0.03 184.565 0.15 184.715 ;
		RECT	0.03 184.365 0.15 184.515 ;
		RECT	0.03 188.565 0.14 188.915 ;
		RECT	0.03 187.405 0.15 187.555 ;
		RECT	0.03 187.205 0.15 187.355 ;
		RECT	0.03 191.405 0.14 191.755 ;
		RECT	0.03 190.245 0.15 190.395 ;
		RECT	0.03 190.045 0.15 190.195 ;
		RECT	0.03 194.245 0.14 194.595 ;
		RECT	0.03 193.085 0.15 193.235 ;
		RECT	0.03 192.885 0.15 193.035 ;
		RECT	0.03 197.085 0.14 197.435 ;
		RECT	0.03 195.925 0.15 196.075 ;
		RECT	0.03 195.725 0.15 195.875 ;
		RECT	0.03 199.925 0.14 200.275 ;
		RECT	0.03 198.765 0.15 198.915 ;
		RECT	0.03 198.565 0.15 198.715 ;
		RECT	0.03 126.085 0.14 126.435 ;
		RECT	0.03 124.925 0.15 125.075 ;
		RECT	0.03 124.725 0.15 124.875 ;
		RECT	0.03 202.765 0.14 203.115 ;
		RECT	0.03 201.605 0.15 201.755 ;
		RECT	0.03 201.405 0.15 201.555 ;
		RECT	0.03 128.925 0.14 129.275 ;
		RECT	0.03 127.765 0.15 127.915 ;
		RECT	0.03 127.565 0.15 127.715 ;
		RECT	0.03 131.765 0.14 132.115 ;
		RECT	0.03 130.605 0.15 130.755 ;
		RECT	0.03 130.405 0.15 130.555 ;
		RECT	0.03 134.605 0.14 134.955 ;
		RECT	0.03 133.445 0.15 133.595 ;
		RECT	0.03 133.245 0.15 133.395 ;
		RECT	0.03 137.445 0.14 137.795 ;
		RECT	0.03 136.285 0.15 136.435 ;
		RECT	0.03 136.085 0.15 136.235 ;
		RECT	0.03 140.285 0.14 140.635 ;
		RECT	0.03 139.125 0.15 139.275 ;
		RECT	0.03 138.925 0.15 139.075 ;
		RECT	0.03 143.125 0.14 143.475 ;
		RECT	0.03 141.965 0.15 142.115 ;
		RECT	0.03 141.765 0.15 141.915 ;
		RECT	0.03 117.565 0.14 117.915 ;
		RECT	0.03 116.405 0.15 116.555 ;
		RECT	0.03 116.205 0.15 116.355 ;
		RECT	0.03 205.605 0.14 205.955 ;
		RECT	0.03 204.445 0.15 204.595 ;
		RECT	0.03 204.245 0.15 204.395 ;
		RECT	0.03 206.35 0.14 206.7 ;
		RECT	0.03 206.75 0.14 207.1 ;
		LAYER	M4 DESIGNRULEWIDTH 0.1 ;
		RECT	0.39 0.88 120.775 1.07 ;
		RECT	120.775 0.88 121.075 1.07 ;
		RECT	0.39 1.38 120.775 2.345 ;
		RECT	120.775 1.38 121.075 2.345 ;
		RECT	0.39 2.655 120.775 3.16 ;
		RECT	120.775 2.655 121.075 3.16 ;
		RECT	0.39 3.47 120.775 3.91 ;
		RECT	120.775 3.47 121.075 3.91 ;
		RECT	0.39 4.22 120.775 5.185 ;
		RECT	120.775 4.22 121.075 5.185 ;
		RECT	0.39 5.495 120.775 6 ;
		RECT	120.775 5.495 121.075 6 ;
		RECT	0.39 6.31 120.775 6.75 ;
		RECT	120.775 6.31 121.075 6.75 ;
		RECT	0.39 7.06 120.775 8.025 ;
		RECT	120.775 7.06 121.075 8.025 ;
		RECT	0.39 8.335 120.775 8.84 ;
		RECT	120.775 8.335 121.075 8.84 ;
		RECT	0.39 9.15 120.775 9.59 ;
		RECT	120.775 9.15 121.075 9.59 ;
		RECT	0.39 9.9 120.775 10.865 ;
		RECT	120.775 9.9 121.075 10.865 ;
		RECT	0.39 11.175 120.775 11.68 ;
		RECT	120.775 11.175 121.075 11.68 ;
		RECT	0.39 11.99 120.775 12.43 ;
		RECT	120.775 11.99 121.075 12.43 ;
		RECT	0.39 12.74 120.775 13.705 ;
		RECT	120.775 12.74 121.075 13.705 ;
		RECT	0.39 14.015 120.775 14.52 ;
		RECT	120.775 14.015 121.075 14.52 ;
		RECT	0.39 14.83 120.775 15.27 ;
		RECT	120.775 14.83 121.075 15.27 ;
		RECT	0.39 15.58 120.775 16.545 ;
		RECT	120.775 15.58 121.075 16.545 ;
		RECT	0.39 16.855 120.775 17.36 ;
		RECT	120.775 16.855 121.075 17.36 ;
		RECT	0.39 17.67 120.775 18.11 ;
		RECT	120.775 17.67 121.075 18.11 ;
		RECT	0.39 18.42 120.775 19.385 ;
		RECT	120.775 18.42 121.075 19.385 ;
		RECT	0.39 19.695 120.775 20.2 ;
		RECT	120.775 19.695 121.075 20.2 ;
		RECT	0.39 20.51 120.775 20.95 ;
		RECT	120.775 20.51 121.075 20.95 ;
		RECT	0.39 21.26 120.775 22.225 ;
		RECT	120.775 21.26 121.075 22.225 ;
		RECT	0.39 22.535 120.775 23.04 ;
		RECT	120.775 22.535 121.075 23.04 ;
		RECT	0.39 23.35 120.775 23.79 ;
		RECT	120.775 23.35 121.075 23.79 ;
		RECT	0.39 24.1 120.775 25.065 ;
		RECT	120.775 24.1 121.075 25.065 ;
		RECT	0.39 25.375 120.775 25.88 ;
		RECT	120.775 25.375 121.075 25.88 ;
		RECT	0.39 26.19 120.775 26.63 ;
		RECT	120.775 26.19 121.075 26.63 ;
		RECT	0.39 26.94 120.775 27.905 ;
		RECT	120.775 26.94 121.075 27.905 ;
		RECT	0.39 28.215 120.775 28.72 ;
		RECT	120.775 28.215 121.075 28.72 ;
		RECT	0.39 29.03 120.775 29.47 ;
		RECT	120.775 29.03 121.075 29.47 ;
		RECT	0.39 29.78 120.775 30.745 ;
		RECT	120.775 29.78 121.075 30.745 ;
		RECT	0.39 31.055 120.775 31.56 ;
		RECT	120.775 31.055 121.075 31.56 ;
		RECT	0.39 31.87 120.775 32.31 ;
		RECT	120.775 31.87 121.075 32.31 ;
		RECT	0.39 32.62 120.775 33.585 ;
		RECT	120.775 32.62 121.075 33.585 ;
		RECT	0.39 33.895 120.775 34.4 ;
		RECT	120.775 33.895 121.075 34.4 ;
		RECT	0.39 34.71 120.775 35.15 ;
		RECT	120.775 34.71 121.075 35.15 ;
		RECT	0.39 35.46 120.775 36.425 ;
		RECT	120.775 35.46 121.075 36.425 ;
		RECT	0.39 36.735 120.775 37.24 ;
		RECT	120.775 36.735 121.075 37.24 ;
		RECT	0.39 37.55 120.775 37.99 ;
		RECT	120.775 37.55 121.075 37.99 ;
		RECT	0.39 38.3 120.775 39.265 ;
		RECT	120.775 38.3 121.075 39.265 ;
		RECT	0.39 39.575 120.775 40.08 ;
		RECT	120.775 39.575 121.075 40.08 ;
		RECT	0.39 40.39 120.775 40.83 ;
		RECT	120.775 40.39 121.075 40.83 ;
		RECT	0.39 41.14 120.775 42.105 ;
		RECT	120.775 41.14 121.075 42.105 ;
		RECT	0.39 42.415 120.775 42.92 ;
		RECT	120.775 42.415 121.075 42.92 ;
		RECT	0.39 43.23 120.775 43.67 ;
		RECT	120.775 43.23 121.075 43.67 ;
		RECT	0.39 43.98 120.775 44.945 ;
		RECT	120.775 43.98 121.075 44.945 ;
		RECT	0.39 45.255 120.775 45.76 ;
		RECT	120.775 45.255 121.075 45.76 ;
		RECT	0.39 46.07 120.775 46.51 ;
		RECT	120.775 46.07 121.075 46.51 ;
		RECT	0.39 46.82 120.775 47.785 ;
		RECT	120.775 46.82 121.075 47.785 ;
		RECT	0.39 48.095 120.775 48.6 ;
		RECT	120.775 48.095 121.075 48.6 ;
		RECT	0.39 48.91 120.775 49.35 ;
		RECT	120.775 48.91 121.075 49.35 ;
		RECT	0.39 49.66 120.775 50.625 ;
		RECT	120.775 49.66 121.075 50.625 ;
		RECT	0.39 50.935 120.775 51.44 ;
		RECT	120.775 50.935 121.075 51.44 ;
		RECT	0.39 51.75 120.775 52.19 ;
		RECT	120.775 51.75 121.075 52.19 ;
		RECT	0.39 52.5 120.775 53.465 ;
		RECT	120.775 52.5 121.075 53.465 ;
		RECT	0.39 53.775 120.775 54.28 ;
		RECT	120.775 53.775 121.075 54.28 ;
		RECT	0.39 54.59 120.775 55.03 ;
		RECT	120.775 54.59 121.075 55.03 ;
		RECT	0.39 55.34 120.775 56.305 ;
		RECT	120.775 55.34 121.075 56.305 ;
		RECT	0.39 56.615 120.775 57.12 ;
		RECT	120.775 56.615 121.075 57.12 ;
		RECT	0.39 57.43 120.775 57.87 ;
		RECT	120.775 57.43 121.075 57.87 ;
		RECT	0.39 58.18 120.775 59.145 ;
		RECT	120.775 58.18 121.075 59.145 ;
		RECT	0.39 59.455 120.775 59.96 ;
		RECT	120.775 59.455 121.075 59.96 ;
		RECT	0.39 60.27 120.775 60.71 ;
		RECT	120.775 60.27 121.075 60.71 ;
		RECT	0.39 61.02 120.775 61.985 ;
		RECT	120.775 61.02 121.075 61.985 ;
		RECT	0.39 62.295 120.775 62.8 ;
		RECT	120.775 62.295 121.075 62.8 ;
		RECT	0.39 63.11 120.775 63.55 ;
		RECT	120.775 63.11 121.075 63.55 ;
		RECT	0.39 63.86 120.775 64.825 ;
		RECT	120.775 63.86 121.075 64.825 ;
		RECT	0.39 65.135 120.775 65.64 ;
		RECT	120.775 65.135 121.075 65.64 ;
		RECT	0.39 65.95 120.775 66.39 ;
		RECT	120.775 65.95 121.075 66.39 ;
		RECT	0.39 66.7 120.775 67.665 ;
		RECT	120.775 66.7 121.075 67.665 ;
		RECT	0.39 67.975 120.775 68.48 ;
		RECT	120.775 67.975 121.075 68.48 ;
		RECT	0.39 68.79 120.775 69.23 ;
		RECT	120.775 68.79 121.075 69.23 ;
		RECT	0.39 69.54 120.775 70.505 ;
		RECT	120.775 69.54 121.075 70.505 ;
		RECT	0.39 70.815 120.775 71.32 ;
		RECT	120.775 70.815 121.075 71.32 ;
		RECT	0.39 71.63 120.775 72.07 ;
		RECT	120.775 71.63 121.075 72.07 ;
		RECT	0.39 72.38 120.775 73.345 ;
		RECT	120.775 72.38 121.075 73.345 ;
		RECT	0.39 73.655 120.775 74.16 ;
		RECT	120.775 73.655 121.075 74.16 ;
		RECT	0.39 74.47 120.775 74.91 ;
		RECT	120.775 74.47 121.075 74.91 ;
		RECT	0.39 75.22 120.775 76.185 ;
		RECT	120.775 75.22 121.075 76.185 ;
		RECT	0.39 76.495 120.775 77 ;
		RECT	120.775 76.495 121.075 77 ;
		RECT	0.39 77.31 120.775 77.75 ;
		RECT	120.775 77.31 121.075 77.75 ;
		RECT	0.39 78.06 120.775 79.025 ;
		RECT	120.775 78.06 121.075 79.025 ;
		RECT	0.39 79.335 120.775 79.84 ;
		RECT	120.775 79.335 121.075 79.84 ;
		RECT	0.39 80.15 120.775 80.59 ;
		RECT	120.775 80.15 121.075 80.59 ;
		RECT	0.39 80.9 120.775 81.865 ;
		RECT	120.775 80.9 121.075 81.865 ;
		RECT	0.39 82.175 120.775 82.68 ;
		RECT	120.775 82.175 121.075 82.68 ;
		RECT	0.39 82.99 120.775 83.43 ;
		RECT	120.775 82.99 121.075 83.43 ;
		RECT	0.39 83.74 120.775 84.705 ;
		RECT	120.775 83.74 121.075 84.705 ;
		RECT	0.39 85.015 120.775 85.52 ;
		RECT	120.775 85.015 121.075 85.52 ;
		RECT	0.39 85.83 120.775 86.27 ;
		RECT	120.775 85.83 121.075 86.27 ;
		RECT	0.39 86.58 120.775 87.545 ;
		RECT	120.775 86.58 121.075 87.545 ;
		RECT	0.39 87.855 120.775 88.36 ;
		RECT	120.775 87.855 121.075 88.36 ;
		RECT	0.39 88.67 120.775 89.11 ;
		RECT	120.775 88.67 121.075 89.11 ;
		RECT	0.39 89.42 120.775 90.385 ;
		RECT	120.775 89.42 121.075 90.385 ;
		RECT	0.39 90.695 120.775 91.2 ;
		RECT	120.775 90.695 121.075 91.2 ;
		RECT	0.39 91.51 120.775 91.83 ;
		RECT	120.775 91.51 121.075 91.83 ;
		RECT	0.39 92.905 120.775 94.06 ;
		RECT	120.775 92.905 121.075 94.06 ;
		RECT	0.39 94.37 120.775 94.52 ;
		RECT	120.775 94.37 121.075 94.52 ;
		RECT	0.39 95.06 120.775 95.58 ;
		RECT	120.775 95.06 121.075 95.58 ;
		RECT	0.39 96.12 120.775 96.94 ;
		RECT	120.775 96.12 121.075 96.94 ;
		RECT	0.39 97.48 120.775 98.53 ;
		RECT	120.775 97.48 121.075 98.53 ;
		RECT	0.39 99.07 120.775 100.2 ;
		RECT	120.775 99.07 121.075 100.2 ;
		RECT	0.39 100.74 120.775 101.07 ;
		RECT	120.775 100.74 121.075 101.07 ;
		RECT	0.39 101.24 120.775 101.79 ;
		RECT	120.775 101.24 121.075 101.79 ;
		RECT	0.39 102.33 120.775 103.38 ;
		RECT	120.775 102.33 121.075 103.38 ;
		RECT	0.39 104.15 120.775 105.2 ;
		RECT	120.775 104.15 121.075 105.2 ;
		RECT	0.39 105.74 120.775 106.79 ;
		RECT	120.775 105.74 121.075 106.79 ;
		RECT	0.39 107.33 120.775 108.43 ;
		RECT	120.775 107.33 121.075 108.43 ;
		RECT	0.39 108.97 120.775 109.9 ;
		RECT	120.775 108.97 121.075 109.9 ;
		RECT	0.39 110.56 120.775 111.61 ;
		RECT	120.775 110.56 121.075 111.61 ;
		RECT	0.39 112.15 120.775 112.67 ;
		RECT	120.775 112.15 121.075 112.67 ;
		RECT	0.39 113.21 120.775 113.36 ;
		RECT	120.775 113.21 121.075 113.36 ;
		RECT	0.39 113.67 120.775 114.82 ;
		RECT	120.775 113.67 121.075 114.82 ;
		RECT	0.39 115.38 120.775 115.64 ;
		RECT	120.775 115.38 121.075 115.64 ;
		RECT	0.39 115.95 120.775 116.455 ;
		RECT	120.775 115.95 121.075 116.455 ;
		RECT	0.39 116.765 120.775 117.73 ;
		RECT	120.775 116.765 121.075 117.73 ;
		RECT	0.39 118.04 120.775 118.48 ;
		RECT	120.775 118.04 121.075 118.48 ;
		RECT	0.39 118.79 120.775 119.295 ;
		RECT	120.775 118.79 121.075 119.295 ;
		RECT	0.39 119.605 120.775 120.57 ;
		RECT	120.775 119.605 121.075 120.57 ;
		RECT	0.39 120.88 120.775 121.32 ;
		RECT	120.775 120.88 121.075 121.32 ;
		RECT	0.39 121.63 120.775 122.135 ;
		RECT	120.775 121.63 121.075 122.135 ;
		RECT	0.39 122.445 120.775 123.41 ;
		RECT	120.775 122.445 121.075 123.41 ;
		RECT	0.39 123.72 120.775 124.16 ;
		RECT	120.775 123.72 121.075 124.16 ;
		RECT	0.39 124.47 120.775 124.975 ;
		RECT	120.775 124.47 121.075 124.975 ;
		RECT	0.39 125.285 120.775 126.25 ;
		RECT	120.775 125.285 121.075 126.25 ;
		RECT	0.39 126.56 120.775 127 ;
		RECT	120.775 126.56 121.075 127 ;
		RECT	0.39 127.31 120.775 127.815 ;
		RECT	120.775 127.31 121.075 127.815 ;
		RECT	0.39 128.125 120.775 129.09 ;
		RECT	120.775 128.125 121.075 129.09 ;
		RECT	0.39 129.4 120.775 129.84 ;
		RECT	120.775 129.4 121.075 129.84 ;
		RECT	0.39 130.15 120.775 130.655 ;
		RECT	120.775 130.15 121.075 130.655 ;
		RECT	0.39 130.965 120.775 131.93 ;
		RECT	120.775 130.965 121.075 131.93 ;
		RECT	0.39 132.24 120.775 132.68 ;
		RECT	120.775 132.24 121.075 132.68 ;
		RECT	0.39 132.99 120.775 133.495 ;
		RECT	120.775 132.99 121.075 133.495 ;
		RECT	0.39 133.805 120.775 134.77 ;
		RECT	120.775 133.805 121.075 134.77 ;
		RECT	0.39 135.08 120.775 135.52 ;
		RECT	120.775 135.08 121.075 135.52 ;
		RECT	0.39 135.83 120.775 136.335 ;
		RECT	120.775 135.83 121.075 136.335 ;
		RECT	0.39 136.645 120.775 137.61 ;
		RECT	120.775 136.645 121.075 137.61 ;
		RECT	0.39 137.92 120.775 138.36 ;
		RECT	120.775 137.92 121.075 138.36 ;
		RECT	0.39 138.67 120.775 139.175 ;
		RECT	120.775 138.67 121.075 139.175 ;
		RECT	0.39 139.485 120.775 140.45 ;
		RECT	120.775 139.485 121.075 140.45 ;
		RECT	0.39 140.76 120.775 141.2 ;
		RECT	120.775 140.76 121.075 141.2 ;
		RECT	0.39 141.51 120.775 142.015 ;
		RECT	120.775 141.51 121.075 142.015 ;
		RECT	0.39 142.325 120.775 143.29 ;
		RECT	120.775 142.325 121.075 143.29 ;
		RECT	0.39 143.6 120.775 144.04 ;
		RECT	120.775 143.6 121.075 144.04 ;
		RECT	0.39 144.35 120.775 144.855 ;
		RECT	120.775 144.35 121.075 144.855 ;
		RECT	0.39 145.165 120.775 146.13 ;
		RECT	120.775 145.165 121.075 146.13 ;
		RECT	0.39 146.44 120.775 146.88 ;
		RECT	120.775 146.44 121.075 146.88 ;
		RECT	0.39 147.19 120.775 147.695 ;
		RECT	120.775 147.19 121.075 147.695 ;
		RECT	0.39 148.005 120.775 148.97 ;
		RECT	120.775 148.005 121.075 148.97 ;
		RECT	0.39 149.28 120.775 149.72 ;
		RECT	120.775 149.28 121.075 149.72 ;
		RECT	0.39 150.03 120.775 150.535 ;
		RECT	120.775 150.03 121.075 150.535 ;
		RECT	0.39 150.845 120.775 151.81 ;
		RECT	120.775 150.845 121.075 151.81 ;
		RECT	0.39 152.12 120.775 152.56 ;
		RECT	120.775 152.12 121.075 152.56 ;
		RECT	0.39 152.87 120.775 153.375 ;
		RECT	120.775 152.87 121.075 153.375 ;
		RECT	0.39 153.685 120.775 154.65 ;
		RECT	120.775 153.685 121.075 154.65 ;
		RECT	0.39 154.96 120.775 155.4 ;
		RECT	120.775 154.96 121.075 155.4 ;
		RECT	0.39 155.71 120.775 156.215 ;
		RECT	120.775 155.71 121.075 156.215 ;
		RECT	0.39 156.525 120.775 157.49 ;
		RECT	120.775 156.525 121.075 157.49 ;
		RECT	0.39 157.8 120.775 158.24 ;
		RECT	120.775 157.8 121.075 158.24 ;
		RECT	0.39 158.55 120.775 159.055 ;
		RECT	120.775 158.55 121.075 159.055 ;
		RECT	0.39 159.365 120.775 160.33 ;
		RECT	120.775 159.365 121.075 160.33 ;
		RECT	0.39 160.64 120.775 161.08 ;
		RECT	120.775 160.64 121.075 161.08 ;
		RECT	0.39 161.39 120.775 161.895 ;
		RECT	120.775 161.39 121.075 161.895 ;
		RECT	0.39 162.205 120.775 163.17 ;
		RECT	120.775 162.205 121.075 163.17 ;
		RECT	0.39 163.48 120.775 163.92 ;
		RECT	120.775 163.48 121.075 163.92 ;
		RECT	0.39 164.23 120.775 164.735 ;
		RECT	120.775 164.23 121.075 164.735 ;
		RECT	0.39 165.045 120.775 166.01 ;
		RECT	120.775 165.045 121.075 166.01 ;
		RECT	0.39 166.32 120.775 166.76 ;
		RECT	120.775 166.32 121.075 166.76 ;
		RECT	0.39 167.07 120.775 167.575 ;
		RECT	120.775 167.07 121.075 167.575 ;
		RECT	0.39 167.885 120.775 168.85 ;
		RECT	120.775 167.885 121.075 168.85 ;
		RECT	0.39 169.16 120.775 169.6 ;
		RECT	120.775 169.16 121.075 169.6 ;
		RECT	0.39 169.91 120.775 170.415 ;
		RECT	120.775 169.91 121.075 170.415 ;
		RECT	0.39 170.725 120.775 171.69 ;
		RECT	120.775 170.725 121.075 171.69 ;
		RECT	0.39 172 120.775 172.44 ;
		RECT	120.775 172 121.075 172.44 ;
		RECT	0.39 172.75 120.775 173.255 ;
		RECT	120.775 172.75 121.075 173.255 ;
		RECT	0.39 173.565 120.775 174.53 ;
		RECT	120.775 173.565 121.075 174.53 ;
		RECT	0.39 174.84 120.775 175.28 ;
		RECT	120.775 174.84 121.075 175.28 ;
		RECT	0.39 175.59 120.775 176.095 ;
		RECT	120.775 175.59 121.075 176.095 ;
		RECT	0.39 176.405 120.775 177.37 ;
		RECT	120.775 176.405 121.075 177.37 ;
		RECT	0.39 177.68 120.775 178.12 ;
		RECT	120.775 177.68 121.075 178.12 ;
		RECT	0.39 178.43 120.775 178.935 ;
		RECT	120.775 178.43 121.075 178.935 ;
		RECT	0.39 179.245 120.775 180.21 ;
		RECT	120.775 179.245 121.075 180.21 ;
		RECT	0.39 180.52 120.775 180.96 ;
		RECT	120.775 180.52 121.075 180.96 ;
		RECT	0.39 181.27 120.775 181.775 ;
		RECT	120.775 181.27 121.075 181.775 ;
		RECT	0.39 182.085 120.775 183.05 ;
		RECT	120.775 182.085 121.075 183.05 ;
		RECT	0.39 183.36 120.775 183.8 ;
		RECT	120.775 183.36 121.075 183.8 ;
		RECT	0.39 184.11 120.775 184.615 ;
		RECT	120.775 184.11 121.075 184.615 ;
		RECT	0.39 184.925 120.775 185.89 ;
		RECT	120.775 184.925 121.075 185.89 ;
		RECT	0.39 186.2 120.775 186.64 ;
		RECT	120.775 186.2 121.075 186.64 ;
		RECT	0.39 186.95 120.775 187.455 ;
		RECT	120.775 186.95 121.075 187.455 ;
		RECT	0.39 187.765 120.775 188.73 ;
		RECT	120.775 187.765 121.075 188.73 ;
		RECT	0.39 189.04 120.775 189.48 ;
		RECT	120.775 189.04 121.075 189.48 ;
		RECT	0.39 189.79 120.775 190.295 ;
		RECT	120.775 189.79 121.075 190.295 ;
		RECT	0.39 190.605 120.775 191.57 ;
		RECT	120.775 190.605 121.075 191.57 ;
		RECT	0.39 191.88 120.775 192.32 ;
		RECT	120.775 191.88 121.075 192.32 ;
		RECT	0.39 192.63 120.775 193.135 ;
		RECT	120.775 192.63 121.075 193.135 ;
		RECT	0.39 193.445 120.775 194.41 ;
		RECT	120.775 193.445 121.075 194.41 ;
		RECT	0.39 194.72 120.775 195.16 ;
		RECT	120.775 194.72 121.075 195.16 ;
		RECT	0.39 195.47 120.775 195.975 ;
		RECT	120.775 195.47 121.075 195.975 ;
		RECT	0.39 196.285 120.775 197.25 ;
		RECT	120.775 196.285 121.075 197.25 ;
		RECT	0.39 197.56 120.775 198 ;
		RECT	120.775 197.56 121.075 198 ;
		RECT	0.39 198.31 120.775 198.815 ;
		RECT	120.775 198.31 121.075 198.815 ;
		RECT	0.39 199.125 120.775 200.09 ;
		RECT	120.775 199.125 121.075 200.09 ;
		RECT	0.39 200.4 120.775 200.84 ;
		RECT	120.775 200.4 121.075 200.84 ;
		RECT	0.39 201.15 120.775 201.655 ;
		RECT	120.775 201.15 121.075 201.655 ;
		RECT	0.39 201.965 120.775 202.93 ;
		RECT	120.775 201.965 121.075 202.93 ;
		RECT	0.39 203.24 120.775 203.68 ;
		RECT	120.775 203.24 121.075 203.68 ;
		RECT	0.39 203.99 120.775 204.495 ;
		RECT	120.775 203.99 121.075 204.495 ;
		RECT	0.39 204.805 120.775 205.77 ;
		RECT	120.775 204.805 121.075 205.77 ;
		RECT	0.39 206.08 120.775 206.27 ;
		RECT	120.775 206.08 121.075 206.27 ;
		LAYER	VIA1 DESIGNRULEWIDTH 0.07 ;
		RECT	0 0 121.075 207.15 ;
		LAYER	VIA2 DESIGNRULEWIDTH 0.07 ;
		RECT	0.15 0 121.075 207.15 ;
		RECT	0 0 0.15 1.645 ;
		RECT	0.14 1.645 0.15 2.955 ;
		RECT	0 1.995 0.15 2.955 ;
		RECT	0 3.105 0.15 3.155 ;
		RECT	0 3.305 0.15 4.485 ;
		RECT	0.14 4.485 0.15 5.795 ;
		RECT	0 4.835 0.15 5.795 ;
		RECT	0 5.945 0.15 5.995 ;
		RECT	0 6.145 0.15 7.325 ;
		RECT	0.14 7.325 0.15 8.635 ;
		RECT	0 7.675 0.15 8.635 ;
		RECT	0 8.785 0.15 8.835 ;
		RECT	0 8.985 0.15 10.165 ;
		RECT	0.14 10.165 0.15 11.475 ;
		RECT	0 10.515 0.15 11.475 ;
		RECT	0 11.625 0.15 11.675 ;
		RECT	0 11.825 0.15 13.005 ;
		RECT	0.14 13.005 0.15 14.315 ;
		RECT	0 13.355 0.15 14.315 ;
		RECT	0 14.465 0.15 14.515 ;
		RECT	0 14.665 0.15 15.845 ;
		RECT	0.14 15.845 0.15 17.155 ;
		RECT	0 16.195 0.15 17.155 ;
		RECT	0 17.305 0.15 17.355 ;
		RECT	0 17.505 0.15 18.685 ;
		RECT	0.14 18.685 0.15 19.995 ;
		RECT	0 19.035 0.15 19.995 ;
		RECT	0 20.145 0.15 20.195 ;
		RECT	0 20.345 0.15 21.525 ;
		RECT	0.14 21.525 0.15 22.835 ;
		RECT	0 21.875 0.15 22.835 ;
		RECT	0 22.985 0.15 23.035 ;
		RECT	0 23.185 0.15 24.365 ;
		RECT	0.14 24.365 0.15 25.675 ;
		RECT	0 24.715 0.15 25.675 ;
		RECT	0 25.825 0.15 25.875 ;
		RECT	0 26.025 0.15 27.205 ;
		RECT	0.14 27.205 0.15 28.515 ;
		RECT	0 27.555 0.15 28.515 ;
		RECT	0 28.665 0.15 28.715 ;
		RECT	0 28.865 0.15 30.045 ;
		RECT	0.14 30.045 0.15 31.355 ;
		RECT	0 30.395 0.15 31.355 ;
		RECT	0 31.505 0.15 31.555 ;
		RECT	0 31.705 0.15 32.885 ;
		RECT	0.14 32.885 0.15 34.195 ;
		RECT	0 33.235 0.15 34.195 ;
		RECT	0 34.345 0.15 34.395 ;
		RECT	0 34.545 0.15 35.725 ;
		RECT	0.14 35.725 0.15 37.035 ;
		RECT	0 36.075 0.15 37.035 ;
		RECT	0 37.185 0.15 37.235 ;
		RECT	0 37.385 0.15 38.565 ;
		RECT	0.14 38.565 0.15 39.875 ;
		RECT	0 38.915 0.15 39.875 ;
		RECT	0 40.025 0.15 40.075 ;
		RECT	0 40.225 0.15 41.405 ;
		RECT	0.14 41.405 0.15 42.715 ;
		RECT	0 41.755 0.15 42.715 ;
		RECT	0 42.865 0.15 42.915 ;
		RECT	0 43.065 0.15 44.245 ;
		RECT	0.14 44.245 0.15 45.555 ;
		RECT	0 44.595 0.15 45.555 ;
		RECT	0 45.705 0.15 45.755 ;
		RECT	0 45.905 0.15 47.085 ;
		RECT	0.14 47.085 0.15 48.395 ;
		RECT	0 47.435 0.15 48.395 ;
		RECT	0 48.545 0.15 48.595 ;
		RECT	0 48.745 0.15 49.925 ;
		RECT	0.14 49.925 0.15 51.235 ;
		RECT	0 50.275 0.15 51.235 ;
		RECT	0 51.385 0.15 51.435 ;
		RECT	0 51.585 0.15 52.765 ;
		RECT	0.14 52.765 0.15 54.075 ;
		RECT	0 53.115 0.15 54.075 ;
		RECT	0 54.225 0.15 54.275 ;
		RECT	0 54.425 0.15 55.605 ;
		RECT	0.14 55.605 0.15 56.915 ;
		RECT	0 55.955 0.15 56.915 ;
		RECT	0 57.065 0.15 57.115 ;
		RECT	0 57.265 0.15 58.445 ;
		RECT	0.14 58.445 0.15 59.755 ;
		RECT	0 58.795 0.15 59.755 ;
		RECT	0 59.905 0.15 59.955 ;
		RECT	0 60.105 0.15 61.285 ;
		RECT	0.14 61.285 0.15 62.595 ;
		RECT	0 61.635 0.15 62.595 ;
		RECT	0 62.745 0.15 62.795 ;
		RECT	0 62.945 0.15 64.125 ;
		RECT	0.14 64.125 0.15 65.435 ;
		RECT	0 64.475 0.15 65.435 ;
		RECT	0 65.585 0.15 65.635 ;
		RECT	0 65.785 0.15 66.965 ;
		RECT	0.14 66.965 0.15 68.275 ;
		RECT	0 67.315 0.15 68.275 ;
		RECT	0 68.425 0.15 68.475 ;
		RECT	0 68.625 0.15 69.805 ;
		RECT	0.14 69.805 0.15 71.115 ;
		RECT	0 70.155 0.15 71.115 ;
		RECT	0 71.265 0.15 71.315 ;
		RECT	0 71.465 0.15 72.645 ;
		RECT	0.14 72.645 0.15 73.955 ;
		RECT	0 72.995 0.15 73.955 ;
		RECT	0 74.105 0.15 74.155 ;
		RECT	0 74.305 0.15 75.485 ;
		RECT	0.14 75.485 0.15 76.795 ;
		RECT	0 75.835 0.15 76.795 ;
		RECT	0 76.945 0.15 76.995 ;
		RECT	0 77.145 0.15 78.325 ;
		RECT	0.14 78.325 0.15 79.635 ;
		RECT	0 78.675 0.15 79.635 ;
		RECT	0 79.785 0.15 79.835 ;
		RECT	0 79.985 0.15 81.165 ;
		RECT	0.14 81.165 0.15 82.475 ;
		RECT	0 81.515 0.15 82.475 ;
		RECT	0 82.625 0.15 82.675 ;
		RECT	0 82.825 0.15 84.005 ;
		RECT	0.14 84.005 0.15 85.315 ;
		RECT	0 84.355 0.15 85.315 ;
		RECT	0 85.465 0.15 85.515 ;
		RECT	0 85.665 0.15 86.845 ;
		RECT	0.14 86.845 0.15 88.155 ;
		RECT	0 87.195 0.15 88.155 ;
		RECT	0 88.305 0.15 88.355 ;
		RECT	0 88.505 0.15 89.685 ;
		RECT	0.14 89.685 0.15 90.995 ;
		RECT	0 90.035 0.15 90.995 ;
		RECT	0 91.145 0.15 91.195 ;
		RECT	0 91.345 0.15 92.41 ;
		RECT	0.14 92.41 0.15 93.815 ;
		RECT	0 92.76 0.15 93.815 ;
		RECT	0 93.965 0.15 94.015 ;
		RECT	0 94.165 0.15 94.215 ;
		RECT	0 94.365 0.15 95.615 ;
		RECT	0 95.765 0.15 95.815 ;
		RECT	0 95.965 0.15 96.715 ;
		RECT	0 96.865 0.15 97.115 ;
		RECT	0 97.265 0.15 97.615 ;
		RECT	0 97.765 0.15 97.815 ;
		RECT	0.14 97.815 0.15 98.265 ;
		RECT	0 98.165 0.15 98.265 ;
		RECT	0 98.415 0.15 99.315 ;
		RECT	0 99.465 0.15 99.515 ;
		RECT	0 99.665 0.15 99.915 ;
		RECT	0 100.065 0.15 100.315 ;
		RECT	0 100.465 0.15 100.915 ;
		RECT	0 101.065 0.15 101.315 ;
		RECT	0 101.465 0.15 101.715 ;
		RECT	0 101.865 0.15 103.115 ;
		RECT	0 103.265 0.15 105.315 ;
		RECT	0 105.465 0.15 106.315 ;
		RECT	0 106.465 0.15 107.115 ;
		RECT	0 107.265 0.15 107.915 ;
		RECT	0 108.065 0.15 108.315 ;
		RECT	0.14 108.315 0.15 109.715 ;
		RECT	0 108.665 0.15 109.715 ;
		RECT	0 109.865 0.15 110.315 ;
		RECT	0 110.465 0.15 114.315 ;
		RECT	0.14 114.315 0.15 114.715 ;
		RECT	0 114.665 0.15 114.715 ;
		RECT	0.14 114.715 0.15 115.805 ;
		RECT	0 115.065 0.15 115.805 ;
		RECT	0 115.955 0.15 116.005 ;
		RECT	0 116.155 0.15 117.115 ;
		RECT	0.14 117.115 0.15 118.645 ;
		RECT	0 117.465 0.15 118.645 ;
		RECT	0 118.795 0.15 118.845 ;
		RECT	0 118.995 0.15 119.955 ;
		RECT	0.14 119.955 0.15 121.485 ;
		RECT	0 120.305 0.15 121.485 ;
		RECT	0 121.635 0.15 121.685 ;
		RECT	0 121.835 0.15 122.795 ;
		RECT	0.14 122.795 0.15 124.325 ;
		RECT	0 123.145 0.15 124.325 ;
		RECT	0 124.475 0.15 124.525 ;
		RECT	0 124.675 0.15 125.635 ;
		RECT	0.14 125.635 0.15 127.165 ;
		RECT	0 125.985 0.15 127.165 ;
		RECT	0 127.315 0.15 127.365 ;
		RECT	0 127.515 0.15 128.475 ;
		RECT	0.14 128.475 0.15 130.005 ;
		RECT	0 128.825 0.15 130.005 ;
		RECT	0 130.155 0.15 130.205 ;
		RECT	0 130.355 0.15 131.315 ;
		RECT	0.14 131.315 0.15 132.845 ;
		RECT	0 131.665 0.15 132.845 ;
		RECT	0 132.995 0.15 133.045 ;
		RECT	0 133.195 0.15 134.155 ;
		RECT	0.14 134.155 0.15 135.685 ;
		RECT	0 134.505 0.15 135.685 ;
		RECT	0 135.835 0.15 135.885 ;
		RECT	0 136.035 0.15 136.995 ;
		RECT	0.14 136.995 0.15 138.525 ;
		RECT	0 137.345 0.15 138.525 ;
		RECT	0 138.675 0.15 138.725 ;
		RECT	0 138.875 0.15 139.835 ;
		RECT	0.14 139.835 0.15 141.365 ;
		RECT	0 140.185 0.15 141.365 ;
		RECT	0 141.515 0.15 141.565 ;
		RECT	0 141.715 0.15 142.675 ;
		RECT	0.14 142.675 0.15 144.205 ;
		RECT	0 143.025 0.15 144.205 ;
		RECT	0 144.355 0.15 144.405 ;
		RECT	0 144.555 0.15 145.515 ;
		RECT	0.14 145.515 0.15 147.045 ;
		RECT	0 145.865 0.15 147.045 ;
		RECT	0 147.195 0.15 147.245 ;
		RECT	0 147.395 0.15 148.355 ;
		RECT	0.14 148.355 0.15 149.885 ;
		RECT	0 148.705 0.15 149.885 ;
		RECT	0 150.035 0.15 150.085 ;
		RECT	0 150.235 0.15 151.195 ;
		RECT	0.14 151.195 0.15 152.725 ;
		RECT	0 151.545 0.15 152.725 ;
		RECT	0 152.875 0.15 152.925 ;
		RECT	0 153.075 0.15 154.035 ;
		RECT	0.14 154.035 0.15 155.565 ;
		RECT	0 154.385 0.15 155.565 ;
		RECT	0 155.715 0.15 155.765 ;
		RECT	0 155.915 0.15 156.875 ;
		RECT	0.14 156.875 0.15 158.405 ;
		RECT	0 157.225 0.15 158.405 ;
		RECT	0 158.555 0.15 158.605 ;
		RECT	0 158.755 0.15 159.715 ;
		RECT	0.14 159.715 0.15 161.245 ;
		RECT	0 160.065 0.15 161.245 ;
		RECT	0 161.395 0.15 161.445 ;
		RECT	0 161.595 0.15 162.555 ;
		RECT	0.14 162.555 0.15 164.085 ;
		RECT	0 162.905 0.15 164.085 ;
		RECT	0 164.235 0.15 164.285 ;
		RECT	0 164.435 0.15 165.395 ;
		RECT	0.14 165.395 0.15 166.925 ;
		RECT	0 165.745 0.15 166.925 ;
		RECT	0 167.075 0.15 167.125 ;
		RECT	0 167.275 0.15 168.235 ;
		RECT	0.14 168.235 0.15 169.765 ;
		RECT	0 168.585 0.15 169.765 ;
		RECT	0 169.915 0.15 169.965 ;
		RECT	0 170.115 0.15 171.075 ;
		RECT	0.14 171.075 0.15 172.605 ;
		RECT	0 171.425 0.15 172.605 ;
		RECT	0 172.755 0.15 172.805 ;
		RECT	0 172.955 0.15 173.915 ;
		RECT	0.14 173.915 0.15 175.445 ;
		RECT	0 174.265 0.15 175.445 ;
		RECT	0 175.595 0.15 175.645 ;
		RECT	0 175.795 0.15 176.755 ;
		RECT	0.14 176.755 0.15 178.285 ;
		RECT	0 177.105 0.15 178.285 ;
		RECT	0 178.435 0.15 178.485 ;
		RECT	0 178.635 0.15 179.595 ;
		RECT	0.14 179.595 0.15 181.125 ;
		RECT	0 179.945 0.15 181.125 ;
		RECT	0 181.275 0.15 181.325 ;
		RECT	0 181.475 0.15 182.435 ;
		RECT	0.14 182.435 0.15 183.965 ;
		RECT	0 182.785 0.15 183.965 ;
		RECT	0 184.115 0.15 184.165 ;
		RECT	0 184.315 0.15 185.275 ;
		RECT	0.14 185.275 0.15 186.805 ;
		RECT	0 185.625 0.15 186.805 ;
		RECT	0 186.955 0.15 187.005 ;
		RECT	0 187.155 0.15 188.115 ;
		RECT	0.14 188.115 0.15 189.645 ;
		RECT	0 188.465 0.15 189.645 ;
		RECT	0 189.795 0.15 189.845 ;
		RECT	0 189.995 0.15 190.955 ;
		RECT	0.14 190.955 0.15 192.485 ;
		RECT	0 191.305 0.15 192.485 ;
		RECT	0 192.635 0.15 192.685 ;
		RECT	0 192.835 0.15 193.795 ;
		RECT	0.14 193.795 0.15 195.325 ;
		RECT	0 194.145 0.15 195.325 ;
		RECT	0 195.475 0.15 195.525 ;
		RECT	0 195.675 0.15 196.635 ;
		RECT	0.14 196.635 0.15 198.165 ;
		RECT	0 196.985 0.15 198.165 ;
		RECT	0 198.315 0.15 198.365 ;
		RECT	0 198.515 0.15 199.475 ;
		RECT	0.14 199.475 0.15 201.005 ;
		RECT	0 199.825 0.15 201.005 ;
		RECT	0 201.155 0.15 201.205 ;
		RECT	0 201.355 0.15 202.315 ;
		RECT	0.14 202.315 0.15 203.845 ;
		RECT	0 202.665 0.15 203.845 ;
		RECT	0 203.995 0.15 204.045 ;
		RECT	0 204.195 0.15 205.155 ;
		RECT	0.14 205.155 0.15 205.505 ;
		RECT	0 205.505 0.15 207.15 ;
		RECT	0.065 109.565 0.115 109.615 ;
		RECT	0.065 109.765 0.115 109.815 ;
		RECT	0.065 107.965 0.115 108.015 ;
		RECT	0.065 108.165 0.115 108.215 ;
		RECT	0.065 103.965 0.115 104.015 ;
		RECT	0.065 104.165 0.115 104.215 ;
		RECT	0.065 103.165 0.115 103.215 ;
		RECT	0.065 103.365 0.115 103.415 ;
		RECT	0.065 102.765 0.115 102.815 ;
		RECT	0.065 102.965 0.115 103.015 ;
		RECT	0.065 96.115 0.115 96.165 ;
		RECT	0.065 96.315 0.115 96.365 ;
		RECT	0.065 95.165 0.115 95.215 ;
		RECT	0.065 95.365 0.115 95.415 ;
		RECT	0.065 94.765 0.115 94.815 ;
		RECT	0.065 94.965 0.115 95.015 ;
		RECT	0.065 112.765 0.115 112.815 ;
		RECT	0.065 112.965 0.115 113.015 ;
		RECT	0.065 104.765 0.115 104.815 ;
		RECT	0.065 104.965 0.115 105.015 ;
		RECT	0.065 101.165 0.115 101.215 ;
		RECT	0.065 101.365 0.115 101.415 ;
		RECT	0.065 113.965 0.115 114.015 ;
		RECT	0.065 114.165 0.115 114.215 ;
		RECT	0.065 111.965 0.115 112.015 ;
		RECT	0.065 112.165 0.115 112.215 ;
		RECT	0.065 96.565 0.115 96.615 ;
		RECT	0.065 96.765 0.115 96.815 ;
		RECT	0.065 97.465 0.115 97.515 ;
		RECT	0.065 97.665 0.115 97.715 ;
		RECT	0.065 100.765 0.115 100.815 ;
		RECT	0.065 100.965 0.115 101.015 ;
		RECT	0.065 94.265 0.115 94.315 ;
		RECT	0.065 94.465 0.115 94.515 ;
		RECT	0.065 108.765 0.115 108.815 ;
		RECT	0.065 108.965 0.115 109.015 ;
		RECT	0.065 106.365 0.115 106.415 ;
		RECT	0.065 106.565 0.115 106.615 ;
		RECT	0.065 110.765 0.115 110.815 ;
		RECT	0.065 110.965 0.115 111.015 ;
		RECT	0.065 102.365 0.115 102.415 ;
		RECT	0.065 102.565 0.115 102.615 ;
		RECT	0.065 99.965 0.115 100.015 ;
		RECT	0.065 100.165 0.115 100.215 ;
		RECT	0.065 106.765 0.115 106.815 ;
		RECT	0.065 106.965 0.115 107.015 ;
		RECT	0.065 109.965 0.115 110.015 ;
		RECT	0.065 110.165 0.115 110.215 ;
		RECT	0.065 112.365 0.115 112.415 ;
		RECT	0.065 112.565 0.115 112.615 ;
		RECT	0.065 110.365 0.115 110.415 ;
		RECT	0.065 110.565 0.115 110.615 ;
		RECT	0.065 111.165 0.115 111.215 ;
		RECT	0.065 111.365 0.115 111.415 ;
		RECT	0.065 105.165 0.115 105.215 ;
		RECT	0.065 105.365 0.115 105.415 ;
		RECT	0.065 104.365 0.115 104.415 ;
		RECT	0.065 104.565 0.115 104.615 ;
		RECT	0.065 103.565 0.115 103.615 ;
		RECT	0.065 103.765 0.115 103.815 ;
		RECT	0.065 93.865 0.115 93.915 ;
		RECT	0.065 94.065 0.115 94.115 ;
		RECT	0.065 113.565 0.115 113.615 ;
		RECT	0.065 113.765 0.115 113.815 ;
		RECT	0.065 96.965 0.115 97.015 ;
		RECT	0.065 97.165 0.115 97.215 ;
		RECT	0.065 101.565 0.115 101.615 ;
		RECT	0.065 101.765 0.115 101.815 ;
		RECT	0.065 101.965 0.115 102.015 ;
		RECT	0.065 102.165 0.115 102.215 ;
		RECT	0.065 100.365 0.115 100.415 ;
		RECT	0.065 100.565 0.115 100.615 ;
		RECT	0.065 99.365 0.115 99.415 ;
		RECT	0.065 99.565 0.115 99.615 ;
		RECT	0.065 98.565 0.115 98.615 ;
		RECT	0.065 98.765 0.115 98.815 ;
		RECT	0.065 111.565 0.115 111.615 ;
		RECT	0.065 111.765 0.115 111.815 ;
		RECT	0.065 113.165 0.115 113.215 ;
		RECT	0.065 113.365 0.115 113.415 ;
		RECT	0.065 95.865 0.115 95.915 ;
		RECT	0.065 95.665 0.115 95.715 ;
		RECT	0.065 105.965 0.115 106.015 ;
		RECT	0.065 106.165 0.115 106.215 ;
		RECT	0.065 105.565 0.115 105.615 ;
		RECT	0.065 105.765 0.115 105.815 ;
		RECT	0.065 107.165 0.115 107.215 ;
		RECT	0.065 107.365 0.115 107.415 ;
		RECT	0.065 98.315 0.115 98.365 ;
		RECT	0.06 93.665 0.11 93.715 ;
		RECT	0.06 99.165 0.11 99.215 ;
		RECT	0.06 98.065 0.11 98.115 ;
		RECT	0.06 114.365 0.11 114.415 ;
		RECT	0.06 109.365 0.11 109.415 ;
		RECT	0.06 92.66 0.11 92.71 ;
		RECT	0.06 93.165 0.11 93.215 ;
		RECT	0.06 114.965 0.11 115.015 ;
		RECT	0.06 108.365 0.11 108.415 ;
		RECT	0.065 109.565 0.115 109.615 ;
		RECT	0.065 109.765 0.115 109.815 ;
		RECT	0.065 107.965 0.115 108.015 ;
		RECT	0.065 108.165 0.115 108.215 ;
		RECT	0.065 103.965 0.115 104.015 ;
		RECT	0.065 104.165 0.115 104.215 ;
		RECT	0.065 103.165 0.115 103.215 ;
		RECT	0.065 103.365 0.115 103.415 ;
		RECT	0.065 102.765 0.115 102.815 ;
		RECT	0.065 102.965 0.115 103.015 ;
		RECT	0.065 96.115 0.115 96.165 ;
		RECT	0.065 96.315 0.115 96.365 ;
		RECT	0.065 95.165 0.115 95.215 ;
		RECT	0.065 95.365 0.115 95.415 ;
		RECT	0.065 94.765 0.115 94.815 ;
		RECT	0.065 94.965 0.115 95.015 ;
		RECT	0.065 112.765 0.115 112.815 ;
		RECT	0.065 112.965 0.115 113.015 ;
		RECT	0.065 104.765 0.115 104.815 ;
		RECT	0.065 104.965 0.115 105.015 ;
		RECT	0.065 101.165 0.115 101.215 ;
		RECT	0.065 101.365 0.115 101.415 ;
		RECT	0.065 113.965 0.115 114.015 ;
		RECT	0.065 114.165 0.115 114.215 ;
		RECT	0.065 111.965 0.115 112.015 ;
		RECT	0.065 112.165 0.115 112.215 ;
		RECT	0.065 96.565 0.115 96.615 ;
		RECT	0.065 96.765 0.115 96.815 ;
		RECT	0.065 97.465 0.115 97.515 ;
		RECT	0.065 97.665 0.115 97.715 ;
		RECT	0.065 100.765 0.115 100.815 ;
		RECT	0.065 100.965 0.115 101.015 ;
		RECT	0.065 94.265 0.115 94.315 ;
		RECT	0.065 94.465 0.115 94.515 ;
		RECT	0.065 108.765 0.115 108.815 ;
		RECT	0.065 108.965 0.115 109.015 ;
		RECT	0.065 106.365 0.115 106.415 ;
		RECT	0.065 106.565 0.115 106.615 ;
		RECT	0.065 110.765 0.115 110.815 ;
		RECT	0.065 110.965 0.115 111.015 ;
		RECT	0.065 102.365 0.115 102.415 ;
		RECT	0.065 102.565 0.115 102.615 ;
		RECT	0.065 99.965 0.115 100.015 ;
		RECT	0.065 100.165 0.115 100.215 ;
		RECT	0.065 106.765 0.115 106.815 ;
		RECT	0.065 106.965 0.115 107.015 ;
		RECT	0.065 109.965 0.115 110.015 ;
		RECT	0.065 110.165 0.115 110.215 ;
		RECT	0.065 112.365 0.115 112.415 ;
		RECT	0.065 112.565 0.115 112.615 ;
		RECT	0.065 110.365 0.115 110.415 ;
		RECT	0.065 110.565 0.115 110.615 ;
		RECT	0.065 111.165 0.115 111.215 ;
		RECT	0.065 111.365 0.115 111.415 ;
		RECT	0.065 105.165 0.115 105.215 ;
		RECT	0.065 105.365 0.115 105.415 ;
		RECT	0.065 104.365 0.115 104.415 ;
		RECT	0.065 104.565 0.115 104.615 ;
		RECT	0.065 103.565 0.115 103.615 ;
		RECT	0.065 103.765 0.115 103.815 ;
		RECT	0.065 93.865 0.115 93.915 ;
		RECT	0.065 94.065 0.115 94.115 ;
		RECT	0.065 113.565 0.115 113.615 ;
		RECT	0.065 113.765 0.115 113.815 ;
		RECT	0.065 96.965 0.115 97.015 ;
		RECT	0.065 97.165 0.115 97.215 ;
		RECT	0.065 101.565 0.115 101.615 ;
		RECT	0.065 101.765 0.115 101.815 ;
		RECT	0.065 101.965 0.115 102.015 ;
		RECT	0.065 102.165 0.115 102.215 ;
		RECT	0.065 100.365 0.115 100.415 ;
		RECT	0.065 100.565 0.115 100.615 ;
		RECT	0.065 99.365 0.115 99.415 ;
		RECT	0.065 99.565 0.115 99.615 ;
		RECT	0.065 98.565 0.115 98.615 ;
		RECT	0.065 98.765 0.115 98.815 ;
		RECT	0.065 111.565 0.115 111.615 ;
		RECT	0.065 111.765 0.115 111.815 ;
		RECT	0.065 113.165 0.115 113.215 ;
		RECT	0.065 113.365 0.115 113.415 ;
		RECT	0.065 95.865 0.115 95.915 ;
		RECT	0.065 95.665 0.115 95.715 ;
		RECT	0.065 105.965 0.115 106.015 ;
		RECT	0.065 106.165 0.115 106.215 ;
		RECT	0.065 105.565 0.115 105.615 ;
		RECT	0.065 105.765 0.115 105.815 ;
		RECT	0.065 107.165 0.115 107.215 ;
		RECT	0.065 107.365 0.115 107.415 ;
		RECT	0.065 98.315 0.115 98.365 ;
		RECT	0.06 93.665 0.11 93.715 ;
		RECT	0.06 99.165 0.11 99.215 ;
		RECT	0.06 98.065 0.11 98.115 ;
		RECT	0.06 114.365 0.11 114.415 ;
		RECT	0.06 109.365 0.11 109.415 ;
		RECT	0.06 92.66 0.11 92.71 ;
		RECT	0.06 93.165 0.11 93.215 ;
		RECT	0.06 114.965 0.11 115.015 ;
		RECT	0.06 108.365 0.11 108.415 ;
		RECT	0.06 4.735 0.11 4.785 ;
		RECT	0.06 4.285 0.11 4.335 ;
		RECT	0.065 5.445 0.115 5.495 ;
		RECT	0.065 5.645 0.115 5.695 ;
		RECT	0.065 5.845 0.115 5.895 ;
		RECT	0.065 6.045 0.115 6.095 ;
		RECT	0.06 4.735 0.11 4.785 ;
		RECT	0.06 4.285 0.11 4.335 ;
		RECT	0.065 5.445 0.115 5.495 ;
		RECT	0.065 5.645 0.115 5.695 ;
		RECT	0.065 5.845 0.115 5.895 ;
		RECT	0.065 6.045 0.115 6.095 ;
		RECT	0.06 30.295 0.11 30.345 ;
		RECT	0.06 29.845 0.11 29.895 ;
		RECT	0.065 31.005 0.115 31.055 ;
		RECT	0.065 31.205 0.115 31.255 ;
		RECT	0.065 31.405 0.115 31.455 ;
		RECT	0.065 31.605 0.115 31.655 ;
		RECT	0.06 30.295 0.11 30.345 ;
		RECT	0.06 29.845 0.11 29.895 ;
		RECT	0.065 31.005 0.115 31.055 ;
		RECT	0.065 31.205 0.115 31.255 ;
		RECT	0.065 31.405 0.115 31.455 ;
		RECT	0.065 31.605 0.115 31.655 ;
		RECT	0.06 33.135 0.11 33.185 ;
		RECT	0.06 32.685 0.11 32.735 ;
		RECT	0.065 33.845 0.115 33.895 ;
		RECT	0.065 34.045 0.115 34.095 ;
		RECT	0.065 34.245 0.115 34.295 ;
		RECT	0.065 34.445 0.115 34.495 ;
		RECT	0.06 33.135 0.11 33.185 ;
		RECT	0.06 32.685 0.11 32.735 ;
		RECT	0.065 33.845 0.115 33.895 ;
		RECT	0.065 34.045 0.115 34.095 ;
		RECT	0.065 34.245 0.115 34.295 ;
		RECT	0.065 34.445 0.115 34.495 ;
		RECT	0.06 35.975 0.11 36.025 ;
		RECT	0.06 35.525 0.11 35.575 ;
		RECT	0.065 36.685 0.115 36.735 ;
		RECT	0.065 36.885 0.115 36.935 ;
		RECT	0.065 37.085 0.115 37.135 ;
		RECT	0.065 37.285 0.115 37.335 ;
		RECT	0.06 35.975 0.11 36.025 ;
		RECT	0.06 35.525 0.11 35.575 ;
		RECT	0.065 36.685 0.115 36.735 ;
		RECT	0.065 36.885 0.115 36.935 ;
		RECT	0.065 37.085 0.115 37.135 ;
		RECT	0.065 37.285 0.115 37.335 ;
		RECT	0.06 38.815 0.11 38.865 ;
		RECT	0.06 38.365 0.11 38.415 ;
		RECT	0.065 39.525 0.115 39.575 ;
		RECT	0.065 39.725 0.115 39.775 ;
		RECT	0.065 39.925 0.115 39.975 ;
		RECT	0.065 40.125 0.115 40.175 ;
		RECT	0.06 38.815 0.11 38.865 ;
		RECT	0.06 38.365 0.11 38.415 ;
		RECT	0.065 39.525 0.115 39.575 ;
		RECT	0.065 39.725 0.115 39.775 ;
		RECT	0.065 39.925 0.115 39.975 ;
		RECT	0.065 40.125 0.115 40.175 ;
		RECT	0.06 41.655 0.11 41.705 ;
		RECT	0.06 41.205 0.11 41.255 ;
		RECT	0.065 42.365 0.115 42.415 ;
		RECT	0.065 42.565 0.115 42.615 ;
		RECT	0.065 42.765 0.115 42.815 ;
		RECT	0.065 42.965 0.115 43.015 ;
		RECT	0.06 41.655 0.11 41.705 ;
		RECT	0.06 41.205 0.11 41.255 ;
		RECT	0.065 42.365 0.115 42.415 ;
		RECT	0.065 42.565 0.115 42.615 ;
		RECT	0.065 42.765 0.115 42.815 ;
		RECT	0.065 42.965 0.115 43.015 ;
		RECT	0.06 44.495 0.11 44.545 ;
		RECT	0.06 44.045 0.11 44.095 ;
		RECT	0.065 45.205 0.115 45.255 ;
		RECT	0.065 45.405 0.115 45.455 ;
		RECT	0.065 45.605 0.115 45.655 ;
		RECT	0.065 45.805 0.115 45.855 ;
		RECT	0.06 44.495 0.11 44.545 ;
		RECT	0.06 44.045 0.11 44.095 ;
		RECT	0.065 45.205 0.115 45.255 ;
		RECT	0.065 45.405 0.115 45.455 ;
		RECT	0.065 45.605 0.115 45.655 ;
		RECT	0.065 45.805 0.115 45.855 ;
		RECT	0.06 47.335 0.11 47.385 ;
		RECT	0.06 46.885 0.11 46.935 ;
		RECT	0.065 48.045 0.115 48.095 ;
		RECT	0.065 48.245 0.115 48.295 ;
		RECT	0.065 48.445 0.115 48.495 ;
		RECT	0.065 48.645 0.115 48.695 ;
		RECT	0.06 47.335 0.11 47.385 ;
		RECT	0.06 46.885 0.11 46.935 ;
		RECT	0.065 48.045 0.115 48.095 ;
		RECT	0.065 48.245 0.115 48.295 ;
		RECT	0.065 48.445 0.115 48.495 ;
		RECT	0.065 48.645 0.115 48.695 ;
		RECT	0.06 50.175 0.11 50.225 ;
		RECT	0.06 49.725 0.11 49.775 ;
		RECT	0.065 50.885 0.115 50.935 ;
		RECT	0.065 51.085 0.115 51.135 ;
		RECT	0.065 51.285 0.115 51.335 ;
		RECT	0.065 51.485 0.115 51.535 ;
		RECT	0.06 50.175 0.11 50.225 ;
		RECT	0.06 49.725 0.11 49.775 ;
		RECT	0.065 50.885 0.115 50.935 ;
		RECT	0.065 51.085 0.115 51.135 ;
		RECT	0.065 51.285 0.115 51.335 ;
		RECT	0.065 51.485 0.115 51.535 ;
		RECT	0.06 53.015 0.11 53.065 ;
		RECT	0.06 52.565 0.11 52.615 ;
		RECT	0.065 53.725 0.115 53.775 ;
		RECT	0.065 53.925 0.115 53.975 ;
		RECT	0.065 54.125 0.115 54.175 ;
		RECT	0.065 54.325 0.115 54.375 ;
		RECT	0.06 53.015 0.11 53.065 ;
		RECT	0.06 52.565 0.11 52.615 ;
		RECT	0.065 53.725 0.115 53.775 ;
		RECT	0.065 53.925 0.115 53.975 ;
		RECT	0.065 54.125 0.115 54.175 ;
		RECT	0.065 54.325 0.115 54.375 ;
		RECT	0.06 55.855 0.11 55.905 ;
		RECT	0.06 55.405 0.11 55.455 ;
		RECT	0.065 56.565 0.115 56.615 ;
		RECT	0.065 56.765 0.115 56.815 ;
		RECT	0.065 56.965 0.115 57.015 ;
		RECT	0.065 57.165 0.115 57.215 ;
		RECT	0.06 55.855 0.11 55.905 ;
		RECT	0.06 55.405 0.11 55.455 ;
		RECT	0.065 56.565 0.115 56.615 ;
		RECT	0.065 56.765 0.115 56.815 ;
		RECT	0.065 56.965 0.115 57.015 ;
		RECT	0.065 57.165 0.115 57.215 ;
		RECT	0.06 7.575 0.11 7.625 ;
		RECT	0.06 7.125 0.11 7.175 ;
		RECT	0.065 8.285 0.115 8.335 ;
		RECT	0.065 8.485 0.115 8.535 ;
		RECT	0.065 8.685 0.115 8.735 ;
		RECT	0.065 8.885 0.115 8.935 ;
		RECT	0.06 7.575 0.11 7.625 ;
		RECT	0.06 7.125 0.11 7.175 ;
		RECT	0.065 8.285 0.115 8.335 ;
		RECT	0.065 8.485 0.115 8.535 ;
		RECT	0.065 8.685 0.115 8.735 ;
		RECT	0.065 8.885 0.115 8.935 ;
		RECT	0.06 58.695 0.11 58.745 ;
		RECT	0.06 58.245 0.11 58.295 ;
		RECT	0.065 59.405 0.115 59.455 ;
		RECT	0.065 59.605 0.115 59.655 ;
		RECT	0.065 59.805 0.115 59.855 ;
		RECT	0.065 60.005 0.115 60.055 ;
		RECT	0.06 58.695 0.11 58.745 ;
		RECT	0.06 58.245 0.11 58.295 ;
		RECT	0.065 59.405 0.115 59.455 ;
		RECT	0.065 59.605 0.115 59.655 ;
		RECT	0.065 59.805 0.115 59.855 ;
		RECT	0.065 60.005 0.115 60.055 ;
		RECT	0.06 61.535 0.11 61.585 ;
		RECT	0.06 61.085 0.11 61.135 ;
		RECT	0.065 62.245 0.115 62.295 ;
		RECT	0.065 62.445 0.115 62.495 ;
		RECT	0.065 62.645 0.115 62.695 ;
		RECT	0.065 62.845 0.115 62.895 ;
		RECT	0.06 61.535 0.11 61.585 ;
		RECT	0.06 61.085 0.11 61.135 ;
		RECT	0.065 62.245 0.115 62.295 ;
		RECT	0.065 62.445 0.115 62.495 ;
		RECT	0.065 62.645 0.115 62.695 ;
		RECT	0.065 62.845 0.115 62.895 ;
		RECT	0.06 64.375 0.11 64.425 ;
		RECT	0.06 63.925 0.11 63.975 ;
		RECT	0.065 65.085 0.115 65.135 ;
		RECT	0.065 65.285 0.115 65.335 ;
		RECT	0.065 65.485 0.115 65.535 ;
		RECT	0.065 65.685 0.115 65.735 ;
		RECT	0.06 64.375 0.11 64.425 ;
		RECT	0.06 63.925 0.11 63.975 ;
		RECT	0.065 65.085 0.115 65.135 ;
		RECT	0.065 65.285 0.115 65.335 ;
		RECT	0.065 65.485 0.115 65.535 ;
		RECT	0.065 65.685 0.115 65.735 ;
		RECT	0.06 67.215 0.11 67.265 ;
		RECT	0.06 66.765 0.11 66.815 ;
		RECT	0.065 67.925 0.115 67.975 ;
		RECT	0.065 68.125 0.115 68.175 ;
		RECT	0.065 68.325 0.115 68.375 ;
		RECT	0.065 68.525 0.115 68.575 ;
		RECT	0.06 67.215 0.11 67.265 ;
		RECT	0.06 66.765 0.11 66.815 ;
		RECT	0.065 67.925 0.115 67.975 ;
		RECT	0.065 68.125 0.115 68.175 ;
		RECT	0.065 68.325 0.115 68.375 ;
		RECT	0.065 68.525 0.115 68.575 ;
		RECT	0.06 70.055 0.11 70.105 ;
		RECT	0.06 69.605 0.11 69.655 ;
		RECT	0.065 70.765 0.115 70.815 ;
		RECT	0.065 70.965 0.115 71.015 ;
		RECT	0.065 71.165 0.115 71.215 ;
		RECT	0.065 71.365 0.115 71.415 ;
		RECT	0.06 70.055 0.11 70.105 ;
		RECT	0.06 69.605 0.11 69.655 ;
		RECT	0.065 70.765 0.115 70.815 ;
		RECT	0.065 70.965 0.115 71.015 ;
		RECT	0.065 71.165 0.115 71.215 ;
		RECT	0.065 71.365 0.115 71.415 ;
		RECT	0.06 72.895 0.11 72.945 ;
		RECT	0.06 72.445 0.11 72.495 ;
		RECT	0.065 73.605 0.115 73.655 ;
		RECT	0.065 73.805 0.115 73.855 ;
		RECT	0.065 74.005 0.115 74.055 ;
		RECT	0.065 74.205 0.115 74.255 ;
		RECT	0.06 72.895 0.11 72.945 ;
		RECT	0.06 72.445 0.11 72.495 ;
		RECT	0.065 73.605 0.115 73.655 ;
		RECT	0.065 73.805 0.115 73.855 ;
		RECT	0.065 74.005 0.115 74.055 ;
		RECT	0.065 74.205 0.115 74.255 ;
		RECT	0.06 75.735 0.11 75.785 ;
		RECT	0.06 75.285 0.11 75.335 ;
		RECT	0.065 76.445 0.115 76.495 ;
		RECT	0.065 76.645 0.115 76.695 ;
		RECT	0.065 76.845 0.115 76.895 ;
		RECT	0.065 77.045 0.115 77.095 ;
		RECT	0.06 75.735 0.11 75.785 ;
		RECT	0.06 75.285 0.11 75.335 ;
		RECT	0.065 76.445 0.115 76.495 ;
		RECT	0.065 76.645 0.115 76.695 ;
		RECT	0.065 76.845 0.115 76.895 ;
		RECT	0.065 77.045 0.115 77.095 ;
		RECT	0.06 78.575 0.11 78.625 ;
		RECT	0.06 78.125 0.11 78.175 ;
		RECT	0.065 79.285 0.115 79.335 ;
		RECT	0.065 79.485 0.115 79.535 ;
		RECT	0.065 79.685 0.115 79.735 ;
		RECT	0.065 79.885 0.115 79.935 ;
		RECT	0.06 78.575 0.11 78.625 ;
		RECT	0.06 78.125 0.11 78.175 ;
		RECT	0.065 79.285 0.115 79.335 ;
		RECT	0.065 79.485 0.115 79.535 ;
		RECT	0.065 79.685 0.115 79.735 ;
		RECT	0.065 79.885 0.115 79.935 ;
		RECT	0.06 81.415 0.11 81.465 ;
		RECT	0.06 80.965 0.11 81.015 ;
		RECT	0.065 82.125 0.115 82.175 ;
		RECT	0.065 82.325 0.115 82.375 ;
		RECT	0.065 82.525 0.115 82.575 ;
		RECT	0.065 82.725 0.115 82.775 ;
		RECT	0.06 81.415 0.11 81.465 ;
		RECT	0.06 80.965 0.11 81.015 ;
		RECT	0.065 82.125 0.115 82.175 ;
		RECT	0.065 82.325 0.115 82.375 ;
		RECT	0.065 82.525 0.115 82.575 ;
		RECT	0.065 82.725 0.115 82.775 ;
		RECT	0.06 84.255 0.11 84.305 ;
		RECT	0.06 83.805 0.11 83.855 ;
		RECT	0.065 84.965 0.115 85.015 ;
		RECT	0.065 85.165 0.115 85.215 ;
		RECT	0.065 85.365 0.115 85.415 ;
		RECT	0.065 85.565 0.115 85.615 ;
		RECT	0.06 84.255 0.11 84.305 ;
		RECT	0.06 83.805 0.11 83.855 ;
		RECT	0.065 84.965 0.115 85.015 ;
		RECT	0.065 85.165 0.115 85.215 ;
		RECT	0.065 85.365 0.115 85.415 ;
		RECT	0.065 85.565 0.115 85.615 ;
		RECT	0.06 10.415 0.11 10.465 ;
		RECT	0.06 9.965 0.11 10.015 ;
		RECT	0.065 11.125 0.115 11.175 ;
		RECT	0.065 11.325 0.115 11.375 ;
		RECT	0.065 11.525 0.115 11.575 ;
		RECT	0.065 11.725 0.115 11.775 ;
		RECT	0.06 10.415 0.11 10.465 ;
		RECT	0.06 9.965 0.11 10.015 ;
		RECT	0.065 11.125 0.115 11.175 ;
		RECT	0.065 11.325 0.115 11.375 ;
		RECT	0.065 11.525 0.115 11.575 ;
		RECT	0.065 11.725 0.115 11.775 ;
		RECT	0.06 87.095 0.11 87.145 ;
		RECT	0.06 86.645 0.11 86.695 ;
		RECT	0.065 87.805 0.115 87.855 ;
		RECT	0.065 88.005 0.115 88.055 ;
		RECT	0.065 88.205 0.115 88.255 ;
		RECT	0.065 88.405 0.115 88.455 ;
		RECT	0.06 87.095 0.11 87.145 ;
		RECT	0.06 86.645 0.11 86.695 ;
		RECT	0.065 87.805 0.115 87.855 ;
		RECT	0.065 88.005 0.115 88.055 ;
		RECT	0.065 88.205 0.115 88.255 ;
		RECT	0.065 88.405 0.115 88.455 ;
		RECT	0.06 13.255 0.11 13.305 ;
		RECT	0.06 12.805 0.11 12.855 ;
		RECT	0.065 13.965 0.115 14.015 ;
		RECT	0.065 14.165 0.115 14.215 ;
		RECT	0.065 14.365 0.115 14.415 ;
		RECT	0.065 14.565 0.115 14.615 ;
		RECT	0.06 13.255 0.11 13.305 ;
		RECT	0.06 12.805 0.11 12.855 ;
		RECT	0.065 13.965 0.115 14.015 ;
		RECT	0.065 14.165 0.115 14.215 ;
		RECT	0.065 14.365 0.115 14.415 ;
		RECT	0.065 14.565 0.115 14.615 ;
		RECT	0.06 16.095 0.11 16.145 ;
		RECT	0.06 15.645 0.11 15.695 ;
		RECT	0.065 16.805 0.115 16.855 ;
		RECT	0.065 17.005 0.115 17.055 ;
		RECT	0.065 17.205 0.115 17.255 ;
		RECT	0.065 17.405 0.115 17.455 ;
		RECT	0.06 16.095 0.11 16.145 ;
		RECT	0.06 15.645 0.11 15.695 ;
		RECT	0.065 16.805 0.115 16.855 ;
		RECT	0.065 17.005 0.115 17.055 ;
		RECT	0.065 17.205 0.115 17.255 ;
		RECT	0.065 17.405 0.115 17.455 ;
		RECT	0.06 18.935 0.11 18.985 ;
		RECT	0.06 18.485 0.11 18.535 ;
		RECT	0.065 19.645 0.115 19.695 ;
		RECT	0.065 19.845 0.115 19.895 ;
		RECT	0.065 20.045 0.115 20.095 ;
		RECT	0.065 20.245 0.115 20.295 ;
		RECT	0.06 18.935 0.11 18.985 ;
		RECT	0.06 18.485 0.11 18.535 ;
		RECT	0.065 19.645 0.115 19.695 ;
		RECT	0.065 19.845 0.115 19.895 ;
		RECT	0.065 20.045 0.115 20.095 ;
		RECT	0.065 20.245 0.115 20.295 ;
		RECT	0.06 21.775 0.11 21.825 ;
		RECT	0.06 21.325 0.11 21.375 ;
		RECT	0.065 22.485 0.115 22.535 ;
		RECT	0.065 22.685 0.115 22.735 ;
		RECT	0.065 22.885 0.115 22.935 ;
		RECT	0.065 23.085 0.115 23.135 ;
		RECT	0.06 21.775 0.11 21.825 ;
		RECT	0.06 21.325 0.11 21.375 ;
		RECT	0.065 22.485 0.115 22.535 ;
		RECT	0.065 22.685 0.115 22.735 ;
		RECT	0.065 22.885 0.115 22.935 ;
		RECT	0.065 23.085 0.115 23.135 ;
		RECT	0.06 24.615 0.11 24.665 ;
		RECT	0.06 24.165 0.11 24.215 ;
		RECT	0.065 25.325 0.115 25.375 ;
		RECT	0.065 25.525 0.115 25.575 ;
		RECT	0.065 25.725 0.115 25.775 ;
		RECT	0.065 25.925 0.115 25.975 ;
		RECT	0.06 24.615 0.11 24.665 ;
		RECT	0.06 24.165 0.11 24.215 ;
		RECT	0.065 25.325 0.115 25.375 ;
		RECT	0.065 25.525 0.115 25.575 ;
		RECT	0.065 25.725 0.115 25.775 ;
		RECT	0.065 25.925 0.115 25.975 ;
		RECT	0.06 27.455 0.11 27.505 ;
		RECT	0.06 27.005 0.11 27.055 ;
		RECT	0.065 28.165 0.115 28.215 ;
		RECT	0.065 28.365 0.115 28.415 ;
		RECT	0.065 28.565 0.115 28.615 ;
		RECT	0.065 28.765 0.115 28.815 ;
		RECT	0.06 27.455 0.11 27.505 ;
		RECT	0.06 27.005 0.11 27.055 ;
		RECT	0.065 28.165 0.115 28.215 ;
		RECT	0.065 28.365 0.115 28.415 ;
		RECT	0.065 28.565 0.115 28.615 ;
		RECT	0.065 28.765 0.115 28.815 ;
		RECT	0.06 1.895 0.11 1.945 ;
		RECT	0.06 1.445 0.11 1.495 ;
		RECT	0.065 2.605 0.115 2.655 ;
		RECT	0.065 2.805 0.115 2.855 ;
		RECT	0.065 3.005 0.115 3.055 ;
		RECT	0.065 3.205 0.115 3.255 ;
		RECT	0.06 1.895 0.11 1.945 ;
		RECT	0.06 1.445 0.11 1.495 ;
		RECT	0.065 2.605 0.115 2.655 ;
		RECT	0.065 2.805 0.115 2.855 ;
		RECT	0.065 3.005 0.115 3.055 ;
		RECT	0.065 3.205 0.115 3.255 ;
		RECT	0.06 89.935 0.11 89.985 ;
		RECT	0.06 89.485 0.11 89.535 ;
		RECT	0.065 90.645 0.115 90.695 ;
		RECT	0.065 90.845 0.115 90.895 ;
		RECT	0.065 91.045 0.115 91.095 ;
		RECT	0.065 91.245 0.115 91.295 ;
		RECT	0.06 89.935 0.11 89.985 ;
		RECT	0.06 89.485 0.11 89.535 ;
		RECT	0.065 90.645 0.115 90.695 ;
		RECT	0.065 90.845 0.115 90.895 ;
		RECT	0.065 91.045 0.115 91.095 ;
		RECT	0.065 91.245 0.115 91.295 ;
		RECT	0.06 0.7 0.11 0.75 ;
		RECT	0.06 0.3 0.11 0.35 ;
		RECT	0.06 0.7 0.11 0.75 ;
		RECT	0.06 0.3 0.11 0.35 ;
		RECT	0.06 120.005 0.11 120.055 ;
		RECT	0.06 120.455 0.11 120.505 ;
		RECT	0.065 119.295 0.115 119.345 ;
		RECT	0.065 119.095 0.115 119.145 ;
		RECT	0.065 118.895 0.115 118.945 ;
		RECT	0.065 118.695 0.115 118.745 ;
		RECT	0.06 120.005 0.11 120.055 ;
		RECT	0.06 120.455 0.11 120.505 ;
		RECT	0.065 119.295 0.115 119.345 ;
		RECT	0.065 119.095 0.115 119.145 ;
		RECT	0.065 118.895 0.115 118.945 ;
		RECT	0.065 118.695 0.115 118.745 ;
		RECT	0.06 145.565 0.11 145.615 ;
		RECT	0.06 146.015 0.11 146.065 ;
		RECT	0.065 144.855 0.115 144.905 ;
		RECT	0.065 144.655 0.115 144.705 ;
		RECT	0.065 144.455 0.115 144.505 ;
		RECT	0.065 144.255 0.115 144.305 ;
		RECT	0.06 145.565 0.11 145.615 ;
		RECT	0.06 146.015 0.11 146.065 ;
		RECT	0.065 144.855 0.115 144.905 ;
		RECT	0.065 144.655 0.115 144.705 ;
		RECT	0.065 144.455 0.115 144.505 ;
		RECT	0.065 144.255 0.115 144.305 ;
		RECT	0.06 148.405 0.11 148.455 ;
		RECT	0.06 148.855 0.11 148.905 ;
		RECT	0.065 147.695 0.115 147.745 ;
		RECT	0.065 147.495 0.115 147.545 ;
		RECT	0.065 147.295 0.115 147.345 ;
		RECT	0.065 147.095 0.115 147.145 ;
		RECT	0.06 148.405 0.11 148.455 ;
		RECT	0.06 148.855 0.11 148.905 ;
		RECT	0.065 147.695 0.115 147.745 ;
		RECT	0.065 147.495 0.115 147.545 ;
		RECT	0.065 147.295 0.115 147.345 ;
		RECT	0.065 147.095 0.115 147.145 ;
		RECT	0.06 151.245 0.11 151.295 ;
		RECT	0.06 151.695 0.11 151.745 ;
		RECT	0.065 150.535 0.115 150.585 ;
		RECT	0.065 150.335 0.115 150.385 ;
		RECT	0.065 150.135 0.115 150.185 ;
		RECT	0.065 149.935 0.115 149.985 ;
		RECT	0.06 151.245 0.11 151.295 ;
		RECT	0.06 151.695 0.11 151.745 ;
		RECT	0.065 150.535 0.115 150.585 ;
		RECT	0.065 150.335 0.115 150.385 ;
		RECT	0.065 150.135 0.115 150.185 ;
		RECT	0.065 149.935 0.115 149.985 ;
		RECT	0.06 154.085 0.11 154.135 ;
		RECT	0.06 154.535 0.11 154.585 ;
		RECT	0.065 153.375 0.115 153.425 ;
		RECT	0.065 153.175 0.115 153.225 ;
		RECT	0.065 152.975 0.115 153.025 ;
		RECT	0.065 152.775 0.115 152.825 ;
		RECT	0.06 154.085 0.11 154.135 ;
		RECT	0.06 154.535 0.11 154.585 ;
		RECT	0.065 153.375 0.115 153.425 ;
		RECT	0.065 153.175 0.115 153.225 ;
		RECT	0.065 152.975 0.115 153.025 ;
		RECT	0.065 152.775 0.115 152.825 ;
		RECT	0.06 156.925 0.11 156.975 ;
		RECT	0.06 157.375 0.11 157.425 ;
		RECT	0.065 156.215 0.115 156.265 ;
		RECT	0.065 156.015 0.115 156.065 ;
		RECT	0.065 155.815 0.115 155.865 ;
		RECT	0.065 155.615 0.115 155.665 ;
		RECT	0.06 156.925 0.11 156.975 ;
		RECT	0.06 157.375 0.11 157.425 ;
		RECT	0.065 156.215 0.115 156.265 ;
		RECT	0.065 156.015 0.115 156.065 ;
		RECT	0.065 155.815 0.115 155.865 ;
		RECT	0.065 155.615 0.115 155.665 ;
		RECT	0.06 159.765 0.11 159.815 ;
		RECT	0.06 160.215 0.11 160.265 ;
		RECT	0.065 159.055 0.115 159.105 ;
		RECT	0.065 158.855 0.115 158.905 ;
		RECT	0.065 158.655 0.115 158.705 ;
		RECT	0.065 158.455 0.115 158.505 ;
		RECT	0.06 159.765 0.11 159.815 ;
		RECT	0.06 160.215 0.11 160.265 ;
		RECT	0.065 159.055 0.115 159.105 ;
		RECT	0.065 158.855 0.115 158.905 ;
		RECT	0.065 158.655 0.115 158.705 ;
		RECT	0.065 158.455 0.115 158.505 ;
		RECT	0.06 162.605 0.11 162.655 ;
		RECT	0.06 163.055 0.11 163.105 ;
		RECT	0.065 161.895 0.115 161.945 ;
		RECT	0.065 161.695 0.115 161.745 ;
		RECT	0.065 161.495 0.115 161.545 ;
		RECT	0.065 161.295 0.115 161.345 ;
		RECT	0.06 162.605 0.11 162.655 ;
		RECT	0.06 163.055 0.11 163.105 ;
		RECT	0.065 161.895 0.115 161.945 ;
		RECT	0.065 161.695 0.115 161.745 ;
		RECT	0.065 161.495 0.115 161.545 ;
		RECT	0.065 161.295 0.115 161.345 ;
		RECT	0.06 165.445 0.11 165.495 ;
		RECT	0.06 165.895 0.11 165.945 ;
		RECT	0.065 164.735 0.115 164.785 ;
		RECT	0.065 164.535 0.115 164.585 ;
		RECT	0.065 164.335 0.115 164.385 ;
		RECT	0.065 164.135 0.115 164.185 ;
		RECT	0.06 165.445 0.11 165.495 ;
		RECT	0.06 165.895 0.11 165.945 ;
		RECT	0.065 164.735 0.115 164.785 ;
		RECT	0.065 164.535 0.115 164.585 ;
		RECT	0.065 164.335 0.115 164.385 ;
		RECT	0.065 164.135 0.115 164.185 ;
		RECT	0.06 168.285 0.11 168.335 ;
		RECT	0.06 168.735 0.11 168.785 ;
		RECT	0.065 167.575 0.115 167.625 ;
		RECT	0.065 167.375 0.115 167.425 ;
		RECT	0.065 167.175 0.115 167.225 ;
		RECT	0.065 166.975 0.115 167.025 ;
		RECT	0.06 168.285 0.11 168.335 ;
		RECT	0.06 168.735 0.11 168.785 ;
		RECT	0.065 167.575 0.115 167.625 ;
		RECT	0.065 167.375 0.115 167.425 ;
		RECT	0.065 167.175 0.115 167.225 ;
		RECT	0.065 166.975 0.115 167.025 ;
		RECT	0.06 171.125 0.11 171.175 ;
		RECT	0.06 171.575 0.11 171.625 ;
		RECT	0.065 170.415 0.115 170.465 ;
		RECT	0.065 170.215 0.115 170.265 ;
		RECT	0.065 170.015 0.115 170.065 ;
		RECT	0.065 169.815 0.115 169.865 ;
		RECT	0.06 171.125 0.11 171.175 ;
		RECT	0.06 171.575 0.11 171.625 ;
		RECT	0.065 170.415 0.115 170.465 ;
		RECT	0.065 170.215 0.115 170.265 ;
		RECT	0.065 170.015 0.115 170.065 ;
		RECT	0.065 169.815 0.115 169.865 ;
		RECT	0.06 122.845 0.11 122.895 ;
		RECT	0.06 123.295 0.11 123.345 ;
		RECT	0.065 122.135 0.115 122.185 ;
		RECT	0.065 121.935 0.115 121.985 ;
		RECT	0.065 121.735 0.115 121.785 ;
		RECT	0.065 121.535 0.115 121.585 ;
		RECT	0.06 122.845 0.11 122.895 ;
		RECT	0.06 123.295 0.11 123.345 ;
		RECT	0.065 122.135 0.115 122.185 ;
		RECT	0.065 121.935 0.115 121.985 ;
		RECT	0.065 121.735 0.115 121.785 ;
		RECT	0.065 121.535 0.115 121.585 ;
		RECT	0.06 173.965 0.11 174.015 ;
		RECT	0.06 174.415 0.11 174.465 ;
		RECT	0.065 173.255 0.115 173.305 ;
		RECT	0.065 173.055 0.115 173.105 ;
		RECT	0.065 172.855 0.115 172.905 ;
		RECT	0.065 172.655 0.115 172.705 ;
		RECT	0.06 173.965 0.11 174.015 ;
		RECT	0.06 174.415 0.11 174.465 ;
		RECT	0.065 173.255 0.115 173.305 ;
		RECT	0.065 173.055 0.115 173.105 ;
		RECT	0.065 172.855 0.115 172.905 ;
		RECT	0.065 172.655 0.115 172.705 ;
		RECT	0.06 176.805 0.11 176.855 ;
		RECT	0.06 177.255 0.11 177.305 ;
		RECT	0.065 176.095 0.115 176.145 ;
		RECT	0.065 175.895 0.115 175.945 ;
		RECT	0.065 175.695 0.115 175.745 ;
		RECT	0.065 175.495 0.115 175.545 ;
		RECT	0.06 176.805 0.11 176.855 ;
		RECT	0.06 177.255 0.11 177.305 ;
		RECT	0.065 176.095 0.115 176.145 ;
		RECT	0.065 175.895 0.115 175.945 ;
		RECT	0.065 175.695 0.115 175.745 ;
		RECT	0.065 175.495 0.115 175.545 ;
		RECT	0.06 179.645 0.11 179.695 ;
		RECT	0.06 180.095 0.11 180.145 ;
		RECT	0.065 178.935 0.115 178.985 ;
		RECT	0.065 178.735 0.115 178.785 ;
		RECT	0.065 178.535 0.115 178.585 ;
		RECT	0.065 178.335 0.115 178.385 ;
		RECT	0.06 179.645 0.11 179.695 ;
		RECT	0.06 180.095 0.11 180.145 ;
		RECT	0.065 178.935 0.115 178.985 ;
		RECT	0.065 178.735 0.115 178.785 ;
		RECT	0.065 178.535 0.115 178.585 ;
		RECT	0.065 178.335 0.115 178.385 ;
		RECT	0.06 182.485 0.11 182.535 ;
		RECT	0.06 182.935 0.11 182.985 ;
		RECT	0.065 181.775 0.115 181.825 ;
		RECT	0.065 181.575 0.115 181.625 ;
		RECT	0.065 181.375 0.115 181.425 ;
		RECT	0.065 181.175 0.115 181.225 ;
		RECT	0.06 182.485 0.11 182.535 ;
		RECT	0.06 182.935 0.11 182.985 ;
		RECT	0.065 181.775 0.115 181.825 ;
		RECT	0.065 181.575 0.115 181.625 ;
		RECT	0.065 181.375 0.115 181.425 ;
		RECT	0.065 181.175 0.115 181.225 ;
		RECT	0.06 185.325 0.11 185.375 ;
		RECT	0.06 185.775 0.11 185.825 ;
		RECT	0.065 184.615 0.115 184.665 ;
		RECT	0.065 184.415 0.115 184.465 ;
		RECT	0.065 184.215 0.115 184.265 ;
		RECT	0.065 184.015 0.115 184.065 ;
		RECT	0.06 185.325 0.11 185.375 ;
		RECT	0.06 185.775 0.11 185.825 ;
		RECT	0.065 184.615 0.115 184.665 ;
		RECT	0.065 184.415 0.115 184.465 ;
		RECT	0.065 184.215 0.115 184.265 ;
		RECT	0.065 184.015 0.115 184.065 ;
		RECT	0.06 188.165 0.11 188.215 ;
		RECT	0.06 188.615 0.11 188.665 ;
		RECT	0.065 187.455 0.115 187.505 ;
		RECT	0.065 187.255 0.115 187.305 ;
		RECT	0.065 187.055 0.115 187.105 ;
		RECT	0.065 186.855 0.115 186.905 ;
		RECT	0.06 188.165 0.11 188.215 ;
		RECT	0.06 188.615 0.11 188.665 ;
		RECT	0.065 187.455 0.115 187.505 ;
		RECT	0.065 187.255 0.115 187.305 ;
		RECT	0.065 187.055 0.115 187.105 ;
		RECT	0.065 186.855 0.115 186.905 ;
		RECT	0.06 191.005 0.11 191.055 ;
		RECT	0.06 191.455 0.11 191.505 ;
		RECT	0.065 190.295 0.115 190.345 ;
		RECT	0.065 190.095 0.115 190.145 ;
		RECT	0.065 189.895 0.115 189.945 ;
		RECT	0.065 189.695 0.115 189.745 ;
		RECT	0.06 191.005 0.11 191.055 ;
		RECT	0.06 191.455 0.11 191.505 ;
		RECT	0.065 190.295 0.115 190.345 ;
		RECT	0.065 190.095 0.115 190.145 ;
		RECT	0.065 189.895 0.115 189.945 ;
		RECT	0.065 189.695 0.115 189.745 ;
		RECT	0.06 193.845 0.11 193.895 ;
		RECT	0.06 194.295 0.11 194.345 ;
		RECT	0.065 193.135 0.115 193.185 ;
		RECT	0.065 192.935 0.115 192.985 ;
		RECT	0.065 192.735 0.115 192.785 ;
		RECT	0.065 192.535 0.115 192.585 ;
		RECT	0.06 193.845 0.11 193.895 ;
		RECT	0.06 194.295 0.11 194.345 ;
		RECT	0.065 193.135 0.115 193.185 ;
		RECT	0.065 192.935 0.115 192.985 ;
		RECT	0.065 192.735 0.115 192.785 ;
		RECT	0.065 192.535 0.115 192.585 ;
		RECT	0.06 196.685 0.11 196.735 ;
		RECT	0.06 197.135 0.11 197.185 ;
		RECT	0.065 195.975 0.115 196.025 ;
		RECT	0.065 195.775 0.115 195.825 ;
		RECT	0.065 195.575 0.115 195.625 ;
		RECT	0.065 195.375 0.115 195.425 ;
		RECT	0.06 196.685 0.11 196.735 ;
		RECT	0.06 197.135 0.11 197.185 ;
		RECT	0.065 195.975 0.115 196.025 ;
		RECT	0.065 195.775 0.115 195.825 ;
		RECT	0.065 195.575 0.115 195.625 ;
		RECT	0.065 195.375 0.115 195.425 ;
		RECT	0.06 199.525 0.11 199.575 ;
		RECT	0.06 199.975 0.11 200.025 ;
		RECT	0.065 198.815 0.115 198.865 ;
		RECT	0.065 198.615 0.115 198.665 ;
		RECT	0.065 198.415 0.115 198.465 ;
		RECT	0.065 198.215 0.115 198.265 ;
		RECT	0.06 199.525 0.11 199.575 ;
		RECT	0.06 199.975 0.11 200.025 ;
		RECT	0.065 198.815 0.115 198.865 ;
		RECT	0.065 198.615 0.115 198.665 ;
		RECT	0.065 198.415 0.115 198.465 ;
		RECT	0.065 198.215 0.115 198.265 ;
		RECT	0.06 125.685 0.11 125.735 ;
		RECT	0.06 126.135 0.11 126.185 ;
		RECT	0.065 124.975 0.115 125.025 ;
		RECT	0.065 124.775 0.115 124.825 ;
		RECT	0.065 124.575 0.115 124.625 ;
		RECT	0.065 124.375 0.115 124.425 ;
		RECT	0.06 125.685 0.11 125.735 ;
		RECT	0.06 126.135 0.11 126.185 ;
		RECT	0.065 124.975 0.115 125.025 ;
		RECT	0.065 124.775 0.115 124.825 ;
		RECT	0.065 124.575 0.115 124.625 ;
		RECT	0.065 124.375 0.115 124.425 ;
		RECT	0.06 202.365 0.11 202.415 ;
		RECT	0.06 202.815 0.11 202.865 ;
		RECT	0.065 201.655 0.115 201.705 ;
		RECT	0.065 201.455 0.115 201.505 ;
		RECT	0.065 201.255 0.115 201.305 ;
		RECT	0.065 201.055 0.115 201.105 ;
		RECT	0.06 202.365 0.11 202.415 ;
		RECT	0.06 202.815 0.11 202.865 ;
		RECT	0.065 201.655 0.115 201.705 ;
		RECT	0.065 201.455 0.115 201.505 ;
		RECT	0.065 201.255 0.115 201.305 ;
		RECT	0.065 201.055 0.115 201.105 ;
		RECT	0.06 128.525 0.11 128.575 ;
		RECT	0.06 128.975 0.11 129.025 ;
		RECT	0.065 127.815 0.115 127.865 ;
		RECT	0.065 127.615 0.115 127.665 ;
		RECT	0.065 127.415 0.115 127.465 ;
		RECT	0.065 127.215 0.115 127.265 ;
		RECT	0.06 128.525 0.11 128.575 ;
		RECT	0.06 128.975 0.11 129.025 ;
		RECT	0.065 127.815 0.115 127.865 ;
		RECT	0.065 127.615 0.115 127.665 ;
		RECT	0.065 127.415 0.115 127.465 ;
		RECT	0.065 127.215 0.115 127.265 ;
		RECT	0.06 131.365 0.11 131.415 ;
		RECT	0.06 131.815 0.11 131.865 ;
		RECT	0.065 130.655 0.115 130.705 ;
		RECT	0.065 130.455 0.115 130.505 ;
		RECT	0.065 130.255 0.115 130.305 ;
		RECT	0.065 130.055 0.115 130.105 ;
		RECT	0.06 131.365 0.11 131.415 ;
		RECT	0.06 131.815 0.11 131.865 ;
		RECT	0.065 130.655 0.115 130.705 ;
		RECT	0.065 130.455 0.115 130.505 ;
		RECT	0.065 130.255 0.115 130.305 ;
		RECT	0.065 130.055 0.115 130.105 ;
		RECT	0.06 134.205 0.11 134.255 ;
		RECT	0.06 134.655 0.11 134.705 ;
		RECT	0.065 133.495 0.115 133.545 ;
		RECT	0.065 133.295 0.115 133.345 ;
		RECT	0.065 133.095 0.115 133.145 ;
		RECT	0.065 132.895 0.115 132.945 ;
		RECT	0.06 134.205 0.11 134.255 ;
		RECT	0.06 134.655 0.11 134.705 ;
		RECT	0.065 133.495 0.115 133.545 ;
		RECT	0.065 133.295 0.115 133.345 ;
		RECT	0.065 133.095 0.115 133.145 ;
		RECT	0.065 132.895 0.115 132.945 ;
		RECT	0.06 137.045 0.11 137.095 ;
		RECT	0.06 137.495 0.11 137.545 ;
		RECT	0.065 136.335 0.115 136.385 ;
		RECT	0.065 136.135 0.115 136.185 ;
		RECT	0.065 135.935 0.115 135.985 ;
		RECT	0.065 135.735 0.115 135.785 ;
		RECT	0.06 137.045 0.11 137.095 ;
		RECT	0.06 137.495 0.11 137.545 ;
		RECT	0.065 136.335 0.115 136.385 ;
		RECT	0.065 136.135 0.115 136.185 ;
		RECT	0.065 135.935 0.115 135.985 ;
		RECT	0.065 135.735 0.115 135.785 ;
		RECT	0.06 139.885 0.11 139.935 ;
		RECT	0.06 140.335 0.11 140.385 ;
		RECT	0.065 139.175 0.115 139.225 ;
		RECT	0.065 138.975 0.115 139.025 ;
		RECT	0.065 138.775 0.115 138.825 ;
		RECT	0.065 138.575 0.115 138.625 ;
		RECT	0.06 139.885 0.11 139.935 ;
		RECT	0.06 140.335 0.11 140.385 ;
		RECT	0.065 139.175 0.115 139.225 ;
		RECT	0.065 138.975 0.115 139.025 ;
		RECT	0.065 138.775 0.115 138.825 ;
		RECT	0.065 138.575 0.115 138.625 ;
		RECT	0.06 142.725 0.11 142.775 ;
		RECT	0.06 143.175 0.11 143.225 ;
		RECT	0.065 142.015 0.115 142.065 ;
		RECT	0.065 141.815 0.115 141.865 ;
		RECT	0.065 141.615 0.115 141.665 ;
		RECT	0.065 141.415 0.115 141.465 ;
		RECT	0.06 142.725 0.11 142.775 ;
		RECT	0.06 143.175 0.11 143.225 ;
		RECT	0.065 142.015 0.115 142.065 ;
		RECT	0.065 141.815 0.115 141.865 ;
		RECT	0.065 141.615 0.115 141.665 ;
		RECT	0.065 141.415 0.115 141.465 ;
		RECT	0.06 117.165 0.11 117.215 ;
		RECT	0.06 117.615 0.11 117.665 ;
		RECT	0.065 116.455 0.115 116.505 ;
		RECT	0.065 116.255 0.115 116.305 ;
		RECT	0.065 116.055 0.115 116.105 ;
		RECT	0.065 115.855 0.115 115.905 ;
		RECT	0.06 117.165 0.11 117.215 ;
		RECT	0.06 117.615 0.11 117.665 ;
		RECT	0.065 116.455 0.115 116.505 ;
		RECT	0.065 116.255 0.115 116.305 ;
		RECT	0.065 116.055 0.115 116.105 ;
		RECT	0.065 115.855 0.115 115.905 ;
		RECT	0.06 205.205 0.11 205.255 ;
		RECT	0.06 205.655 0.11 205.705 ;
		RECT	0.065 204.495 0.115 204.545 ;
		RECT	0.065 204.295 0.115 204.345 ;
		RECT	0.065 204.095 0.115 204.145 ;
		RECT	0.065 203.895 0.115 203.945 ;
		RECT	0.06 205.205 0.11 205.255 ;
		RECT	0.06 205.655 0.11 205.705 ;
		RECT	0.065 204.495 0.115 204.545 ;
		RECT	0.065 204.295 0.115 204.345 ;
		RECT	0.065 204.095 0.115 204.145 ;
		RECT	0.065 203.895 0.115 203.945 ;
		RECT	0.06 206.4 0.11 206.45 ;
		RECT	0.06 206.8 0.11 206.85 ;
		RECT	0.06 206.4 0.11 206.45 ;
		RECT	0.06 206.8 0.11 206.85 ;
		LAYER	VIA3 DESIGNRULEWIDTH 0.07 ;
		RECT	0.39 0 121.075 207.15 ;
	END

END sram1024x64

END LIBRARY

